VERSION 5.8 ;
BUSBITCHARS "[]" ;
DIVIDERCHAR "/" ;
UNITS
    DATABASE MICRONS 1000 ;
END UNITS

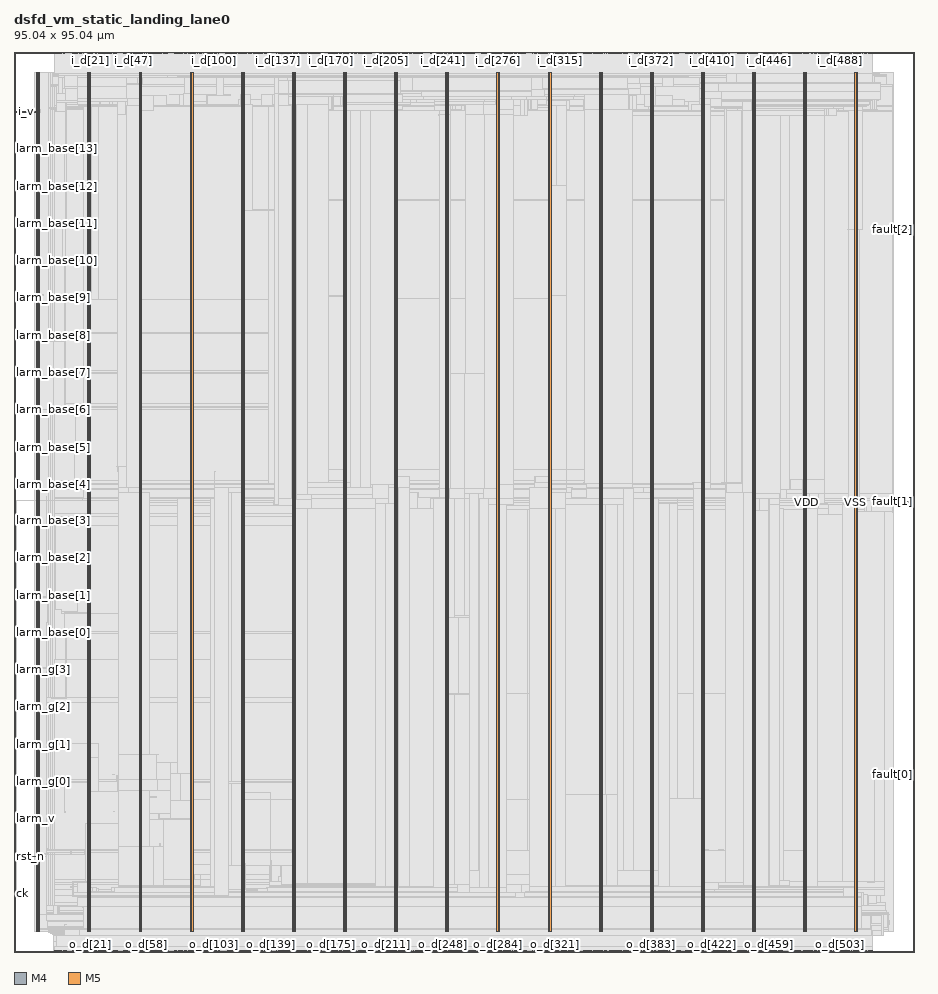
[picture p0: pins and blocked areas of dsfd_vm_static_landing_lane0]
MACRO dsfd_vm_static_landing_lane0
  FOREIGN dsfd_vm_static_landing_lane0 0 0 ;
  CLASS BLOCK ;
  SIZE 95.04 BY 95.04 ;
  PIN ck
    DIRECTION INPUT ;
    USE SIGNAL ;
    PORT
      LAYER M4 ;
        RECT  0 6.192 0.192 6.216 ;
    END
    PORT
      LAYER M4 ;
        RECT  0.156 6.192 0.275 6.216 ;
    END
  END ck
  PIN fault[0]
    DIRECTION OUTPUT ;
    USE SIGNAL ;
    PORT
      LAYER M4 ;
        RECT  94.848 18.72 95.04 18.744 ;
    END
    PORT
      LAYER M4 ;
        RECT  93.481 18.72 94.86 18.744 ;
    END
  END fault[0]
  PIN fault[1]
    DIRECTION OUTPUT ;
    USE SIGNAL ;
    PORT
      LAYER M4 ;
        RECT  94.848 47.52 95.04 47.544 ;
    END
    PORT
      LAYER M4 ;
        RECT  94.057 47.52 94.86 47.544 ;
    END
  END fault[1]
  PIN fault[2]
    DIRECTION OUTPUT ;
    USE SIGNAL ;
    PORT
      LAYER M4 ;
        RECT  94.848 76.32 95.04 76.344 ;
    END
    PORT
      LAYER M4 ;
        RECT  93.481 76.32 94.86 76.344 ;
    END
  END fault[2]
  PIN i_d[0]
    DIRECTION INPUT ;
    USE SIGNAL ;
    PORT
      LAYER M5 ;
        RECT  4.32 94.848 4.344 95.04 ;
    END
  END i_d[0]
  PIN i_d[100]
    DIRECTION INPUT ;
    USE SIGNAL ;
    PORT
      LAYER M5 ;
        RECT  21.12 94.848 21.144 95.04 ;
    END
  END i_d[100]
  PIN i_d[101]
    DIRECTION INPUT ;
    USE SIGNAL ;
    PORT
      LAYER M5 ;
        RECT  21.264 94.848 21.288 95.04 ;
    END
  END i_d[101]
  PIN i_d[102]
    DIRECTION INPUT ;
    USE SIGNAL ;
    PORT
      LAYER M5 ;
        RECT  21.408 94.848 21.432 95.04 ;
    END
  END i_d[102]
  PIN i_d[103]
    DIRECTION INPUT ;
    USE SIGNAL ;
    PORT
      LAYER M5 ;
        RECT  21.552 94.848 21.576 95.04 ;
    END
  END i_d[103]
  PIN i_d[104]
    DIRECTION INPUT ;
    USE SIGNAL ;
    PORT
      LAYER M5 ;
        RECT  22.368 94.848 22.392 95.04 ;
    END
  END i_d[104]
  PIN i_d[105]
    DIRECTION INPUT ;
    USE SIGNAL ;
    PORT
      LAYER M5 ;
        RECT  22.512 94.848 22.536 95.04 ;
    END
  END i_d[105]
  PIN i_d[106]
    DIRECTION INPUT ;
    USE SIGNAL ;
    PORT
      LAYER M5 ;
        RECT  22.656 94.848 22.68 95.04 ;
    END
  END i_d[106]
  PIN i_d[107]
    DIRECTION INPUT ;
    USE SIGNAL ;
    PORT
      LAYER M5 ;
        RECT  22.8 94.848 22.824 95.04 ;
    END
  END i_d[107]
  PIN i_d[108]
    DIRECTION INPUT ;
    USE SIGNAL ;
    PORT
      LAYER M5 ;
        RECT  22.944 94.848 22.968 95.04 ;
    END
  END i_d[108]
  PIN i_d[109]
    DIRECTION INPUT ;
    USE SIGNAL ;
    PORT
      LAYER M5 ;
        RECT  23.088 94.848 23.112 95.04 ;
    END
  END i_d[109]
  PIN i_d[10]
    DIRECTION INPUT ;
    USE SIGNAL ;
    PORT
      LAYER M5 ;
        RECT  6.432 94.848 6.456 95.04 ;
    END
  END i_d[10]
  PIN i_d[110]
    DIRECTION INPUT ;
    USE SIGNAL ;
    PORT
      LAYER M5 ;
        RECT  23.232 94.848 23.256 95.04 ;
    END
  END i_d[110]
  PIN i_d[111]
    DIRECTION INPUT ;
    USE SIGNAL ;
    PORT
      LAYER M5 ;
        RECT  23.376 94.848 23.4 95.04 ;
    END
  END i_d[111]
  PIN i_d[112]
    DIRECTION INPUT ;
    USE SIGNAL ;
    PORT
      LAYER M5 ;
        RECT  23.52 94.848 23.544 95.04 ;
    END
  END i_d[112]
  PIN i_d[113]
    DIRECTION INPUT ;
    USE SIGNAL ;
    PORT
      LAYER M5 ;
        RECT  23.664 94.848 23.688 95.04 ;
    END
  END i_d[113]
  PIN i_d[114]
    DIRECTION INPUT ;
    USE SIGNAL ;
    PORT
      LAYER M5 ;
        RECT  23.808 94.848 23.832 95.04 ;
    END
  END i_d[114]
  PIN i_d[115]
    DIRECTION INPUT ;
    USE SIGNAL ;
    PORT
      LAYER M5 ;
        RECT  23.952 94.848 23.976 95.04 ;
    END
  END i_d[115]
  PIN i_d[116]
    DIRECTION INPUT ;
    USE SIGNAL ;
    PORT
      LAYER M5 ;
        RECT  24.096 94.848 24.12 95.04 ;
    END
  END i_d[116]
  PIN i_d[117]
    DIRECTION INPUT ;
    USE SIGNAL ;
    PORT
      LAYER M5 ;
        RECT  24.24 94.848 24.264 95.04 ;
    END
  END i_d[117]
  PIN i_d[118]
    DIRECTION INPUT ;
    USE SIGNAL ;
    PORT
      LAYER M5 ;
        RECT  24.384 94.848 24.408 95.04 ;
    END
  END i_d[118]
  PIN i_d[119]
    DIRECTION INPUT ;
    USE SIGNAL ;
    PORT
      LAYER M5 ;
        RECT  24.528 94.848 24.552 95.04 ;
    END
  END i_d[119]
  PIN i_d[11]
    DIRECTION INPUT ;
    USE SIGNAL ;
    PORT
      LAYER M5 ;
        RECT  6.576 94.848 6.6 95.04 ;
    END
  END i_d[11]
  PIN i_d[120]
    DIRECTION INPUT ;
    USE SIGNAL ;
    PORT
      LAYER M5 ;
        RECT  24.816 94.848 24.84 95.04 ;
    END
  END i_d[120]
  PIN i_d[121]
    DIRECTION INPUT ;
    USE SIGNAL ;
    PORT
      LAYER M5 ;
        RECT  24.96 94.848 24.984 95.04 ;
    END
  END i_d[121]
  PIN i_d[122]
    DIRECTION INPUT ;
    USE SIGNAL ;
    PORT
      LAYER M5 ;
        RECT  25.104 94.848 25.128 95.04 ;
    END
  END i_d[122]
  PIN i_d[123]
    DIRECTION INPUT ;
    USE SIGNAL ;
    PORT
      LAYER M5 ;
        RECT  25.248 94.848 25.272 95.04 ;
    END
  END i_d[123]
  PIN i_d[124]
    DIRECTION INPUT ;
    USE SIGNAL ;
    PORT
      LAYER M5 ;
        RECT  25.392 94.848 25.416 95.04 ;
    END
  END i_d[124]
  PIN i_d[125]
    DIRECTION INPUT ;
    USE SIGNAL ;
    PORT
      LAYER M5 ;
        RECT  25.536 94.848 25.56 95.04 ;
    END
  END i_d[125]
  PIN i_d[126]
    DIRECTION INPUT ;
    USE SIGNAL ;
    PORT
      LAYER M5 ;
        RECT  25.68 94.848 25.704 95.04 ;
    END
  END i_d[126]
  PIN i_d[127]
    DIRECTION INPUT ;
    USE SIGNAL ;
    PORT
      LAYER M5 ;
        RECT  25.824 94.848 25.848 95.04 ;
    END
  END i_d[127]
  PIN i_d[128]
    DIRECTION INPUT ;
    USE SIGNAL ;
    PORT
      LAYER M5 ;
        RECT  25.968 94.848 25.992 95.04 ;
    END
  END i_d[128]
  PIN i_d[129]
    DIRECTION INPUT ;
    USE SIGNAL ;
    PORT
      LAYER M5 ;
        RECT  26.112 94.848 26.136 95.04 ;
    END
  END i_d[129]
  PIN i_d[12]
    DIRECTION INPUT ;
    USE SIGNAL ;
    PORT
      LAYER M5 ;
        RECT  6.72 94.848 6.744 95.04 ;
    END
  END i_d[12]
  PIN i_d[130]
    DIRECTION INPUT ;
    USE SIGNAL ;
    PORT
      LAYER M5 ;
        RECT  26.256 94.848 26.28 95.04 ;
    END
  END i_d[130]
  PIN i_d[131]
    DIRECTION INPUT ;
    USE SIGNAL ;
    PORT
      LAYER M5 ;
        RECT  26.4 94.848 26.424 95.04 ;
    END
  END i_d[131]
  PIN i_d[132]
    DIRECTION INPUT ;
    USE SIGNAL ;
    PORT
      LAYER M5 ;
        RECT  26.544 94.848 26.568 95.04 ;
    END
  END i_d[132]
  PIN i_d[133]
    DIRECTION INPUT ;
    USE SIGNAL ;
    PORT
      LAYER M5 ;
        RECT  26.688 94.848 26.712 95.04 ;
    END
  END i_d[133]
  PIN i_d[134]
    DIRECTION INPUT ;
    USE SIGNAL ;
    PORT
      LAYER M5 ;
        RECT  26.832 94.848 26.856 95.04 ;
    END
  END i_d[134]
  PIN i_d[135]
    DIRECTION INPUT ;
    USE SIGNAL ;
    PORT
      LAYER M5 ;
        RECT  26.976 94.848 27 95.04 ;
    END
  END i_d[135]
  PIN i_d[136]
    DIRECTION INPUT ;
    USE SIGNAL ;
    PORT
      LAYER M5 ;
        RECT  27.744 94.848 27.768 95.04 ;
    END
  END i_d[136]
  PIN i_d[137]
    DIRECTION INPUT ;
    USE SIGNAL ;
    PORT
      LAYER M5 ;
        RECT  27.888 94.848 27.912 95.04 ;
    END
  END i_d[137]
  PIN i_d[138]
    DIRECTION INPUT ;
    USE SIGNAL ;
    PORT
      LAYER M5 ;
        RECT  28.032 94.848 28.056 95.04 ;
    END
  END i_d[138]
  PIN i_d[139]
    DIRECTION INPUT ;
    USE SIGNAL ;
    PORT
      LAYER M5 ;
        RECT  28.176 94.848 28.2 95.04 ;
    END
  END i_d[139]
  PIN i_d[13]
    DIRECTION INPUT ;
    USE SIGNAL ;
    PORT
      LAYER M5 ;
        RECT  6.864 94.848 6.888 95.04 ;
    END
  END i_d[13]
  PIN i_d[140]
    DIRECTION INPUT ;
    USE SIGNAL ;
    PORT
      LAYER M5 ;
        RECT  28.32 94.848 28.344 95.04 ;
    END
  END i_d[140]
  PIN i_d[141]
    DIRECTION INPUT ;
    USE SIGNAL ;
    PORT
      LAYER M5 ;
        RECT  28.464 94.848 28.488 95.04 ;
    END
  END i_d[141]
  PIN i_d[142]
    DIRECTION INPUT ;
    USE SIGNAL ;
    PORT
      LAYER M5 ;
        RECT  28.608 94.848 28.632 95.04 ;
    END
  END i_d[142]
  PIN i_d[143]
    DIRECTION INPUT ;
    USE SIGNAL ;
    PORT
      LAYER M5 ;
        RECT  28.752 94.848 28.776 95.04 ;
    END
  END i_d[143]
  PIN i_d[144]
    DIRECTION INPUT ;
    USE SIGNAL ;
    PORT
      LAYER M5 ;
        RECT  28.896 94.848 28.92 95.04 ;
    END
  END i_d[144]
  PIN i_d[145]
    DIRECTION INPUT ;
    USE SIGNAL ;
    PORT
      LAYER M5 ;
        RECT  29.04 94.848 29.064 95.04 ;
    END
  END i_d[145]
  PIN i_d[146]
    DIRECTION INPUT ;
    USE SIGNAL ;
    PORT
      LAYER M5 ;
        RECT  29.184 94.848 29.208 95.04 ;
    END
  END i_d[146]
  PIN i_d[147]
    DIRECTION INPUT ;
    USE SIGNAL ;
    PORT
      LAYER M5 ;
        RECT  29.328 94.848 29.352 95.04 ;
    END
  END i_d[147]
  PIN i_d[148]
    DIRECTION INPUT ;
    USE SIGNAL ;
    PORT
      LAYER M5 ;
        RECT  29.472 94.848 29.496 95.04 ;
    END
  END i_d[148]
  PIN i_d[149]
    DIRECTION INPUT ;
    USE SIGNAL ;
    PORT
      LAYER M5 ;
        RECT  29.616 94.848 29.64 95.04 ;
    END
  END i_d[149]
  PIN i_d[14]
    DIRECTION INPUT ;
    USE SIGNAL ;
    PORT
      LAYER M5 ;
        RECT  7.008 94.848 7.032 95.04 ;
    END
  END i_d[14]
  PIN i_d[150]
    DIRECTION INPUT ;
    USE SIGNAL ;
    PORT
      LAYER M5 ;
        RECT  29.76 94.848 29.784 95.04 ;
    END
  END i_d[150]
  PIN i_d[151]
    DIRECTION INPUT ;
    USE SIGNAL ;
    PORT
      LAYER M5 ;
        RECT  29.904 94.848 29.928 95.04 ;
    END
  END i_d[151]
  PIN i_d[152]
    DIRECTION INPUT ;
    USE SIGNAL ;
    PORT
      LAYER M5 ;
        RECT  30.192 94.848 30.216 95.04 ;
    END
  END i_d[152]
  PIN i_d[153]
    DIRECTION INPUT ;
    USE SIGNAL ;
    PORT
      LAYER M5 ;
        RECT  30.336 94.848 30.36 95.04 ;
    END
  END i_d[153]
  PIN i_d[154]
    DIRECTION INPUT ;
    USE SIGNAL ;
    PORT
      LAYER M5 ;
        RECT  30.48 94.848 30.504 95.04 ;
    END
  END i_d[154]
  PIN i_d[155]
    DIRECTION INPUT ;
    USE SIGNAL ;
    PORT
      LAYER M5 ;
        RECT  30.624 94.848 30.648 95.04 ;
    END
  END i_d[155]
  PIN i_d[156]
    DIRECTION INPUT ;
    USE SIGNAL ;
    PORT
      LAYER M5 ;
        RECT  30.768 94.848 30.792 95.04 ;
    END
  END i_d[156]
  PIN i_d[157]
    DIRECTION INPUT ;
    USE SIGNAL ;
    PORT
      LAYER M5 ;
        RECT  30.912 94.848 30.936 95.04 ;
    END
  END i_d[157]
  PIN i_d[158]
    DIRECTION INPUT ;
    USE SIGNAL ;
    PORT
      LAYER M5 ;
        RECT  31.056 94.848 31.08 95.04 ;
    END
  END i_d[158]
  PIN i_d[159]
    DIRECTION INPUT ;
    USE SIGNAL ;
    PORT
      LAYER M5 ;
        RECT  31.2 94.848 31.224 95.04 ;
    END
  END i_d[159]
  PIN i_d[15]
    DIRECTION INPUT ;
    USE SIGNAL ;
    PORT
      LAYER M5 ;
        RECT  7.152 94.848 7.176 95.04 ;
    END
  END i_d[15]
  PIN i_d[160]
    DIRECTION INPUT ;
    USE SIGNAL ;
    PORT
      LAYER M5 ;
        RECT  31.344 94.848 31.368 95.04 ;
    END
  END i_d[160]
  PIN i_d[161]
    DIRECTION INPUT ;
    USE SIGNAL ;
    PORT
      LAYER M5 ;
        RECT  31.488 94.848 31.512 95.04 ;
    END
  END i_d[161]
  PIN i_d[162]
    DIRECTION INPUT ;
    USE SIGNAL ;
    PORT
      LAYER M5 ;
        RECT  31.632 94.848 31.656 95.04 ;
    END
  END i_d[162]
  PIN i_d[163]
    DIRECTION INPUT ;
    USE SIGNAL ;
    PORT
      LAYER M5 ;
        RECT  31.776 94.848 31.8 95.04 ;
    END
  END i_d[163]
  PIN i_d[164]
    DIRECTION INPUT ;
    USE SIGNAL ;
    PORT
      LAYER M5 ;
        RECT  31.92 94.848 31.944 95.04 ;
    END
  END i_d[164]
  PIN i_d[165]
    DIRECTION INPUT ;
    USE SIGNAL ;
    PORT
      LAYER M5 ;
        RECT  32.064 94.848 32.088 95.04 ;
    END
  END i_d[165]
  PIN i_d[166]
    DIRECTION INPUT ;
    USE SIGNAL ;
    PORT
      LAYER M5 ;
        RECT  32.208 94.848 32.232 95.04 ;
    END
  END i_d[166]
  PIN i_d[167]
    DIRECTION INPUT ;
    USE SIGNAL ;
    PORT
      LAYER M5 ;
        RECT  32.352 94.848 32.376 95.04 ;
    END
  END i_d[167]
  PIN i_d[168]
    DIRECTION INPUT ;
    USE SIGNAL ;
    PORT
      LAYER M5 ;
        RECT  33.168 94.848 33.192 95.04 ;
    END
  END i_d[168]
  PIN i_d[169]
    DIRECTION INPUT ;
    USE SIGNAL ;
    PORT
      LAYER M5 ;
        RECT  33.312 94.848 33.336 95.04 ;
    END
  END i_d[169]
  PIN i_d[16]
    DIRECTION INPUT ;
    USE SIGNAL ;
    PORT
      LAYER M5 ;
        RECT  7.296 94.848 7.32 95.04 ;
    END
  END i_d[16]
  PIN i_d[170]
    DIRECTION INPUT ;
    USE SIGNAL ;
    PORT
      LAYER M5 ;
        RECT  33.456 94.848 33.48 95.04 ;
    END
  END i_d[170]
  PIN i_d[171]
    DIRECTION INPUT ;
    USE SIGNAL ;
    PORT
      LAYER M5 ;
        RECT  33.6 94.848 33.624 95.04 ;
    END
  END i_d[171]
  PIN i_d[172]
    DIRECTION INPUT ;
    USE SIGNAL ;
    PORT
      LAYER M5 ;
        RECT  33.744 94.848 33.768 95.04 ;
    END
  END i_d[172]
  PIN i_d[173]
    DIRECTION INPUT ;
    USE SIGNAL ;
    PORT
      LAYER M5 ;
        RECT  33.888 94.848 33.912 95.04 ;
    END
  END i_d[173]
  PIN i_d[174]
    DIRECTION INPUT ;
    USE SIGNAL ;
    PORT
      LAYER M5 ;
        RECT  34.032 94.848 34.056 95.04 ;
    END
  END i_d[174]
  PIN i_d[175]
    DIRECTION INPUT ;
    USE SIGNAL ;
    PORT
      LAYER M5 ;
        RECT  34.176 94.848 34.2 95.04 ;
    END
  END i_d[175]
  PIN i_d[176]
    DIRECTION INPUT ;
    USE SIGNAL ;
    PORT
      LAYER M5 ;
        RECT  34.32 94.848 34.344 95.04 ;
    END
  END i_d[176]
  PIN i_d[177]
    DIRECTION INPUT ;
    USE SIGNAL ;
    PORT
      LAYER M5 ;
        RECT  34.464 94.848 34.488 95.04 ;
    END
  END i_d[177]
  PIN i_d[178]
    DIRECTION INPUT ;
    USE SIGNAL ;
    PORT
      LAYER M5 ;
        RECT  34.608 94.848 34.632 95.04 ;
    END
  END i_d[178]
  PIN i_d[179]
    DIRECTION INPUT ;
    USE SIGNAL ;
    PORT
      LAYER M5 ;
        RECT  34.752 94.848 34.776 95.04 ;
    END
  END i_d[179]
  PIN i_d[17]
    DIRECTION INPUT ;
    USE SIGNAL ;
    PORT
      LAYER M5 ;
        RECT  7.44 94.848 7.464 95.04 ;
    END
  END i_d[17]
  PIN i_d[180]
    DIRECTION INPUT ;
    USE SIGNAL ;
    PORT
      LAYER M5 ;
        RECT  34.896 94.848 34.92 95.04 ;
    END
  END i_d[180]
  PIN i_d[181]
    DIRECTION INPUT ;
    USE SIGNAL ;
    PORT
      LAYER M5 ;
        RECT  35.04 94.848 35.064 95.04 ;
    END
  END i_d[181]
  PIN i_d[182]
    DIRECTION INPUT ;
    USE SIGNAL ;
    PORT
      LAYER M5 ;
        RECT  35.184 94.848 35.208 95.04 ;
    END
  END i_d[182]
  PIN i_d[183]
    DIRECTION INPUT ;
    USE SIGNAL ;
    PORT
      LAYER M5 ;
        RECT  35.328 94.848 35.352 95.04 ;
    END
  END i_d[183]
  PIN i_d[184]
    DIRECTION INPUT ;
    USE SIGNAL ;
    PORT
      LAYER M5 ;
        RECT  35.616 94.848 35.64 95.04 ;
    END
  END i_d[184]
  PIN i_d[185]
    DIRECTION INPUT ;
    USE SIGNAL ;
    PORT
      LAYER M5 ;
        RECT  35.76 94.848 35.784 95.04 ;
    END
  END i_d[185]
  PIN i_d[186]
    DIRECTION INPUT ;
    USE SIGNAL ;
    PORT
      LAYER M5 ;
        RECT  35.904 94.848 35.928 95.04 ;
    END
  END i_d[186]
  PIN i_d[187]
    DIRECTION INPUT ;
    USE SIGNAL ;
    PORT
      LAYER M5 ;
        RECT  36.048 94.848 36.072 95.04 ;
    END
  END i_d[187]
  PIN i_d[188]
    DIRECTION INPUT ;
    USE SIGNAL ;
    PORT
      LAYER M5 ;
        RECT  36.192 94.848 36.216 95.04 ;
    END
  END i_d[188]
  PIN i_d[189]
    DIRECTION INPUT ;
    USE SIGNAL ;
    PORT
      LAYER M5 ;
        RECT  36.336 94.848 36.36 95.04 ;
    END
  END i_d[189]
  PIN i_d[18]
    DIRECTION INPUT ;
    USE SIGNAL ;
    PORT
      LAYER M5 ;
        RECT  7.584 94.848 7.608 95.04 ;
    END
  END i_d[18]
  PIN i_d[190]
    DIRECTION INPUT ;
    USE SIGNAL ;
    PORT
      LAYER M5 ;
        RECT  36.48 94.848 36.504 95.04 ;
    END
  END i_d[190]
  PIN i_d[191]
    DIRECTION INPUT ;
    USE SIGNAL ;
    PORT
      LAYER M5 ;
        RECT  36.624 94.848 36.648 95.04 ;
    END
  END i_d[191]
  PIN i_d[192]
    DIRECTION INPUT ;
    USE SIGNAL ;
    PORT
      LAYER M5 ;
        RECT  36.768 94.848 36.792 95.04 ;
    END
  END i_d[192]
  PIN i_d[193]
    DIRECTION INPUT ;
    USE SIGNAL ;
    PORT
      LAYER M5 ;
        RECT  36.912 94.848 36.936 95.04 ;
    END
  END i_d[193]
  PIN i_d[194]
    DIRECTION INPUT ;
    USE SIGNAL ;
    PORT
      LAYER M5 ;
        RECT  37.056 94.848 37.08 95.04 ;
    END
  END i_d[194]
  PIN i_d[195]
    DIRECTION INPUT ;
    USE SIGNAL ;
    PORT
      LAYER M5 ;
        RECT  37.2 94.848 37.224 95.04 ;
    END
  END i_d[195]
  PIN i_d[196]
    DIRECTION INPUT ;
    USE SIGNAL ;
    PORT
      LAYER M5 ;
        RECT  37.344 94.848 37.368 95.04 ;
    END
  END i_d[196]
  PIN i_d[197]
    DIRECTION INPUT ;
    USE SIGNAL ;
    PORT
      LAYER M5 ;
        RECT  37.488 94.848 37.512 95.04 ;
    END
  END i_d[197]
  PIN i_d[198]
    DIRECTION INPUT ;
    USE SIGNAL ;
    PORT
      LAYER M5 ;
        RECT  37.632 94.848 37.656 95.04 ;
    END
  END i_d[198]
  PIN i_d[199]
    DIRECTION INPUT ;
    USE SIGNAL ;
    PORT
      LAYER M5 ;
        RECT  37.776 94.848 37.8 95.04 ;
    END
  END i_d[199]
  PIN i_d[19]
    DIRECTION INPUT ;
    USE SIGNAL ;
    PORT
      LAYER M5 ;
        RECT  7.728 94.848 7.752 95.04 ;
    END
  END i_d[19]
  PIN i_d[1]
    DIRECTION INPUT ;
    USE SIGNAL ;
    PORT
      LAYER M5 ;
        RECT  4.464 94.848 4.488 95.04 ;
    END
  END i_d[1]
  PIN i_d[200]
    DIRECTION INPUT ;
    USE SIGNAL ;
    PORT
      LAYER M5 ;
        RECT  38.544 94.848 38.568 95.04 ;
    END
  END i_d[200]
  PIN i_d[201]
    DIRECTION INPUT ;
    USE SIGNAL ;
    PORT
      LAYER M5 ;
        RECT  38.688 94.848 38.712 95.04 ;
    END
  END i_d[201]
  PIN i_d[202]
    DIRECTION INPUT ;
    USE SIGNAL ;
    PORT
      LAYER M5 ;
        RECT  38.832 94.848 38.856 95.04 ;
    END
  END i_d[202]
  PIN i_d[203]
    DIRECTION INPUT ;
    USE SIGNAL ;
    PORT
      LAYER M5 ;
        RECT  38.976 94.848 39 95.04 ;
    END
  END i_d[203]
  PIN i_d[204]
    DIRECTION INPUT ;
    USE SIGNAL ;
    PORT
      LAYER M5 ;
        RECT  39.12 94.848 39.144 95.04 ;
    END
  END i_d[204]
  PIN i_d[205]
    DIRECTION INPUT ;
    USE SIGNAL ;
    PORT
      LAYER M5 ;
        RECT  39.264 94.848 39.288 95.04 ;
    END
  END i_d[205]
  PIN i_d[206]
    DIRECTION INPUT ;
    USE SIGNAL ;
    PORT
      LAYER M5 ;
        RECT  39.408 94.848 39.432 95.04 ;
    END
  END i_d[206]
  PIN i_d[207]
    DIRECTION INPUT ;
    USE SIGNAL ;
    PORT
      LAYER M5 ;
        RECT  39.552 94.848 39.576 95.04 ;
    END
  END i_d[207]
  PIN i_d[208]
    DIRECTION INPUT ;
    USE SIGNAL ;
    PORT
      LAYER M5 ;
        RECT  39.696 94.848 39.72 95.04 ;
    END
  END i_d[208]
  PIN i_d[209]
    DIRECTION INPUT ;
    USE SIGNAL ;
    PORT
      LAYER M5 ;
        RECT  39.84 94.848 39.864 95.04 ;
    END
  END i_d[209]
  PIN i_d[20]
    DIRECTION INPUT ;
    USE SIGNAL ;
    PORT
      LAYER M5 ;
        RECT  7.872 94.848 7.896 95.04 ;
    END
  END i_d[20]
  PIN i_d[210]
    DIRECTION INPUT ;
    USE SIGNAL ;
    PORT
      LAYER M5 ;
        RECT  39.984 94.848 40.008 95.04 ;
    END
  END i_d[210]
  PIN i_d[211]
    DIRECTION INPUT ;
    USE SIGNAL ;
    PORT
      LAYER M5 ;
        RECT  40.128 94.848 40.152 95.04 ;
    END
  END i_d[211]
  PIN i_d[212]
    DIRECTION INPUT ;
    USE SIGNAL ;
    PORT
      LAYER M5 ;
        RECT  40.272 94.848 40.296 95.04 ;
    END
  END i_d[212]
  PIN i_d[213]
    DIRECTION INPUT ;
    USE SIGNAL ;
    PORT
      LAYER M5 ;
        RECT  40.416 94.848 40.44 95.04 ;
    END
  END i_d[213]
  PIN i_d[214]
    DIRECTION INPUT ;
    USE SIGNAL ;
    PORT
      LAYER M5 ;
        RECT  40.56 94.848 40.584 95.04 ;
    END
  END i_d[214]
  PIN i_d[215]
    DIRECTION INPUT ;
    USE SIGNAL ;
    PORT
      LAYER M5 ;
        RECT  40.704 94.848 40.728 95.04 ;
    END
  END i_d[215]
  PIN i_d[216]
    DIRECTION INPUT ;
    USE SIGNAL ;
    PORT
      LAYER M5 ;
        RECT  40.992 94.848 41.016 95.04 ;
    END
  END i_d[216]
  PIN i_d[217]
    DIRECTION INPUT ;
    USE SIGNAL ;
    PORT
      LAYER M5 ;
        RECT  41.136 94.848 41.16 95.04 ;
    END
  END i_d[217]
  PIN i_d[218]
    DIRECTION INPUT ;
    USE SIGNAL ;
    PORT
      LAYER M5 ;
        RECT  41.28 94.848 41.304 95.04 ;
    END
  END i_d[218]
  PIN i_d[219]
    DIRECTION INPUT ;
    USE SIGNAL ;
    PORT
      LAYER M5 ;
        RECT  41.424 94.848 41.448 95.04 ;
    END
  END i_d[219]
  PIN i_d[21]
    DIRECTION INPUT ;
    USE SIGNAL ;
    PORT
      LAYER M5 ;
        RECT  8.016 94.848 8.04 95.04 ;
    END
  END i_d[21]
  PIN i_d[220]
    DIRECTION INPUT ;
    USE SIGNAL ;
    PORT
      LAYER M5 ;
        RECT  41.568 94.848 41.592 95.04 ;
    END
  END i_d[220]
  PIN i_d[221]
    DIRECTION INPUT ;
    USE SIGNAL ;
    PORT
      LAYER M5 ;
        RECT  41.712 94.848 41.736 95.04 ;
    END
  END i_d[221]
  PIN i_d[222]
    DIRECTION INPUT ;
    USE SIGNAL ;
    PORT
      LAYER M5 ;
        RECT  41.856 94.848 41.88 95.04 ;
    END
  END i_d[222]
  PIN i_d[223]
    DIRECTION INPUT ;
    USE SIGNAL ;
    PORT
      LAYER M5 ;
        RECT  42 94.848 42.024 95.04 ;
    END
  END i_d[223]
  PIN i_d[224]
    DIRECTION INPUT ;
    USE SIGNAL ;
    PORT
      LAYER M5 ;
        RECT  42.144 94.848 42.168 95.04 ;
    END
  END i_d[224]
  PIN i_d[225]
    DIRECTION INPUT ;
    USE SIGNAL ;
    PORT
      LAYER M5 ;
        RECT  42.288 94.848 42.312 95.04 ;
    END
  END i_d[225]
  PIN i_d[226]
    DIRECTION INPUT ;
    USE SIGNAL ;
    PORT
      LAYER M5 ;
        RECT  42.432 94.848 42.456 95.04 ;
    END
  END i_d[226]
  PIN i_d[227]
    DIRECTION INPUT ;
    USE SIGNAL ;
    PORT
      LAYER M5 ;
        RECT  42.576 94.848 42.6 95.04 ;
    END
  END i_d[227]
  PIN i_d[228]
    DIRECTION INPUT ;
    USE SIGNAL ;
    PORT
      LAYER M5 ;
        RECT  42.72 94.848 42.744 95.04 ;
    END
  END i_d[228]
  PIN i_d[229]
    DIRECTION INPUT ;
    USE SIGNAL ;
    PORT
      LAYER M5 ;
        RECT  42.864 94.848 42.888 95.04 ;
    END
  END i_d[229]
  PIN i_d[22]
    DIRECTION INPUT ;
    USE SIGNAL ;
    PORT
      LAYER M5 ;
        RECT  8.16 94.848 8.184 95.04 ;
    END
  END i_d[22]
  PIN i_d[230]
    DIRECTION INPUT ;
    USE SIGNAL ;
    PORT
      LAYER M5 ;
        RECT  43.008 94.848 43.032 95.04 ;
    END
  END i_d[230]
  PIN i_d[231]
    DIRECTION INPUT ;
    USE SIGNAL ;
    PORT
      LAYER M5 ;
        RECT  43.152 94.848 43.176 95.04 ;
    END
  END i_d[231]
  PIN i_d[232]
    DIRECTION INPUT ;
    USE SIGNAL ;
    PORT
      LAYER M5 ;
        RECT  43.968 94.848 43.992 95.04 ;
    END
  END i_d[232]
  PIN i_d[233]
    DIRECTION INPUT ;
    USE SIGNAL ;
    PORT
      LAYER M5 ;
        RECT  44.112 94.848 44.136 95.04 ;
    END
  END i_d[233]
  PIN i_d[234]
    DIRECTION INPUT ;
    USE SIGNAL ;
    PORT
      LAYER M5 ;
        RECT  44.256 94.848 44.28 95.04 ;
    END
  END i_d[234]
  PIN i_d[235]
    DIRECTION INPUT ;
    USE SIGNAL ;
    PORT
      LAYER M5 ;
        RECT  44.4 94.848 44.424 95.04 ;
    END
  END i_d[235]
  PIN i_d[236]
    DIRECTION INPUT ;
    USE SIGNAL ;
    PORT
      LAYER M5 ;
        RECT  44.544 94.848 44.568 95.04 ;
    END
  END i_d[236]
  PIN i_d[237]
    DIRECTION INPUT ;
    USE SIGNAL ;
    PORT
      LAYER M5 ;
        RECT  44.688 94.848 44.712 95.04 ;
    END
  END i_d[237]
  PIN i_d[238]
    DIRECTION INPUT ;
    USE SIGNAL ;
    PORT
      LAYER M5 ;
        RECT  44.832 94.848 44.856 95.04 ;
    END
  END i_d[238]
  PIN i_d[239]
    DIRECTION INPUT ;
    USE SIGNAL ;
    PORT
      LAYER M5 ;
        RECT  44.976 94.848 45 95.04 ;
    END
  END i_d[239]
  PIN i_d[23]
    DIRECTION INPUT ;
    USE SIGNAL ;
    PORT
      LAYER M5 ;
        RECT  8.304 94.848 8.328 95.04 ;
    END
  END i_d[23]
  PIN i_d[240]
    DIRECTION INPUT ;
    USE SIGNAL ;
    PORT
      LAYER M5 ;
        RECT  45.12 94.848 45.144 95.04 ;
    END
  END i_d[240]
  PIN i_d[241]
    DIRECTION INPUT ;
    USE SIGNAL ;
    PORT
      LAYER M5 ;
        RECT  45.264 94.848 45.288 95.04 ;
    END
  END i_d[241]
  PIN i_d[242]
    DIRECTION INPUT ;
    USE SIGNAL ;
    PORT
      LAYER M5 ;
        RECT  45.408 94.848 45.432 95.04 ;
    END
  END i_d[242]
  PIN i_d[243]
    DIRECTION INPUT ;
    USE SIGNAL ;
    PORT
      LAYER M5 ;
        RECT  45.552 94.848 45.576 95.04 ;
    END
  END i_d[243]
  PIN i_d[244]
    DIRECTION INPUT ;
    USE SIGNAL ;
    PORT
      LAYER M5 ;
        RECT  45.696 94.848 45.72 95.04 ;
    END
  END i_d[244]
  PIN i_d[245]
    DIRECTION INPUT ;
    USE SIGNAL ;
    PORT
      LAYER M5 ;
        RECT  45.84 94.848 45.864 95.04 ;
    END
  END i_d[245]
  PIN i_d[246]
    DIRECTION INPUT ;
    USE SIGNAL ;
    PORT
      LAYER M5 ;
        RECT  45.984 94.848 46.008 95.04 ;
    END
  END i_d[246]
  PIN i_d[247]
    DIRECTION INPUT ;
    USE SIGNAL ;
    PORT
      LAYER M5 ;
        RECT  46.128 94.848 46.152 95.04 ;
    END
  END i_d[247]
  PIN i_d[248]
    DIRECTION INPUT ;
    USE SIGNAL ;
    PORT
      LAYER M5 ;
        RECT  46.416 94.848 46.44 95.04 ;
    END
  END i_d[248]
  PIN i_d[249]
    DIRECTION INPUT ;
    USE SIGNAL ;
    PORT
      LAYER M5 ;
        RECT  46.56 94.848 46.584 95.04 ;
    END
  END i_d[249]
  PIN i_d[24]
    DIRECTION INPUT ;
    USE SIGNAL ;
    PORT
      LAYER M5 ;
        RECT  8.592 94.848 8.616 95.04 ;
    END
  END i_d[24]
  PIN i_d[250]
    DIRECTION INPUT ;
    USE SIGNAL ;
    PORT
      LAYER M5 ;
        RECT  46.704 94.848 46.728 95.04 ;
    END
  END i_d[250]
  PIN i_d[251]
    DIRECTION INPUT ;
    USE SIGNAL ;
    PORT
      LAYER M5 ;
        RECT  46.848 94.848 46.872 95.04 ;
    END
  END i_d[251]
  PIN i_d[252]
    DIRECTION INPUT ;
    USE SIGNAL ;
    PORT
      LAYER M5 ;
        RECT  46.992 94.848 47.016 95.04 ;
    END
  END i_d[252]
  PIN i_d[253]
    DIRECTION INPUT ;
    USE SIGNAL ;
    PORT
      LAYER M5 ;
        RECT  47.136 94.848 47.16 95.04 ;
    END
  END i_d[253]
  PIN i_d[254]
    DIRECTION INPUT ;
    USE SIGNAL ;
    PORT
      LAYER M5 ;
        RECT  47.28 94.848 47.304 95.04 ;
    END
  END i_d[254]
  PIN i_d[255]
    DIRECTION INPUT ;
    USE SIGNAL ;
    PORT
      LAYER M5 ;
        RECT  47.424 94.848 47.448 95.04 ;
    END
  END i_d[255]
  PIN i_d[256]
    DIRECTION INPUT ;
    USE SIGNAL ;
    PORT
      LAYER M5 ;
        RECT  47.568 94.848 47.592 95.04 ;
    END
  END i_d[256]
  PIN i_d[257]
    DIRECTION INPUT ;
    USE SIGNAL ;
    PORT
      LAYER M5 ;
        RECT  47.712 94.848 47.736 95.04 ;
    END
  END i_d[257]
  PIN i_d[258]
    DIRECTION INPUT ;
    USE SIGNAL ;
    PORT
      LAYER M5 ;
        RECT  47.856 94.848 47.88 95.04 ;
    END
  END i_d[258]
  PIN i_d[259]
    DIRECTION INPUT ;
    USE SIGNAL ;
    PORT
      LAYER M5 ;
        RECT  48 94.848 48.024 95.04 ;
    END
  END i_d[259]
  PIN i_d[25]
    DIRECTION INPUT ;
    USE SIGNAL ;
    PORT
      LAYER M5 ;
        RECT  8.736 94.848 8.76 95.04 ;
    END
  END i_d[25]
  PIN i_d[260]
    DIRECTION INPUT ;
    USE SIGNAL ;
    PORT
      LAYER M5 ;
        RECT  48.144 94.848 48.168 95.04 ;
    END
  END i_d[260]
  PIN i_d[261]
    DIRECTION INPUT ;
    USE SIGNAL ;
    PORT
      LAYER M5 ;
        RECT  48.288 94.848 48.312 95.04 ;
    END
  END i_d[261]
  PIN i_d[262]
    DIRECTION INPUT ;
    USE SIGNAL ;
    PORT
      LAYER M5 ;
        RECT  48.432 94.848 48.456 95.04 ;
    END
  END i_d[262]
  PIN i_d[263]
    DIRECTION INPUT ;
    USE SIGNAL ;
    PORT
      LAYER M5 ;
        RECT  48.576 94.848 48.6 95.04 ;
    END
  END i_d[263]
  PIN i_d[264]
    DIRECTION INPUT ;
    USE SIGNAL ;
    PORT
      LAYER M5 ;
        RECT  49.344 94.848 49.368 95.04 ;
    END
  END i_d[264]
  PIN i_d[265]
    DIRECTION INPUT ;
    USE SIGNAL ;
    PORT
      LAYER M5 ;
        RECT  49.488 94.848 49.512 95.04 ;
    END
  END i_d[265]
  PIN i_d[266]
    DIRECTION INPUT ;
    USE SIGNAL ;
    PORT
      LAYER M5 ;
        RECT  49.632 94.848 49.656 95.04 ;
    END
  END i_d[266]
  PIN i_d[267]
    DIRECTION INPUT ;
    USE SIGNAL ;
    PORT
      LAYER M5 ;
        RECT  49.776 94.848 49.8 95.04 ;
    END
  END i_d[267]
  PIN i_d[268]
    DIRECTION INPUT ;
    USE SIGNAL ;
    PORT
      LAYER M5 ;
        RECT  49.92 94.848 49.944 95.04 ;
    END
  END i_d[268]
  PIN i_d[269]
    DIRECTION INPUT ;
    USE SIGNAL ;
    PORT
      LAYER M5 ;
        RECT  50.064 94.848 50.088 95.04 ;
    END
  END i_d[269]
  PIN i_d[26]
    DIRECTION INPUT ;
    USE SIGNAL ;
    PORT
      LAYER M5 ;
        RECT  8.88 94.848 8.904 95.04 ;
    END
  END i_d[26]
  PIN i_d[270]
    DIRECTION INPUT ;
    USE SIGNAL ;
    PORT
      LAYER M5 ;
        RECT  50.208 94.848 50.232 95.04 ;
    END
  END i_d[270]
  PIN i_d[271]
    DIRECTION INPUT ;
    USE SIGNAL ;
    PORT
      LAYER M5 ;
        RECT  50.352 94.848 50.376 95.04 ;
    END
  END i_d[271]
  PIN i_d[272]
    DIRECTION INPUT ;
    USE SIGNAL ;
    PORT
      LAYER M5 ;
        RECT  50.496 94.848 50.52 95.04 ;
    END
  END i_d[272]
  PIN i_d[273]
    DIRECTION INPUT ;
    USE SIGNAL ;
    PORT
      LAYER M5 ;
        RECT  50.64 94.848 50.664 95.04 ;
    END
  END i_d[273]
  PIN i_d[274]
    DIRECTION INPUT ;
    USE SIGNAL ;
    PORT
      LAYER M5 ;
        RECT  50.784 94.848 50.808 95.04 ;
    END
  END i_d[274]
  PIN i_d[275]
    DIRECTION INPUT ;
    USE SIGNAL ;
    PORT
      LAYER M5 ;
        RECT  50.928 94.848 50.952 95.04 ;
    END
  END i_d[275]
  PIN i_d[276]
    DIRECTION INPUT ;
    USE SIGNAL ;
    PORT
      LAYER M5 ;
        RECT  51.072 94.848 51.096 95.04 ;
    END
  END i_d[276]
  PIN i_d[277]
    DIRECTION INPUT ;
    USE SIGNAL ;
    PORT
      LAYER M5 ;
        RECT  51.216 94.848 51.24 95.04 ;
    END
  END i_d[277]
  PIN i_d[278]
    DIRECTION INPUT ;
    USE SIGNAL ;
    PORT
      LAYER M5 ;
        RECT  51.36 94.848 51.384 95.04 ;
    END
  END i_d[278]
  PIN i_d[279]
    DIRECTION INPUT ;
    USE SIGNAL ;
    PORT
      LAYER M5 ;
        RECT  51.504 94.848 51.528 95.04 ;
    END
  END i_d[279]
  PIN i_d[27]
    DIRECTION INPUT ;
    USE SIGNAL ;
    PORT
      LAYER M5 ;
        RECT  9.024 94.848 9.048 95.04 ;
    END
  END i_d[27]
  PIN i_d[280]
    DIRECTION INPUT ;
    USE SIGNAL ;
    PORT
      LAYER M5 ;
        RECT  51.792 94.848 51.816 95.04 ;
    END
  END i_d[280]
  PIN i_d[281]
    DIRECTION INPUT ;
    USE SIGNAL ;
    PORT
      LAYER M5 ;
        RECT  51.936 94.848 51.96 95.04 ;
    END
  END i_d[281]
  PIN i_d[282]
    DIRECTION INPUT ;
    USE SIGNAL ;
    PORT
      LAYER M5 ;
        RECT  52.08 94.848 52.104 95.04 ;
    END
  END i_d[282]
  PIN i_d[283]
    DIRECTION INPUT ;
    USE SIGNAL ;
    PORT
      LAYER M5 ;
        RECT  52.224 94.848 52.248 95.04 ;
    END
  END i_d[283]
  PIN i_d[284]
    DIRECTION INPUT ;
    USE SIGNAL ;
    PORT
      LAYER M5 ;
        RECT  52.368 94.848 52.392 95.04 ;
    END
  END i_d[284]
  PIN i_d[285]
    DIRECTION INPUT ;
    USE SIGNAL ;
    PORT
      LAYER M5 ;
        RECT  52.512 94.848 52.536 95.04 ;
    END
  END i_d[285]
  PIN i_d[286]
    DIRECTION INPUT ;
    USE SIGNAL ;
    PORT
      LAYER M5 ;
        RECT  52.656 94.848 52.68 95.04 ;
    END
  END i_d[286]
  PIN i_d[287]
    DIRECTION INPUT ;
    USE SIGNAL ;
    PORT
      LAYER M5 ;
        RECT  52.8 94.848 52.824 95.04 ;
    END
  END i_d[287]
  PIN i_d[288]
    DIRECTION INPUT ;
    USE SIGNAL ;
    PORT
      LAYER M5 ;
        RECT  52.944 94.848 52.968 95.04 ;
    END
  END i_d[288]
  PIN i_d[289]
    DIRECTION INPUT ;
    USE SIGNAL ;
    PORT
      LAYER M5 ;
        RECT  53.088 94.848 53.112 95.04 ;
    END
  END i_d[289]
  PIN i_d[28]
    DIRECTION INPUT ;
    USE SIGNAL ;
    PORT
      LAYER M5 ;
        RECT  9.168 94.848 9.192 95.04 ;
    END
  END i_d[28]
  PIN i_d[290]
    DIRECTION INPUT ;
    USE SIGNAL ;
    PORT
      LAYER M5 ;
        RECT  53.232 94.848 53.256 95.04 ;
    END
  END i_d[290]
  PIN i_d[291]
    DIRECTION INPUT ;
    USE SIGNAL ;
    PORT
      LAYER M5 ;
        RECT  53.376 94.848 53.4 95.04 ;
    END
  END i_d[291]
  PIN i_d[292]
    DIRECTION INPUT ;
    USE SIGNAL ;
    PORT
      LAYER M5 ;
        RECT  53.52 94.848 53.544 95.04 ;
    END
  END i_d[292]
  PIN i_d[293]
    DIRECTION INPUT ;
    USE SIGNAL ;
    PORT
      LAYER M5 ;
        RECT  53.664 94.848 53.688 95.04 ;
    END
  END i_d[293]
  PIN i_d[294]
    DIRECTION INPUT ;
    USE SIGNAL ;
    PORT
      LAYER M5 ;
        RECT  53.808 94.848 53.832 95.04 ;
    END
  END i_d[294]
  PIN i_d[295]
    DIRECTION INPUT ;
    USE SIGNAL ;
    PORT
      LAYER M5 ;
        RECT  53.952 94.848 53.976 95.04 ;
    END
  END i_d[295]
  PIN i_d[296]
    DIRECTION INPUT ;
    USE SIGNAL ;
    PORT
      LAYER M5 ;
        RECT  54.768 94.848 54.792 95.04 ;
    END
  END i_d[296]
  PIN i_d[297]
    DIRECTION INPUT ;
    USE SIGNAL ;
    PORT
      LAYER M5 ;
        RECT  54.912 94.848 54.936 95.04 ;
    END
  END i_d[297]
  PIN i_d[298]
    DIRECTION INPUT ;
    USE SIGNAL ;
    PORT
      LAYER M5 ;
        RECT  55.056 94.848 55.08 95.04 ;
    END
  END i_d[298]
  PIN i_d[299]
    DIRECTION INPUT ;
    USE SIGNAL ;
    PORT
      LAYER M5 ;
        RECT  55.2 94.848 55.224 95.04 ;
    END
  END i_d[299]
  PIN i_d[29]
    DIRECTION INPUT ;
    USE SIGNAL ;
    PORT
      LAYER M5 ;
        RECT  9.312 94.848 9.336 95.04 ;
    END
  END i_d[29]
  PIN i_d[2]
    DIRECTION INPUT ;
    USE SIGNAL ;
    PORT
      LAYER M5 ;
        RECT  4.608 94.848 4.632 95.04 ;
    END
  END i_d[2]
  PIN i_d[300]
    DIRECTION INPUT ;
    USE SIGNAL ;
    PORT
      LAYER M5 ;
        RECT  55.344 94.848 55.368 95.04 ;
    END
  END i_d[300]
  PIN i_d[301]
    DIRECTION INPUT ;
    USE SIGNAL ;
    PORT
      LAYER M5 ;
        RECT  55.488 94.848 55.512 95.04 ;
    END
  END i_d[301]
  PIN i_d[302]
    DIRECTION INPUT ;
    USE SIGNAL ;
    PORT
      LAYER M5 ;
        RECT  55.632 94.848 55.656 95.04 ;
    END
  END i_d[302]
  PIN i_d[303]
    DIRECTION INPUT ;
    USE SIGNAL ;
    PORT
      LAYER M5 ;
        RECT  55.776 94.848 55.8 95.04 ;
    END
  END i_d[303]
  PIN i_d[304]
    DIRECTION INPUT ;
    USE SIGNAL ;
    PORT
      LAYER M5 ;
        RECT  55.92 94.848 55.944 95.04 ;
    END
  END i_d[304]
  PIN i_d[305]
    DIRECTION INPUT ;
    USE SIGNAL ;
    PORT
      LAYER M5 ;
        RECT  56.064 94.848 56.088 95.04 ;
    END
  END i_d[305]
  PIN i_d[306]
    DIRECTION INPUT ;
    USE SIGNAL ;
    PORT
      LAYER M5 ;
        RECT  56.208 94.848 56.232 95.04 ;
    END
  END i_d[306]
  PIN i_d[307]
    DIRECTION INPUT ;
    USE SIGNAL ;
    PORT
      LAYER M5 ;
        RECT  56.352 94.848 56.376 95.04 ;
    END
  END i_d[307]
  PIN i_d[308]
    DIRECTION INPUT ;
    USE SIGNAL ;
    PORT
      LAYER M5 ;
        RECT  56.496 94.848 56.52 95.04 ;
    END
  END i_d[308]
  PIN i_d[309]
    DIRECTION INPUT ;
    USE SIGNAL ;
    PORT
      LAYER M5 ;
        RECT  56.64 94.848 56.664 95.04 ;
    END
  END i_d[309]
  PIN i_d[30]
    DIRECTION INPUT ;
    USE SIGNAL ;
    PORT
      LAYER M5 ;
        RECT  9.456 94.848 9.48 95.04 ;
    END
  END i_d[30]
  PIN i_d[310]
    DIRECTION INPUT ;
    USE SIGNAL ;
    PORT
      LAYER M5 ;
        RECT  56.784 94.848 56.808 95.04 ;
    END
  END i_d[310]
  PIN i_d[311]
    DIRECTION INPUT ;
    USE SIGNAL ;
    PORT
      LAYER M5 ;
        RECT  56.928 94.848 56.952 95.04 ;
    END
  END i_d[311]
  PIN i_d[312]
    DIRECTION INPUT ;
    USE SIGNAL ;
    PORT
      LAYER M5 ;
        RECT  57.216 94.848 57.24 95.04 ;
    END
  END i_d[312]
  PIN i_d[313]
    DIRECTION INPUT ;
    USE SIGNAL ;
    PORT
      LAYER M5 ;
        RECT  57.36 94.848 57.384 95.04 ;
    END
  END i_d[313]
  PIN i_d[314]
    DIRECTION INPUT ;
    USE SIGNAL ;
    PORT
      LAYER M5 ;
        RECT  57.504 94.848 57.528 95.04 ;
    END
  END i_d[314]
  PIN i_d[315]
    DIRECTION INPUT ;
    USE SIGNAL ;
    PORT
      LAYER M5 ;
        RECT  57.648 94.848 57.672 95.04 ;
    END
  END i_d[315]
  PIN i_d[316]
    DIRECTION INPUT ;
    USE SIGNAL ;
    PORT
      LAYER M5 ;
        RECT  57.792 94.848 57.816 95.04 ;
    END
  END i_d[316]
  PIN i_d[317]
    DIRECTION INPUT ;
    USE SIGNAL ;
    PORT
      LAYER M5 ;
        RECT  57.936 94.848 57.96 95.04 ;
    END
  END i_d[317]
  PIN i_d[318]
    DIRECTION INPUT ;
    USE SIGNAL ;
    PORT
      LAYER M5 ;
        RECT  58.08 94.848 58.104 95.04 ;
    END
  END i_d[318]
  PIN i_d[319]
    DIRECTION INPUT ;
    USE SIGNAL ;
    PORT
      LAYER M5 ;
        RECT  58.224 94.848 58.248 95.04 ;
    END
  END i_d[319]
  PIN i_d[31]
    DIRECTION INPUT ;
    USE SIGNAL ;
    PORT
      LAYER M5 ;
        RECT  9.6 94.848 9.624 95.04 ;
    END
  END i_d[31]
  PIN i_d[320]
    DIRECTION INPUT ;
    USE SIGNAL ;
    PORT
      LAYER M5 ;
        RECT  58.368 94.848 58.392 95.04 ;
    END
  END i_d[320]
  PIN i_d[321]
    DIRECTION INPUT ;
    USE SIGNAL ;
    PORT
      LAYER M5 ;
        RECT  58.512 94.848 58.536 95.04 ;
    END
  END i_d[321]
  PIN i_d[322]
    DIRECTION INPUT ;
    USE SIGNAL ;
    PORT
      LAYER M5 ;
        RECT  58.656 94.848 58.68 95.04 ;
    END
  END i_d[322]
  PIN i_d[323]
    DIRECTION INPUT ;
    USE SIGNAL ;
    PORT
      LAYER M5 ;
        RECT  58.8 94.848 58.824 95.04 ;
    END
  END i_d[323]
  PIN i_d[324]
    DIRECTION INPUT ;
    USE SIGNAL ;
    PORT
      LAYER M5 ;
        RECT  58.944 94.848 58.968 95.04 ;
    END
  END i_d[324]
  PIN i_d[325]
    DIRECTION INPUT ;
    USE SIGNAL ;
    PORT
      LAYER M5 ;
        RECT  59.088 94.848 59.112 95.04 ;
    END
  END i_d[325]
  PIN i_d[326]
    DIRECTION INPUT ;
    USE SIGNAL ;
    PORT
      LAYER M5 ;
        RECT  59.232 94.848 59.256 95.04 ;
    END
  END i_d[326]
  PIN i_d[327]
    DIRECTION INPUT ;
    USE SIGNAL ;
    PORT
      LAYER M5 ;
        RECT  59.376 94.848 59.4 95.04 ;
    END
  END i_d[327]
  PIN i_d[328]
    DIRECTION INPUT ;
    USE SIGNAL ;
    PORT
      LAYER M5 ;
        RECT  60.144 94.848 60.168 95.04 ;
    END
  END i_d[328]
  PIN i_d[329]
    DIRECTION INPUT ;
    USE SIGNAL ;
    PORT
      LAYER M5 ;
        RECT  60.288 94.848 60.312 95.04 ;
    END
  END i_d[329]
  PIN i_d[32]
    DIRECTION INPUT ;
    USE SIGNAL ;
    PORT
      LAYER M5 ;
        RECT  9.744 94.848 9.768 95.04 ;
    END
  END i_d[32]
  PIN i_d[330]
    DIRECTION INPUT ;
    USE SIGNAL ;
    PORT
      LAYER M5 ;
        RECT  60.432 94.848 60.456 95.04 ;
    END
  END i_d[330]
  PIN i_d[331]
    DIRECTION INPUT ;
    USE SIGNAL ;
    PORT
      LAYER M5 ;
        RECT  60.576 94.848 60.6 95.04 ;
    END
  END i_d[331]
  PIN i_d[332]
    DIRECTION INPUT ;
    USE SIGNAL ;
    PORT
      LAYER M5 ;
        RECT  60.72 94.848 60.744 95.04 ;
    END
  END i_d[332]
  PIN i_d[333]
    DIRECTION INPUT ;
    USE SIGNAL ;
    PORT
      LAYER M5 ;
        RECT  60.864 94.848 60.888 95.04 ;
    END
  END i_d[333]
  PIN i_d[334]
    DIRECTION INPUT ;
    USE SIGNAL ;
    PORT
      LAYER M5 ;
        RECT  61.008 94.848 61.032 95.04 ;
    END
  END i_d[334]
  PIN i_d[335]
    DIRECTION INPUT ;
    USE SIGNAL ;
    PORT
      LAYER M5 ;
        RECT  61.152 94.848 61.176 95.04 ;
    END
  END i_d[335]
  PIN i_d[336]
    DIRECTION INPUT ;
    USE SIGNAL ;
    PORT
      LAYER M5 ;
        RECT  61.296 94.848 61.32 95.04 ;
    END
  END i_d[336]
  PIN i_d[337]
    DIRECTION INPUT ;
    USE SIGNAL ;
    PORT
      LAYER M5 ;
        RECT  61.44 94.848 61.464 95.04 ;
    END
  END i_d[337]
  PIN i_d[338]
    DIRECTION INPUT ;
    USE SIGNAL ;
    PORT
      LAYER M5 ;
        RECT  61.584 94.848 61.608 95.04 ;
    END
  END i_d[338]
  PIN i_d[339]
    DIRECTION INPUT ;
    USE SIGNAL ;
    PORT
      LAYER M5 ;
        RECT  61.728 94.848 61.752 95.04 ;
    END
  END i_d[339]
  PIN i_d[33]
    DIRECTION INPUT ;
    USE SIGNAL ;
    PORT
      LAYER M5 ;
        RECT  9.888 94.848 9.912 95.04 ;
    END
  END i_d[33]
  PIN i_d[340]
    DIRECTION INPUT ;
    USE SIGNAL ;
    PORT
      LAYER M5 ;
        RECT  61.872 94.848 61.896 95.04 ;
    END
  END i_d[340]
  PIN i_d[341]
    DIRECTION INPUT ;
    USE SIGNAL ;
    PORT
      LAYER M5 ;
        RECT  62.016 94.848 62.04 95.04 ;
    END
  END i_d[341]
  PIN i_d[342]
    DIRECTION INPUT ;
    USE SIGNAL ;
    PORT
      LAYER M5 ;
        RECT  62.16 94.848 62.184 95.04 ;
    END
  END i_d[342]
  PIN i_d[343]
    DIRECTION INPUT ;
    USE SIGNAL ;
    PORT
      LAYER M5 ;
        RECT  62.304 94.848 62.328 95.04 ;
    END
  END i_d[343]
  PIN i_d[344]
    DIRECTION INPUT ;
    USE SIGNAL ;
    PORT
      LAYER M5 ;
        RECT  62.592 94.848 62.616 95.04 ;
    END
  END i_d[344]
  PIN i_d[345]
    DIRECTION INPUT ;
    USE SIGNAL ;
    PORT
      LAYER M5 ;
        RECT  62.736 94.848 62.76 95.04 ;
    END
  END i_d[345]
  PIN i_d[346]
    DIRECTION INPUT ;
    USE SIGNAL ;
    PORT
      LAYER M5 ;
        RECT  62.88 94.848 62.904 95.04 ;
    END
  END i_d[346]
  PIN i_d[347]
    DIRECTION INPUT ;
    USE SIGNAL ;
    PORT
      LAYER M5 ;
        RECT  63.024 94.848 63.048 95.04 ;
    END
  END i_d[347]
  PIN i_d[348]
    DIRECTION INPUT ;
    USE SIGNAL ;
    PORT
      LAYER M5 ;
        RECT  63.168 94.848 63.192 95.04 ;
    END
  END i_d[348]
  PIN i_d[349]
    DIRECTION INPUT ;
    USE SIGNAL ;
    PORT
      LAYER M5 ;
        RECT  63.312 94.848 63.336 95.04 ;
    END
  END i_d[349]
  PIN i_d[34]
    DIRECTION INPUT ;
    USE SIGNAL ;
    PORT
      LAYER M5 ;
        RECT  10.032 94.848 10.056 95.04 ;
    END
  END i_d[34]
  PIN i_d[350]
    DIRECTION INPUT ;
    USE SIGNAL ;
    PORT
      LAYER M5 ;
        RECT  63.456 94.848 63.48 95.04 ;
    END
  END i_d[350]
  PIN i_d[351]
    DIRECTION INPUT ;
    USE SIGNAL ;
    PORT
      LAYER M5 ;
        RECT  63.6 94.848 63.624 95.04 ;
    END
  END i_d[351]
  PIN i_d[352]
    DIRECTION INPUT ;
    USE SIGNAL ;
    PORT
      LAYER M5 ;
        RECT  63.744 94.848 63.768 95.04 ;
    END
  END i_d[352]
  PIN i_d[353]
    DIRECTION INPUT ;
    USE SIGNAL ;
    PORT
      LAYER M5 ;
        RECT  63.888 94.848 63.912 95.04 ;
    END
  END i_d[353]
  PIN i_d[354]
    DIRECTION INPUT ;
    USE SIGNAL ;
    PORT
      LAYER M5 ;
        RECT  64.032 94.848 64.056 95.04 ;
    END
  END i_d[354]
  PIN i_d[355]
    DIRECTION INPUT ;
    USE SIGNAL ;
    PORT
      LAYER M5 ;
        RECT  64.176 94.848 64.2 95.04 ;
    END
  END i_d[355]
  PIN i_d[356]
    DIRECTION INPUT ;
    USE SIGNAL ;
    PORT
      LAYER M5 ;
        RECT  64.32 94.848 64.344 95.04 ;
    END
  END i_d[356]
  PIN i_d[357]
    DIRECTION INPUT ;
    USE SIGNAL ;
    PORT
      LAYER M5 ;
        RECT  64.464 94.848 64.488 95.04 ;
    END
  END i_d[357]
  PIN i_d[358]
    DIRECTION INPUT ;
    USE SIGNAL ;
    PORT
      LAYER M5 ;
        RECT  64.608 94.848 64.632 95.04 ;
    END
  END i_d[358]
  PIN i_d[359]
    DIRECTION INPUT ;
    USE SIGNAL ;
    PORT
      LAYER M5 ;
        RECT  64.752 94.848 64.776 95.04 ;
    END
  END i_d[359]
  PIN i_d[35]
    DIRECTION INPUT ;
    USE SIGNAL ;
    PORT
      LAYER M5 ;
        RECT  10.176 94.848 10.2 95.04 ;
    END
  END i_d[35]
  PIN i_d[360]
    DIRECTION INPUT ;
    USE SIGNAL ;
    PORT
      LAYER M5 ;
        RECT  65.568 94.848 65.592 95.04 ;
    END
  END i_d[360]
  PIN i_d[361]
    DIRECTION INPUT ;
    USE SIGNAL ;
    PORT
      LAYER M5 ;
        RECT  65.712 94.848 65.736 95.04 ;
    END
  END i_d[361]
  PIN i_d[362]
    DIRECTION INPUT ;
    USE SIGNAL ;
    PORT
      LAYER M5 ;
        RECT  65.856 94.848 65.88 95.04 ;
    END
  END i_d[362]
  PIN i_d[363]
    DIRECTION INPUT ;
    USE SIGNAL ;
    PORT
      LAYER M5 ;
        RECT  66 94.848 66.024 95.04 ;
    END
  END i_d[363]
  PIN i_d[364]
    DIRECTION INPUT ;
    USE SIGNAL ;
    PORT
      LAYER M5 ;
        RECT  66.144 94.848 66.168 95.04 ;
    END
  END i_d[364]
  PIN i_d[365]
    DIRECTION INPUT ;
    USE SIGNAL ;
    PORT
      LAYER M5 ;
        RECT  66.288 94.848 66.312 95.04 ;
    END
  END i_d[365]
  PIN i_d[366]
    DIRECTION INPUT ;
    USE SIGNAL ;
    PORT
      LAYER M5 ;
        RECT  66.432 94.848 66.456 95.04 ;
    END
  END i_d[366]
  PIN i_d[367]
    DIRECTION INPUT ;
    USE SIGNAL ;
    PORT
      LAYER M5 ;
        RECT  66.576 94.848 66.6 95.04 ;
    END
  END i_d[367]
  PIN i_d[368]
    DIRECTION INPUT ;
    USE SIGNAL ;
    PORT
      LAYER M5 ;
        RECT  66.72 94.848 66.744 95.04 ;
    END
  END i_d[368]
  PIN i_d[369]
    DIRECTION INPUT ;
    USE SIGNAL ;
    PORT
      LAYER M5 ;
        RECT  66.864 94.848 66.888 95.04 ;
    END
  END i_d[369]
  PIN i_d[36]
    DIRECTION INPUT ;
    USE SIGNAL ;
    PORT
      LAYER M5 ;
        RECT  10.32 94.848 10.344 95.04 ;
    END
  END i_d[36]
  PIN i_d[370]
    DIRECTION INPUT ;
    USE SIGNAL ;
    PORT
      LAYER M5 ;
        RECT  67.008 94.848 67.032 95.04 ;
    END
  END i_d[370]
  PIN i_d[371]
    DIRECTION INPUT ;
    USE SIGNAL ;
    PORT
      LAYER M5 ;
        RECT  67.152 94.848 67.176 95.04 ;
    END
  END i_d[371]
  PIN i_d[372]
    DIRECTION INPUT ;
    USE SIGNAL ;
    PORT
      LAYER M5 ;
        RECT  67.296 94.848 67.32 95.04 ;
    END
  END i_d[372]
  PIN i_d[373]
    DIRECTION INPUT ;
    USE SIGNAL ;
    PORT
      LAYER M5 ;
        RECT  67.44 94.848 67.464 95.04 ;
    END
  END i_d[373]
  PIN i_d[374]
    DIRECTION INPUT ;
    USE SIGNAL ;
    PORT
      LAYER M5 ;
        RECT  67.584 94.848 67.608 95.04 ;
    END
  END i_d[374]
  PIN i_d[375]
    DIRECTION INPUT ;
    USE SIGNAL ;
    PORT
      LAYER M5 ;
        RECT  67.728 94.848 67.752 95.04 ;
    END
  END i_d[375]
  PIN i_d[376]
    DIRECTION INPUT ;
    USE SIGNAL ;
    PORT
      LAYER M5 ;
        RECT  68.016 94.848 68.04 95.04 ;
    END
  END i_d[376]
  PIN i_d[377]
    DIRECTION INPUT ;
    USE SIGNAL ;
    PORT
      LAYER M5 ;
        RECT  68.16 94.848 68.184 95.04 ;
    END
  END i_d[377]
  PIN i_d[378]
    DIRECTION INPUT ;
    USE SIGNAL ;
    PORT
      LAYER M5 ;
        RECT  68.304 94.848 68.328 95.04 ;
    END
  END i_d[378]
  PIN i_d[379]
    DIRECTION INPUT ;
    USE SIGNAL ;
    PORT
      LAYER M5 ;
        RECT  68.448 94.848 68.472 95.04 ;
    END
  END i_d[379]
  PIN i_d[37]
    DIRECTION INPUT ;
    USE SIGNAL ;
    PORT
      LAYER M5 ;
        RECT  10.464 94.848 10.488 95.04 ;
    END
  END i_d[37]
  PIN i_d[380]
    DIRECTION INPUT ;
    USE SIGNAL ;
    PORT
      LAYER M5 ;
        RECT  68.592 94.848 68.616 95.04 ;
    END
  END i_d[380]
  PIN i_d[381]
    DIRECTION INPUT ;
    USE SIGNAL ;
    PORT
      LAYER M5 ;
        RECT  68.736 94.848 68.76 95.04 ;
    END
  END i_d[381]
  PIN i_d[382]
    DIRECTION INPUT ;
    USE SIGNAL ;
    PORT
      LAYER M5 ;
        RECT  68.88 94.848 68.904 95.04 ;
    END
  END i_d[382]
  PIN i_d[383]
    DIRECTION INPUT ;
    USE SIGNAL ;
    PORT
      LAYER M5 ;
        RECT  69.024 94.848 69.048 95.04 ;
    END
  END i_d[383]
  PIN i_d[384]
    DIRECTION INPUT ;
    USE SIGNAL ;
    PORT
      LAYER M5 ;
        RECT  69.168 94.848 69.192 95.04 ;
    END
  END i_d[384]
  PIN i_d[385]
    DIRECTION INPUT ;
    USE SIGNAL ;
    PORT
      LAYER M5 ;
        RECT  69.312 94.848 69.336 95.04 ;
    END
  END i_d[385]
  PIN i_d[386]
    DIRECTION INPUT ;
    USE SIGNAL ;
    PORT
      LAYER M5 ;
        RECT  69.456 94.848 69.48 95.04 ;
    END
  END i_d[386]
  PIN i_d[387]
    DIRECTION INPUT ;
    USE SIGNAL ;
    PORT
      LAYER M5 ;
        RECT  69.6 94.848 69.624 95.04 ;
    END
  END i_d[387]
  PIN i_d[388]
    DIRECTION INPUT ;
    USE SIGNAL ;
    PORT
      LAYER M5 ;
        RECT  69.744 94.848 69.768 95.04 ;
    END
  END i_d[388]
  PIN i_d[389]
    DIRECTION INPUT ;
    USE SIGNAL ;
    PORT
      LAYER M5 ;
        RECT  69.888 94.848 69.912 95.04 ;
    END
  END i_d[389]
  PIN i_d[38]
    DIRECTION INPUT ;
    USE SIGNAL ;
    PORT
      LAYER M5 ;
        RECT  10.608 94.848 10.632 95.04 ;
    END
  END i_d[38]
  PIN i_d[390]
    DIRECTION INPUT ;
    USE SIGNAL ;
    PORT
      LAYER M5 ;
        RECT  70.032 94.848 70.056 95.04 ;
    END
  END i_d[390]
  PIN i_d[391]
    DIRECTION INPUT ;
    USE SIGNAL ;
    PORT
      LAYER M5 ;
        RECT  70.176 94.848 70.2 95.04 ;
    END
  END i_d[391]
  PIN i_d[392]
    DIRECTION INPUT ;
    USE SIGNAL ;
    PORT
      LAYER M5 ;
        RECT  70.944 94.848 70.968 95.04 ;
    END
  END i_d[392]
  PIN i_d[393]
    DIRECTION INPUT ;
    USE SIGNAL ;
    PORT
      LAYER M5 ;
        RECT  71.088 94.848 71.112 95.04 ;
    END
  END i_d[393]
  PIN i_d[394]
    DIRECTION INPUT ;
    USE SIGNAL ;
    PORT
      LAYER M5 ;
        RECT  71.232 94.848 71.256 95.04 ;
    END
  END i_d[394]
  PIN i_d[395]
    DIRECTION INPUT ;
    USE SIGNAL ;
    PORT
      LAYER M5 ;
        RECT  71.376 94.848 71.4 95.04 ;
    END
  END i_d[395]
  PIN i_d[396]
    DIRECTION INPUT ;
    USE SIGNAL ;
    PORT
      LAYER M5 ;
        RECT  71.52 94.848 71.544 95.04 ;
    END
  END i_d[396]
  PIN i_d[397]
    DIRECTION INPUT ;
    USE SIGNAL ;
    PORT
      LAYER M5 ;
        RECT  71.664 94.848 71.688 95.04 ;
    END
  END i_d[397]
  PIN i_d[398]
    DIRECTION INPUT ;
    USE SIGNAL ;
    PORT
      LAYER M5 ;
        RECT  71.808 94.848 71.832 95.04 ;
    END
  END i_d[398]
  PIN i_d[399]
    DIRECTION INPUT ;
    USE SIGNAL ;
    PORT
      LAYER M5 ;
        RECT  71.952 94.848 71.976 95.04 ;
    END
  END i_d[399]
  PIN i_d[39]
    DIRECTION INPUT ;
    USE SIGNAL ;
    PORT
      LAYER M5 ;
        RECT  10.752 94.848 10.776 95.04 ;
    END
  END i_d[39]
  PIN i_d[3]
    DIRECTION INPUT ;
    USE SIGNAL ;
    PORT
      LAYER M5 ;
        RECT  4.752 94.848 4.776 95.04 ;
    END
  END i_d[3]
  PIN i_d[400]
    DIRECTION INPUT ;
    USE SIGNAL ;
    PORT
      LAYER M5 ;
        RECT  72.096 94.848 72.12 95.04 ;
    END
  END i_d[400]
  PIN i_d[401]
    DIRECTION INPUT ;
    USE SIGNAL ;
    PORT
      LAYER M5 ;
        RECT  72.24 94.848 72.264 95.04 ;
    END
  END i_d[401]
  PIN i_d[402]
    DIRECTION INPUT ;
    USE SIGNAL ;
    PORT
      LAYER M5 ;
        RECT  72.384 94.848 72.408 95.04 ;
    END
  END i_d[402]
  PIN i_d[403]
    DIRECTION INPUT ;
    USE SIGNAL ;
    PORT
      LAYER M5 ;
        RECT  72.528 94.848 72.552 95.04 ;
    END
  END i_d[403]
  PIN i_d[404]
    DIRECTION INPUT ;
    USE SIGNAL ;
    PORT
      LAYER M5 ;
        RECT  72.672 94.848 72.696 95.04 ;
    END
  END i_d[404]
  PIN i_d[405]
    DIRECTION INPUT ;
    USE SIGNAL ;
    PORT
      LAYER M5 ;
        RECT  72.816 94.848 72.84 95.04 ;
    END
  END i_d[405]
  PIN i_d[406]
    DIRECTION INPUT ;
    USE SIGNAL ;
    PORT
      LAYER M5 ;
        RECT  72.96 94.848 72.984 95.04 ;
    END
  END i_d[406]
  PIN i_d[407]
    DIRECTION INPUT ;
    USE SIGNAL ;
    PORT
      LAYER M5 ;
        RECT  73.104 94.848 73.128 95.04 ;
    END
  END i_d[407]
  PIN i_d[408]
    DIRECTION INPUT ;
    USE SIGNAL ;
    PORT
      LAYER M5 ;
        RECT  73.392 94.848 73.416 95.04 ;
    END
  END i_d[408]
  PIN i_d[409]
    DIRECTION INPUT ;
    USE SIGNAL ;
    PORT
      LAYER M5 ;
        RECT  73.536 94.848 73.56 95.04 ;
    END
  END i_d[409]
  PIN i_d[40]
    DIRECTION INPUT ;
    USE SIGNAL ;
    PORT
      LAYER M5 ;
        RECT  11.568 94.848 11.592 95.04 ;
    END
  END i_d[40]
  PIN i_d[410]
    DIRECTION INPUT ;
    USE SIGNAL ;
    PORT
      LAYER M5 ;
        RECT  73.68 94.848 73.704 95.04 ;
    END
  END i_d[410]
  PIN i_d[411]
    DIRECTION INPUT ;
    USE SIGNAL ;
    PORT
      LAYER M5 ;
        RECT  73.824 94.848 73.848 95.04 ;
    END
  END i_d[411]
  PIN i_d[412]
    DIRECTION INPUT ;
    USE SIGNAL ;
    PORT
      LAYER M5 ;
        RECT  73.968 94.848 73.992 95.04 ;
    END
  END i_d[412]
  PIN i_d[413]
    DIRECTION INPUT ;
    USE SIGNAL ;
    PORT
      LAYER M5 ;
        RECT  74.112 94.848 74.136 95.04 ;
    END
  END i_d[413]
  PIN i_d[414]
    DIRECTION INPUT ;
    USE SIGNAL ;
    PORT
      LAYER M5 ;
        RECT  74.256 94.848 74.28 95.04 ;
    END
  END i_d[414]
  PIN i_d[415]
    DIRECTION INPUT ;
    USE SIGNAL ;
    PORT
      LAYER M5 ;
        RECT  74.4 94.848 74.424 95.04 ;
    END
  END i_d[415]
  PIN i_d[416]
    DIRECTION INPUT ;
    USE SIGNAL ;
    PORT
      LAYER M5 ;
        RECT  74.544 94.848 74.568 95.04 ;
    END
  END i_d[416]
  PIN i_d[417]
    DIRECTION INPUT ;
    USE SIGNAL ;
    PORT
      LAYER M5 ;
        RECT  74.688 94.848 74.712 95.04 ;
    END
  END i_d[417]
  PIN i_d[418]
    DIRECTION INPUT ;
    USE SIGNAL ;
    PORT
      LAYER M5 ;
        RECT  74.832 94.848 74.856 95.04 ;
    END
  END i_d[418]
  PIN i_d[419]
    DIRECTION INPUT ;
    USE SIGNAL ;
    PORT
      LAYER M5 ;
        RECT  74.976 94.848 75 95.04 ;
    END
  END i_d[419]
  PIN i_d[41]
    DIRECTION INPUT ;
    USE SIGNAL ;
    PORT
      LAYER M5 ;
        RECT  11.712 94.848 11.736 95.04 ;
    END
  END i_d[41]
  PIN i_d[420]
    DIRECTION INPUT ;
    USE SIGNAL ;
    PORT
      LAYER M5 ;
        RECT  75.12 94.848 75.144 95.04 ;
    END
  END i_d[420]
  PIN i_d[421]
    DIRECTION INPUT ;
    USE SIGNAL ;
    PORT
      LAYER M5 ;
        RECT  75.264 94.848 75.288 95.04 ;
    END
  END i_d[421]
  PIN i_d[422]
    DIRECTION INPUT ;
    USE SIGNAL ;
    PORT
      LAYER M5 ;
        RECT  75.408 94.848 75.432 95.04 ;
    END
  END i_d[422]
  PIN i_d[423]
    DIRECTION INPUT ;
    USE SIGNAL ;
    PORT
      LAYER M5 ;
        RECT  75.552 94.848 75.576 95.04 ;
    END
  END i_d[423]
  PIN i_d[424]
    DIRECTION INPUT ;
    USE SIGNAL ;
    PORT
      LAYER M5 ;
        RECT  76.368 94.848 76.392 95.04 ;
    END
  END i_d[424]
  PIN i_d[425]
    DIRECTION INPUT ;
    USE SIGNAL ;
    PORT
      LAYER M5 ;
        RECT  76.512 94.848 76.536 95.04 ;
    END
  END i_d[425]
  PIN i_d[426]
    DIRECTION INPUT ;
    USE SIGNAL ;
    PORT
      LAYER M5 ;
        RECT  76.656 94.848 76.68 95.04 ;
    END
  END i_d[426]
  PIN i_d[427]
    DIRECTION INPUT ;
    USE SIGNAL ;
    PORT
      LAYER M5 ;
        RECT  76.8 94.848 76.824 95.04 ;
    END
  END i_d[427]
  PIN i_d[428]
    DIRECTION INPUT ;
    USE SIGNAL ;
    PORT
      LAYER M5 ;
        RECT  76.944 94.848 76.968 95.04 ;
    END
  END i_d[428]
  PIN i_d[429]
    DIRECTION INPUT ;
    USE SIGNAL ;
    PORT
      LAYER M5 ;
        RECT  77.088 94.848 77.112 95.04 ;
    END
  END i_d[429]
  PIN i_d[42]
    DIRECTION INPUT ;
    USE SIGNAL ;
    PORT
      LAYER M5 ;
        RECT  11.856 94.848 11.88 95.04 ;
    END
  END i_d[42]
  PIN i_d[430]
    DIRECTION INPUT ;
    USE SIGNAL ;
    PORT
      LAYER M5 ;
        RECT  77.232 94.848 77.256 95.04 ;
    END
  END i_d[430]
  PIN i_d[431]
    DIRECTION INPUT ;
    USE SIGNAL ;
    PORT
      LAYER M5 ;
        RECT  77.376 94.848 77.4 95.04 ;
    END
  END i_d[431]
  PIN i_d[432]
    DIRECTION INPUT ;
    USE SIGNAL ;
    PORT
      LAYER M5 ;
        RECT  77.52 94.848 77.544 95.04 ;
    END
  END i_d[432]
  PIN i_d[433]
    DIRECTION INPUT ;
    USE SIGNAL ;
    PORT
      LAYER M5 ;
        RECT  77.664 94.848 77.688 95.04 ;
    END
  END i_d[433]
  PIN i_d[434]
    DIRECTION INPUT ;
    USE SIGNAL ;
    PORT
      LAYER M5 ;
        RECT  77.808 94.848 77.832 95.04 ;
    END
  END i_d[434]
  PIN i_d[435]
    DIRECTION INPUT ;
    USE SIGNAL ;
    PORT
      LAYER M5 ;
        RECT  77.952 94.848 77.976 95.04 ;
    END
  END i_d[435]
  PIN i_d[436]
    DIRECTION INPUT ;
    USE SIGNAL ;
    PORT
      LAYER M5 ;
        RECT  78.096 94.848 78.12 95.04 ;
    END
  END i_d[436]
  PIN i_d[437]
    DIRECTION INPUT ;
    USE SIGNAL ;
    PORT
      LAYER M5 ;
        RECT  78.24 94.848 78.264 95.04 ;
    END
  END i_d[437]
  PIN i_d[438]
    DIRECTION INPUT ;
    USE SIGNAL ;
    PORT
      LAYER M5 ;
        RECT  78.384 94.848 78.408 95.04 ;
    END
  END i_d[438]
  PIN i_d[439]
    DIRECTION INPUT ;
    USE SIGNAL ;
    PORT
      LAYER M5 ;
        RECT  78.528 94.848 78.552 95.04 ;
    END
  END i_d[439]
  PIN i_d[43]
    DIRECTION INPUT ;
    USE SIGNAL ;
    PORT
      LAYER M5 ;
        RECT  12 94.848 12.024 95.04 ;
    END
  END i_d[43]
  PIN i_d[440]
    DIRECTION INPUT ;
    USE SIGNAL ;
    PORT
      LAYER M5 ;
        RECT  78.816 94.848 78.84 95.04 ;
    END
  END i_d[440]
  PIN i_d[441]
    DIRECTION INPUT ;
    USE SIGNAL ;
    PORT
      LAYER M5 ;
        RECT  78.96 94.848 78.984 95.04 ;
    END
  END i_d[441]
  PIN i_d[442]
    DIRECTION INPUT ;
    USE SIGNAL ;
    PORT
      LAYER M5 ;
        RECT  79.104 94.848 79.128 95.04 ;
    END
  END i_d[442]
  PIN i_d[443]
    DIRECTION INPUT ;
    USE SIGNAL ;
    PORT
      LAYER M5 ;
        RECT  79.248 94.848 79.272 95.04 ;
    END
  END i_d[443]
  PIN i_d[444]
    DIRECTION INPUT ;
    USE SIGNAL ;
    PORT
      LAYER M5 ;
        RECT  79.392 94.848 79.416 95.04 ;
    END
  END i_d[444]
  PIN i_d[445]
    DIRECTION INPUT ;
    USE SIGNAL ;
    PORT
      LAYER M5 ;
        RECT  79.536 94.848 79.56 95.04 ;
    END
  END i_d[445]
  PIN i_d[446]
    DIRECTION INPUT ;
    USE SIGNAL ;
    PORT
      LAYER M5 ;
        RECT  79.68 94.848 79.704 95.04 ;
    END
  END i_d[446]
  PIN i_d[447]
    DIRECTION INPUT ;
    USE SIGNAL ;
    PORT
      LAYER M5 ;
        RECT  79.824 94.848 79.848 95.04 ;
    END
  END i_d[447]
  PIN i_d[448]
    DIRECTION INPUT ;
    USE SIGNAL ;
    PORT
      LAYER M5 ;
        RECT  79.968 94.848 79.992 95.04 ;
    END
  END i_d[448]
  PIN i_d[449]
    DIRECTION INPUT ;
    USE SIGNAL ;
    PORT
      LAYER M5 ;
        RECT  80.112 94.848 80.136 95.04 ;
    END
  END i_d[449]
  PIN i_d[44]
    DIRECTION INPUT ;
    USE SIGNAL ;
    PORT
      LAYER M5 ;
        RECT  12.144 94.848 12.168 95.04 ;
    END
  END i_d[44]
  PIN i_d[450]
    DIRECTION INPUT ;
    USE SIGNAL ;
    PORT
      LAYER M5 ;
        RECT  80.256 94.848 80.28 95.04 ;
    END
  END i_d[450]
  PIN i_d[451]
    DIRECTION INPUT ;
    USE SIGNAL ;
    PORT
      LAYER M5 ;
        RECT  80.4 94.848 80.424 95.04 ;
    END
  END i_d[451]
  PIN i_d[452]
    DIRECTION INPUT ;
    USE SIGNAL ;
    PORT
      LAYER M5 ;
        RECT  80.544 94.848 80.568 95.04 ;
    END
  END i_d[452]
  PIN i_d[453]
    DIRECTION INPUT ;
    USE SIGNAL ;
    PORT
      LAYER M5 ;
        RECT  80.688 94.848 80.712 95.04 ;
    END
  END i_d[453]
  PIN i_d[454]
    DIRECTION INPUT ;
    USE SIGNAL ;
    PORT
      LAYER M5 ;
        RECT  80.832 94.848 80.856 95.04 ;
    END
  END i_d[454]
  PIN i_d[455]
    DIRECTION INPUT ;
    USE SIGNAL ;
    PORT
      LAYER M5 ;
        RECT  80.976 94.848 81 95.04 ;
    END
  END i_d[455]
  PIN i_d[456]
    DIRECTION INPUT ;
    USE SIGNAL ;
    PORT
      LAYER M5 ;
        RECT  81.744 94.848 81.768 95.04 ;
    END
  END i_d[456]
  PIN i_d[457]
    DIRECTION INPUT ;
    USE SIGNAL ;
    PORT
      LAYER M5 ;
        RECT  81.888 94.848 81.912 95.04 ;
    END
  END i_d[457]
  PIN i_d[458]
    DIRECTION INPUT ;
    USE SIGNAL ;
    PORT
      LAYER M5 ;
        RECT  82.032 94.848 82.056 95.04 ;
    END
  END i_d[458]
  PIN i_d[459]
    DIRECTION INPUT ;
    USE SIGNAL ;
    PORT
      LAYER M5 ;
        RECT  82.176 94.848 82.2 95.04 ;
    END
  END i_d[459]
  PIN i_d[45]
    DIRECTION INPUT ;
    USE SIGNAL ;
    PORT
      LAYER M5 ;
        RECT  12.288 94.848 12.312 95.04 ;
    END
  END i_d[45]
  PIN i_d[460]
    DIRECTION INPUT ;
    USE SIGNAL ;
    PORT
      LAYER M5 ;
        RECT  82.32 94.848 82.344 95.04 ;
    END
  END i_d[460]
  PIN i_d[461]
    DIRECTION INPUT ;
    USE SIGNAL ;
    PORT
      LAYER M5 ;
        RECT  82.464 94.848 82.488 95.04 ;
    END
  END i_d[461]
  PIN i_d[462]
    DIRECTION INPUT ;
    USE SIGNAL ;
    PORT
      LAYER M5 ;
        RECT  82.608 94.848 82.632 95.04 ;
    END
  END i_d[462]
  PIN i_d[463]
    DIRECTION INPUT ;
    USE SIGNAL ;
    PORT
      LAYER M5 ;
        RECT  82.752 94.848 82.776 95.04 ;
    END
  END i_d[463]
  PIN i_d[464]
    DIRECTION INPUT ;
    USE SIGNAL ;
    PORT
      LAYER M5 ;
        RECT  82.896 94.848 82.92 95.04 ;
    END
  END i_d[464]
  PIN i_d[465]
    DIRECTION INPUT ;
    USE SIGNAL ;
    PORT
      LAYER M5 ;
        RECT  83.04 94.848 83.064 95.04 ;
    END
  END i_d[465]
  PIN i_d[466]
    DIRECTION INPUT ;
    USE SIGNAL ;
    PORT
      LAYER M5 ;
        RECT  83.184 94.848 83.208 95.04 ;
    END
  END i_d[466]
  PIN i_d[467]
    DIRECTION INPUT ;
    USE SIGNAL ;
    PORT
      LAYER M5 ;
        RECT  83.328 94.848 83.352 95.04 ;
    END
  END i_d[467]
  PIN i_d[468]
    DIRECTION INPUT ;
    USE SIGNAL ;
    PORT
      LAYER M5 ;
        RECT  83.472 94.848 83.496 95.04 ;
    END
  END i_d[468]
  PIN i_d[469]
    DIRECTION INPUT ;
    USE SIGNAL ;
    PORT
      LAYER M5 ;
        RECT  83.616 94.848 83.64 95.04 ;
    END
  END i_d[469]
  PIN i_d[46]
    DIRECTION INPUT ;
    USE SIGNAL ;
    PORT
      LAYER M5 ;
        RECT  12.432 94.848 12.456 95.04 ;
    END
  END i_d[46]
  PIN i_d[470]
    DIRECTION INPUT ;
    USE SIGNAL ;
    PORT
      LAYER M5 ;
        RECT  83.76 94.848 83.784 95.04 ;
    END
  END i_d[470]
  PIN i_d[471]
    DIRECTION INPUT ;
    USE SIGNAL ;
    PORT
      LAYER M5 ;
        RECT  83.904 94.848 83.928 95.04 ;
    END
  END i_d[471]
  PIN i_d[472]
    DIRECTION INPUT ;
    USE SIGNAL ;
    PORT
      LAYER M5 ;
        RECT  84.192 94.848 84.216 95.04 ;
    END
  END i_d[472]
  PIN i_d[473]
    DIRECTION INPUT ;
    USE SIGNAL ;
    PORT
      LAYER M5 ;
        RECT  84.336 94.848 84.36 95.04 ;
    END
  END i_d[473]
  PIN i_d[474]
    DIRECTION INPUT ;
    USE SIGNAL ;
    PORT
      LAYER M5 ;
        RECT  84.48 94.848 84.504 95.04 ;
    END
  END i_d[474]
  PIN i_d[475]
    DIRECTION INPUT ;
    USE SIGNAL ;
    PORT
      LAYER M5 ;
        RECT  84.624 94.848 84.648 95.04 ;
    END
  END i_d[475]
  PIN i_d[476]
    DIRECTION INPUT ;
    USE SIGNAL ;
    PORT
      LAYER M5 ;
        RECT  84.768 94.848 84.792 95.04 ;
    END
  END i_d[476]
  PIN i_d[477]
    DIRECTION INPUT ;
    USE SIGNAL ;
    PORT
      LAYER M5 ;
        RECT  84.912 94.848 84.936 95.04 ;
    END
  END i_d[477]
  PIN i_d[478]
    DIRECTION INPUT ;
    USE SIGNAL ;
    PORT
      LAYER M5 ;
        RECT  85.056 94.848 85.08 95.04 ;
    END
  END i_d[478]
  PIN i_d[479]
    DIRECTION INPUT ;
    USE SIGNAL ;
    PORT
      LAYER M5 ;
        RECT  85.2 94.848 85.224 95.04 ;
    END
  END i_d[479]
  PIN i_d[47]
    DIRECTION INPUT ;
    USE SIGNAL ;
    PORT
      LAYER M5 ;
        RECT  12.576 94.848 12.6 95.04 ;
    END
  END i_d[47]
  PIN i_d[480]
    DIRECTION INPUT ;
    USE SIGNAL ;
    PORT
      LAYER M5 ;
        RECT  85.344 94.848 85.368 95.04 ;
    END
  END i_d[480]
  PIN i_d[481]
    DIRECTION INPUT ;
    USE SIGNAL ;
    PORT
      LAYER M5 ;
        RECT  85.488 94.848 85.512 95.04 ;
    END
  END i_d[481]
  PIN i_d[482]
    DIRECTION INPUT ;
    USE SIGNAL ;
    PORT
      LAYER M5 ;
        RECT  85.632 94.848 85.656 95.04 ;
    END
  END i_d[482]
  PIN i_d[483]
    DIRECTION INPUT ;
    USE SIGNAL ;
    PORT
      LAYER M5 ;
        RECT  85.776 94.848 85.8 95.04 ;
    END
  END i_d[483]
  PIN i_d[484]
    DIRECTION INPUT ;
    USE SIGNAL ;
    PORT
      LAYER M5 ;
        RECT  85.92 94.848 85.944 95.04 ;
    END
  END i_d[484]
  PIN i_d[485]
    DIRECTION INPUT ;
    USE SIGNAL ;
    PORT
      LAYER M5 ;
        RECT  86.064 94.848 86.088 95.04 ;
    END
  END i_d[485]
  PIN i_d[486]
    DIRECTION INPUT ;
    USE SIGNAL ;
    PORT
      LAYER M5 ;
        RECT  86.208 94.848 86.232 95.04 ;
    END
  END i_d[486]
  PIN i_d[487]
    DIRECTION INPUT ;
    USE SIGNAL ;
    PORT
      LAYER M5 ;
        RECT  86.352 94.848 86.376 95.04 ;
    END
  END i_d[487]
  PIN i_d[488]
    DIRECTION INPUT ;
    USE SIGNAL ;
    PORT
      LAYER M5 ;
        RECT  87.168 94.848 87.192 95.04 ;
    END
  END i_d[488]
  PIN i_d[489]
    DIRECTION INPUT ;
    USE SIGNAL ;
    PORT
      LAYER M5 ;
        RECT  87.312 94.848 87.336 95.04 ;
    END
  END i_d[489]
  PIN i_d[48]
    DIRECTION INPUT ;
    USE SIGNAL ;
    PORT
      LAYER M5 ;
        RECT  12.72 94.848 12.744 95.04 ;
    END
  END i_d[48]
  PIN i_d[490]
    DIRECTION INPUT ;
    USE SIGNAL ;
    PORT
      LAYER M5 ;
        RECT  87.456 94.848 87.48 95.04 ;
    END
  END i_d[490]
  PIN i_d[491]
    DIRECTION INPUT ;
    USE SIGNAL ;
    PORT
      LAYER M5 ;
        RECT  87.6 94.848 87.624 95.04 ;
    END
  END i_d[491]
  PIN i_d[492]
    DIRECTION INPUT ;
    USE SIGNAL ;
    PORT
      LAYER M5 ;
        RECT  87.744 94.848 87.768 95.04 ;
    END
  END i_d[492]
  PIN i_d[493]
    DIRECTION INPUT ;
    USE SIGNAL ;
    PORT
      LAYER M5 ;
        RECT  87.888 94.848 87.912 95.04 ;
    END
  END i_d[493]
  PIN i_d[494]
    DIRECTION INPUT ;
    USE SIGNAL ;
    PORT
      LAYER M5 ;
        RECT  88.032 94.848 88.056 95.04 ;
    END
  END i_d[494]
  PIN i_d[495]
    DIRECTION INPUT ;
    USE SIGNAL ;
    PORT
      LAYER M5 ;
        RECT  88.176 94.848 88.2 95.04 ;
    END
  END i_d[495]
  PIN i_d[496]
    DIRECTION INPUT ;
    USE SIGNAL ;
    PORT
      LAYER M5 ;
        RECT  88.32 94.848 88.344 95.04 ;
    END
  END i_d[496]
  PIN i_d[497]
    DIRECTION INPUT ;
    USE SIGNAL ;
    PORT
      LAYER M5 ;
        RECT  88.464 94.848 88.488 95.04 ;
    END
  END i_d[497]
  PIN i_d[498]
    DIRECTION INPUT ;
    USE SIGNAL ;
    PORT
      LAYER M5 ;
        RECT  88.608 94.848 88.632 95.04 ;
    END
  END i_d[498]
  PIN i_d[499]
    DIRECTION INPUT ;
    USE SIGNAL ;
    PORT
      LAYER M5 ;
        RECT  88.752 94.848 88.776 95.04 ;
    END
  END i_d[499]
  PIN i_d[49]
    DIRECTION INPUT ;
    USE SIGNAL ;
    PORT
      LAYER M5 ;
        RECT  12.864 94.848 12.888 95.04 ;
    END
  END i_d[49]
  PIN i_d[4]
    DIRECTION INPUT ;
    USE SIGNAL ;
    PORT
      LAYER M5 ;
        RECT  4.896 94.848 4.92 95.04 ;
    END
  END i_d[4]
  PIN i_d[500]
    DIRECTION INPUT ;
    USE SIGNAL ;
    PORT
      LAYER M5 ;
        RECT  88.896 94.848 88.92 95.04 ;
    END
  END i_d[500]
  PIN i_d[501]
    DIRECTION INPUT ;
    USE SIGNAL ;
    PORT
      LAYER M5 ;
        RECT  89.04 94.848 89.064 95.04 ;
    END
  END i_d[501]
  PIN i_d[502]
    DIRECTION INPUT ;
    USE SIGNAL ;
    PORT
      LAYER M5 ;
        RECT  89.184 94.848 89.208 95.04 ;
    END
  END i_d[502]
  PIN i_d[503]
    DIRECTION INPUT ;
    USE SIGNAL ;
    PORT
      LAYER M5 ;
        RECT  89.328 94.848 89.352 95.04 ;
    END
  END i_d[503]
  PIN i_d[504]
    DIRECTION INPUT ;
    USE SIGNAL ;
    PORT
      LAYER M5 ;
        RECT  89.616 94.848 89.64 95.04 ;
    END
  END i_d[504]
  PIN i_d[505]
    DIRECTION INPUT ;
    USE SIGNAL ;
    PORT
      LAYER M5 ;
        RECT  89.76 94.848 89.784 95.04 ;
    END
  END i_d[505]
  PIN i_d[506]
    DIRECTION INPUT ;
    USE SIGNAL ;
    PORT
      LAYER M5 ;
        RECT  89.904 94.848 89.928 95.04 ;
    END
  END i_d[506]
  PIN i_d[507]
    DIRECTION INPUT ;
    USE SIGNAL ;
    PORT
      LAYER M5 ;
        RECT  90.048 94.848 90.072 95.04 ;
    END
  END i_d[507]
  PIN i_d[508]
    DIRECTION INPUT ;
    USE SIGNAL ;
    PORT
      LAYER M5 ;
        RECT  90.192 94.848 90.216 95.04 ;
    END
  END i_d[508]
  PIN i_d[509]
    DIRECTION INPUT ;
    USE SIGNAL ;
    PORT
      LAYER M5 ;
        RECT  90.336 94.848 90.36 95.04 ;
    END
  END i_d[509]
  PIN i_d[50]
    DIRECTION INPUT ;
    USE SIGNAL ;
    PORT
      LAYER M5 ;
        RECT  13.008 94.848 13.032 95.04 ;
    END
  END i_d[50]
  PIN i_d[510]
    DIRECTION INPUT ;
    USE SIGNAL ;
    PORT
      LAYER M5 ;
        RECT  90.48 94.848 90.504 95.04 ;
    END
  END i_d[510]
  PIN i_d[511]
    DIRECTION INPUT ;
    USE SIGNAL ;
    PORT
      LAYER M5 ;
        RECT  90.624 94.848 90.648 95.04 ;
    END
  END i_d[511]
  PIN i_d[51]
    DIRECTION INPUT ;
    USE SIGNAL ;
    PORT
      LAYER M5 ;
        RECT  13.152 94.848 13.176 95.04 ;
    END
  END i_d[51]
  PIN i_d[52]
    DIRECTION INPUT ;
    USE SIGNAL ;
    PORT
      LAYER M5 ;
        RECT  13.296 94.848 13.32 95.04 ;
    END
  END i_d[52]
  PIN i_d[53]
    DIRECTION INPUT ;
    USE SIGNAL ;
    PORT
      LAYER M5 ;
        RECT  13.44 94.848 13.464 95.04 ;
    END
  END i_d[53]
  PIN i_d[54]
    DIRECTION INPUT ;
    USE SIGNAL ;
    PORT
      LAYER M5 ;
        RECT  13.584 94.848 13.608 95.04 ;
    END
  END i_d[54]
  PIN i_d[55]
    DIRECTION INPUT ;
    USE SIGNAL ;
    PORT
      LAYER M5 ;
        RECT  13.728 94.848 13.752 95.04 ;
    END
  END i_d[55]
  PIN i_d[56]
    DIRECTION INPUT ;
    USE SIGNAL ;
    PORT
      LAYER M5 ;
        RECT  14.016 94.848 14.04 95.04 ;
    END
  END i_d[56]
  PIN i_d[57]
    DIRECTION INPUT ;
    USE SIGNAL ;
    PORT
      LAYER M5 ;
        RECT  14.16 94.848 14.184 95.04 ;
    END
  END i_d[57]
  PIN i_d[58]
    DIRECTION INPUT ;
    USE SIGNAL ;
    PORT
      LAYER M5 ;
        RECT  14.304 94.848 14.328 95.04 ;
    END
  END i_d[58]
  PIN i_d[59]
    DIRECTION INPUT ;
    USE SIGNAL ;
    PORT
      LAYER M5 ;
        RECT  14.448 94.848 14.472 95.04 ;
    END
  END i_d[59]
  PIN i_d[5]
    DIRECTION INPUT ;
    USE SIGNAL ;
    PORT
      LAYER M5 ;
        RECT  5.04 94.848 5.064 95.04 ;
    END
  END i_d[5]
  PIN i_d[60]
    DIRECTION INPUT ;
    USE SIGNAL ;
    PORT
      LAYER M5 ;
        RECT  14.592 94.848 14.616 95.04 ;
    END
  END i_d[60]
  PIN i_d[61]
    DIRECTION INPUT ;
    USE SIGNAL ;
    PORT
      LAYER M5 ;
        RECT  14.736 94.848 14.76 95.04 ;
    END
  END i_d[61]
  PIN i_d[62]
    DIRECTION INPUT ;
    USE SIGNAL ;
    PORT
      LAYER M5 ;
        RECT  14.88 94.848 14.904 95.04 ;
    END
  END i_d[62]
  PIN i_d[63]
    DIRECTION INPUT ;
    USE SIGNAL ;
    PORT
      LAYER M5 ;
        RECT  15.024 94.848 15.048 95.04 ;
    END
  END i_d[63]
  PIN i_d[64]
    DIRECTION INPUT ;
    USE SIGNAL ;
    PORT
      LAYER M5 ;
        RECT  15.168 94.848 15.192 95.04 ;
    END
  END i_d[64]
  PIN i_d[65]
    DIRECTION INPUT ;
    USE SIGNAL ;
    PORT
      LAYER M5 ;
        RECT  15.312 94.848 15.336 95.04 ;
    END
  END i_d[65]
  PIN i_d[66]
    DIRECTION INPUT ;
    USE SIGNAL ;
    PORT
      LAYER M5 ;
        RECT  15.456 94.848 15.48 95.04 ;
    END
  END i_d[66]
  PIN i_d[67]
    DIRECTION INPUT ;
    USE SIGNAL ;
    PORT
      LAYER M5 ;
        RECT  15.6 94.848 15.624 95.04 ;
    END
  END i_d[67]
  PIN i_d[68]
    DIRECTION INPUT ;
    USE SIGNAL ;
    PORT
      LAYER M5 ;
        RECT  15.744 94.848 15.768 95.04 ;
    END
  END i_d[68]
  PIN i_d[69]
    DIRECTION INPUT ;
    USE SIGNAL ;
    PORT
      LAYER M5 ;
        RECT  15.888 94.848 15.912 95.04 ;
    END
  END i_d[69]
  PIN i_d[6]
    DIRECTION INPUT ;
    USE SIGNAL ;
    PORT
      LAYER M5 ;
        RECT  5.184 94.848 5.208 95.04 ;
    END
  END i_d[6]
  PIN i_d[70]
    DIRECTION INPUT ;
    USE SIGNAL ;
    PORT
      LAYER M5 ;
        RECT  16.032 94.848 16.056 95.04 ;
    END
  END i_d[70]
  PIN i_d[71]
    DIRECTION INPUT ;
    USE SIGNAL ;
    PORT
      LAYER M5 ;
        RECT  16.176 94.848 16.2 95.04 ;
    END
  END i_d[71]
  PIN i_d[72]
    DIRECTION INPUT ;
    USE SIGNAL ;
    PORT
      LAYER M5 ;
        RECT  16.944 94.848 16.968 95.04 ;
    END
  END i_d[72]
  PIN i_d[73]
    DIRECTION INPUT ;
    USE SIGNAL ;
    PORT
      LAYER M5 ;
        RECT  17.088 94.848 17.112 95.04 ;
    END
  END i_d[73]
  PIN i_d[74]
    DIRECTION INPUT ;
    USE SIGNAL ;
    PORT
      LAYER M5 ;
        RECT  17.232 94.848 17.256 95.04 ;
    END
  END i_d[74]
  PIN i_d[75]
    DIRECTION INPUT ;
    USE SIGNAL ;
    PORT
      LAYER M5 ;
        RECT  17.376 94.848 17.4 95.04 ;
    END
  END i_d[75]
  PIN i_d[76]
    DIRECTION INPUT ;
    USE SIGNAL ;
    PORT
      LAYER M5 ;
        RECT  17.52 94.848 17.544 95.04 ;
    END
  END i_d[76]
  PIN i_d[77]
    DIRECTION INPUT ;
    USE SIGNAL ;
    PORT
      LAYER M5 ;
        RECT  17.664 94.848 17.688 95.04 ;
    END
  END i_d[77]
  PIN i_d[78]
    DIRECTION INPUT ;
    USE SIGNAL ;
    PORT
      LAYER M5 ;
        RECT  17.808 94.848 17.832 95.04 ;
    END
  END i_d[78]
  PIN i_d[79]
    DIRECTION INPUT ;
    USE SIGNAL ;
    PORT
      LAYER M5 ;
        RECT  17.952 94.848 17.976 95.04 ;
    END
  END i_d[79]
  PIN i_d[7]
    DIRECTION INPUT ;
    USE SIGNAL ;
    PORT
      LAYER M5 ;
        RECT  5.328 94.848 5.352 95.04 ;
    END
  END i_d[7]
  PIN i_d[80]
    DIRECTION INPUT ;
    USE SIGNAL ;
    PORT
      LAYER M5 ;
        RECT  18.096 94.848 18.12 95.04 ;
    END
  END i_d[80]
  PIN i_d[81]
    DIRECTION INPUT ;
    USE SIGNAL ;
    PORT
      LAYER M5 ;
        RECT  18.24 94.848 18.264 95.04 ;
    END
  END i_d[81]
  PIN i_d[82]
    DIRECTION INPUT ;
    USE SIGNAL ;
    PORT
      LAYER M5 ;
        RECT  18.384 94.848 18.408 95.04 ;
    END
  END i_d[82]
  PIN i_d[83]
    DIRECTION INPUT ;
    USE SIGNAL ;
    PORT
      LAYER M5 ;
        RECT  18.528 94.848 18.552 95.04 ;
    END
  END i_d[83]
  PIN i_d[84]
    DIRECTION INPUT ;
    USE SIGNAL ;
    PORT
      LAYER M5 ;
        RECT  18.672 94.848 18.696 95.04 ;
    END
  END i_d[84]
  PIN i_d[85]
    DIRECTION INPUT ;
    USE SIGNAL ;
    PORT
      LAYER M5 ;
        RECT  18.816 94.848 18.84 95.04 ;
    END
  END i_d[85]
  PIN i_d[86]
    DIRECTION INPUT ;
    USE SIGNAL ;
    PORT
      LAYER M5 ;
        RECT  18.96 94.848 18.984 95.04 ;
    END
  END i_d[86]
  PIN i_d[87]
    DIRECTION INPUT ;
    USE SIGNAL ;
    PORT
      LAYER M5 ;
        RECT  19.104 94.848 19.128 95.04 ;
    END
  END i_d[87]
  PIN i_d[88]
    DIRECTION INPUT ;
    USE SIGNAL ;
    PORT
      LAYER M5 ;
        RECT  19.392 94.848 19.416 95.04 ;
    END
  END i_d[88]
  PIN i_d[89]
    DIRECTION INPUT ;
    USE SIGNAL ;
    PORT
      LAYER M5 ;
        RECT  19.536 94.848 19.56 95.04 ;
    END
  END i_d[89]
  PIN i_d[8]
    DIRECTION INPUT ;
    USE SIGNAL ;
    PORT
      LAYER M5 ;
        RECT  6.144 94.848 6.168 95.04 ;
    END
  END i_d[8]
  PIN i_d[90]
    DIRECTION INPUT ;
    USE SIGNAL ;
    PORT
      LAYER M5 ;
        RECT  19.68 94.848 19.704 95.04 ;
    END
  END i_d[90]
  PIN i_d[91]
    DIRECTION INPUT ;
    USE SIGNAL ;
    PORT
      LAYER M5 ;
        RECT  19.824 94.848 19.848 95.04 ;
    END
  END i_d[91]
  PIN i_d[92]
    DIRECTION INPUT ;
    USE SIGNAL ;
    PORT
      LAYER M5 ;
        RECT  19.968 94.848 19.992 95.04 ;
    END
  END i_d[92]
  PIN i_d[93]
    DIRECTION INPUT ;
    USE SIGNAL ;
    PORT
      LAYER M5 ;
        RECT  20.112 94.848 20.136 95.04 ;
    END
  END i_d[93]
  PIN i_d[94]
    DIRECTION INPUT ;
    USE SIGNAL ;
    PORT
      LAYER M5 ;
        RECT  20.256 94.848 20.28 95.04 ;
    END
  END i_d[94]
  PIN i_d[95]
    DIRECTION INPUT ;
    USE SIGNAL ;
    PORT
      LAYER M5 ;
        RECT  20.4 94.848 20.424 95.04 ;
    END
  END i_d[95]
  PIN i_d[96]
    DIRECTION INPUT ;
    USE SIGNAL ;
    PORT
      LAYER M5 ;
        RECT  20.544 94.848 20.568 95.04 ;
    END
  END i_d[96]
  PIN i_d[97]
    DIRECTION INPUT ;
    USE SIGNAL ;
    PORT
      LAYER M5 ;
        RECT  20.688 94.848 20.712 95.04 ;
    END
  END i_d[97]
  PIN i_d[98]
    DIRECTION INPUT ;
    USE SIGNAL ;
    PORT
      LAYER M5 ;
        RECT  20.832 94.848 20.856 95.04 ;
    END
  END i_d[98]
  PIN i_d[99]
    DIRECTION INPUT ;
    USE SIGNAL ;
    PORT
      LAYER M5 ;
        RECT  20.976 94.848 21 95.04 ;
    END
  END i_d[99]
  PIN i_d[9]
    DIRECTION INPUT ;
    USE SIGNAL ;
    PORT
      LAYER M5 ;
        RECT  6.288 94.848 6.312 95.04 ;
    END
  END i_d[9]
  PIN i_v
    DIRECTION INPUT ;
    USE SIGNAL ;
    PORT
      LAYER M4 ;
        RECT  0 88.704 0.192 88.728 ;
    END
    PORT
      LAYER M4 ;
        RECT  0.156 88.704 2.408 88.728 ;
    END
  END i_v
  PIN larm_base[0]
    DIRECTION INPUT ;
    USE SIGNAL ;
    PORT
      LAYER M4 ;
        RECT  0 33.696 0.192 33.72 ;
    END
    PORT
      LAYER M4 ;
        RECT  0.156 33.696 0.569 33.72 ;
    END
  END larm_base[0]
  PIN larm_base[10]
    DIRECTION INPUT ;
    USE SIGNAL ;
    PORT
      LAYER M4 ;
        RECT  0 73.008 0.192 73.032 ;
    END
    PORT
      LAYER M4 ;
        RECT  0.156 73.008 2.408 73.032 ;
    END
  END larm_base[10]
  PIN larm_base[11]
    DIRECTION INPUT ;
    USE SIGNAL ;
    PORT
      LAYER M4 ;
        RECT  0 76.896 0.192 76.92 ;
    END
    PORT
      LAYER M4 ;
        RECT  0.156 76.896 2.408 76.92 ;
    END
  END larm_base[11]
  PIN larm_base[12]
    DIRECTION INPUT ;
    USE SIGNAL ;
    PORT
      LAYER M4 ;
        RECT  0 80.784 0.192 80.808 ;
    END
    PORT
      LAYER M4 ;
        RECT  0.156 80.784 2.408 80.808 ;
    END
  END larm_base[12]
  PIN larm_base[13]
    DIRECTION INPUT ;
    USE SIGNAL ;
    PORT
      LAYER M4 ;
        RECT  0 84.816 0.192 84.84 ;
    END
    PORT
      LAYER M4 ;
        RECT  0.156 84.816 2.408 84.84 ;
    END
  END larm_base[13]
  PIN larm_base[1]
    DIRECTION INPUT ;
    USE SIGNAL ;
    PORT
      LAYER M4 ;
        RECT  0 37.584 0.192 37.608 ;
    END
    PORT
      LAYER M4 ;
        RECT  0.156 37.584 2.408 37.608 ;
    END
  END larm_base[1]
  PIN larm_base[2]
    DIRECTION INPUT ;
    USE SIGNAL ;
    PORT
      LAYER M4 ;
        RECT  0 41.616 0.192 41.64 ;
    END
    PORT
      LAYER M4 ;
        RECT  0.156 41.616 2.408 41.64 ;
    END
  END larm_base[2]
  PIN larm_base[3]
    DIRECTION INPUT ;
    USE SIGNAL ;
    PORT
      LAYER M4 ;
        RECT  0 45.504 0.192 45.528 ;
    END
    PORT
      LAYER M4 ;
        RECT  0.156 45.504 2.408 45.528 ;
    END
  END larm_base[3]
  PIN larm_base[4]
    DIRECTION INPUT ;
    USE SIGNAL ;
    PORT
      LAYER M4 ;
        RECT  0 49.392 0.192 49.416 ;
    END
    PORT
      LAYER M4 ;
        RECT  0.156 49.392 2.408 49.416 ;
    END
  END larm_base[4]
  PIN larm_base[5]
    DIRECTION INPUT ;
    USE SIGNAL ;
    PORT
      LAYER M4 ;
        RECT  0 53.28 0.192 53.304 ;
    END
    PORT
      LAYER M4 ;
        RECT  0.156 53.28 2.408 53.304 ;
    END
  END larm_base[5]
  PIN larm_base[6]
    DIRECTION INPUT ;
    USE SIGNAL ;
    PORT
      LAYER M4 ;
        RECT  0 57.312 0.192 57.336 ;
    END
    PORT
      LAYER M4 ;
        RECT  0.156 57.312 2.408 57.336 ;
    END
  END larm_base[6]
  PIN larm_base[7]
    DIRECTION INPUT ;
    USE SIGNAL ;
    PORT
      LAYER M4 ;
        RECT  0 61.2 0.192 61.224 ;
    END
    PORT
      LAYER M4 ;
        RECT  0.156 61.2 2.408 61.224 ;
    END
  END larm_base[7]
  PIN larm_base[8]
    DIRECTION INPUT ;
    USE SIGNAL ;
    PORT
      LAYER M4 ;
        RECT  0 65.088 0.192 65.112 ;
    END
    PORT
      LAYER M4 ;
        RECT  0.156 65.088 2.408 65.112 ;
    END
  END larm_base[8]
  PIN larm_base[9]
    DIRECTION INPUT ;
    USE SIGNAL ;
    PORT
      LAYER M4 ;
        RECT  0 69.12 0.192 69.144 ;
    END
    PORT
      LAYER M4 ;
        RECT  0.156 69.12 2.408 69.144 ;
    END
  END larm_base[9]
  PIN larm_g[0]
    DIRECTION INPUT ;
    USE SIGNAL ;
    PORT
      LAYER M4 ;
        RECT  0 18 0.192 18.024 ;
    END
    PORT
      LAYER M4 ;
        RECT  0.156 18 2.408 18.024 ;
    END
  END larm_g[0]
  PIN larm_g[1]
    DIRECTION INPUT ;
    USE SIGNAL ;
    PORT
      LAYER M4 ;
        RECT  0 21.888 0.192 21.912 ;
    END
    PORT
      LAYER M4 ;
        RECT  0.156 21.888 2.408 21.912 ;
    END
  END larm_g[1]
  PIN larm_g[2]
    DIRECTION INPUT ;
    USE SIGNAL ;
    PORT
      LAYER M4 ;
        RECT  0 25.92 0.192 25.944 ;
    END
    PORT
      LAYER M4 ;
        RECT  0.156 25.92 2.408 25.944 ;
    END
  END larm_g[2]
  PIN larm_g[3]
    DIRECTION INPUT ;
    USE SIGNAL ;
    PORT
      LAYER M4 ;
        RECT  0 29.808 0.192 29.832 ;
    END
    PORT
      LAYER M4 ;
        RECT  0.156 29.808 2.408 29.832 ;
    END
  END larm_g[3]
  PIN larm_v
    DIRECTION INPUT ;
    USE SIGNAL ;
    PORT
      LAYER M4 ;
        RECT  0 14.112 0.192 14.136 ;
    END
    PORT
      LAYER M4 ;
        RECT  0.156 14.112 2.408 14.136 ;
    END
  END larm_v
  PIN o_d[0]
    DIRECTION OUTPUT ;
    USE SIGNAL ;
    PORT
      LAYER M5 ;
        RECT  4.32 0 4.344 0.192 ;
    END
  END o_d[0]
  PIN o_d[100]
    DIRECTION OUTPUT ;
    USE SIGNAL ;
    PORT
      LAYER M5 ;
        RECT  20.688 0 20.712 0.192 ;
    END
  END o_d[100]
  PIN o_d[101]
    DIRECTION OUTPUT ;
    USE SIGNAL ;
    PORT
      LAYER M5 ;
        RECT  20.832 0 20.856 0.192 ;
    END
  END o_d[101]
  PIN o_d[102]
    DIRECTION OUTPUT ;
    USE SIGNAL ;
    PORT
      LAYER M5 ;
        RECT  20.976 0 21 0.192 ;
    END
  END o_d[102]
  PIN o_d[103]
    DIRECTION OUTPUT ;
    USE SIGNAL ;
    PORT
      LAYER M5 ;
        RECT  21.12 0 21.144 0.192 ;
    END
  END o_d[103]
  PIN o_d[104]
    DIRECTION OUTPUT ;
    USE SIGNAL ;
    PORT
      LAYER M5 ;
        RECT  21.264 0 21.288 0.192 ;
    END
  END o_d[104]
  PIN o_d[105]
    DIRECTION OUTPUT ;
    USE SIGNAL ;
    PORT
      LAYER M5 ;
        RECT  21.408 0 21.432 0.192 ;
    END
  END o_d[105]
  PIN o_d[106]
    DIRECTION OUTPUT ;
    USE SIGNAL ;
    PORT
      LAYER M5 ;
        RECT  21.552 0 21.576 0.192 ;
    END
  END o_d[106]
  PIN o_d[107]
    DIRECTION OUTPUT ;
    USE SIGNAL ;
    PORT
      LAYER M5 ;
        RECT  21.696 0 21.72 0.192 ;
    END
  END o_d[107]
  PIN o_d[108]
    DIRECTION OUTPUT ;
    USE SIGNAL ;
    PORT
      LAYER M5 ;
        RECT  22.512 0 22.536 0.192 ;
    END
  END o_d[108]
  PIN o_d[109]
    DIRECTION OUTPUT ;
    USE SIGNAL ;
    PORT
      LAYER M5 ;
        RECT  22.656 0 22.68 0.192 ;
    END
  END o_d[109]
  PIN o_d[10]
    DIRECTION OUTPUT ;
    USE SIGNAL ;
    PORT
      LAYER M5 ;
        RECT  6.288 0 6.312 0.192 ;
    END
  END o_d[10]
  PIN o_d[110]
    DIRECTION OUTPUT ;
    USE SIGNAL ;
    PORT
      LAYER M5 ;
        RECT  22.8 0 22.824 0.192 ;
    END
  END o_d[110]
  PIN o_d[111]
    DIRECTION OUTPUT ;
    USE SIGNAL ;
    PORT
      LAYER M5 ;
        RECT  22.944 0 22.968 0.192 ;
    END
  END o_d[111]
  PIN o_d[112]
    DIRECTION OUTPUT ;
    USE SIGNAL ;
    PORT
      LAYER M5 ;
        RECT  23.088 0 23.112 0.192 ;
    END
  END o_d[112]
  PIN o_d[113]
    DIRECTION OUTPUT ;
    USE SIGNAL ;
    PORT
      LAYER M5 ;
        RECT  23.232 0 23.256 0.192 ;
    END
  END o_d[113]
  PIN o_d[114]
    DIRECTION OUTPUT ;
    USE SIGNAL ;
    PORT
      LAYER M5 ;
        RECT  23.376 0 23.4 0.192 ;
    END
  END o_d[114]
  PIN o_d[115]
    DIRECTION OUTPUT ;
    USE SIGNAL ;
    PORT
      LAYER M5 ;
        RECT  23.52 0 23.544 0.192 ;
    END
  END o_d[115]
  PIN o_d[116]
    DIRECTION OUTPUT ;
    USE SIGNAL ;
    PORT
      LAYER M5 ;
        RECT  23.664 0 23.688 0.192 ;
    END
  END o_d[116]
  PIN o_d[117]
    DIRECTION OUTPUT ;
    USE SIGNAL ;
    PORT
      LAYER M5 ;
        RECT  23.808 0 23.832 0.192 ;
    END
  END o_d[117]
  PIN o_d[118]
    DIRECTION OUTPUT ;
    USE SIGNAL ;
    PORT
      LAYER M5 ;
        RECT  23.952 0 23.976 0.192 ;
    END
  END o_d[118]
  PIN o_d[119]
    DIRECTION OUTPUT ;
    USE SIGNAL ;
    PORT
      LAYER M5 ;
        RECT  24.096 0 24.12 0.192 ;
    END
  END o_d[119]
  PIN o_d[11]
    DIRECTION OUTPUT ;
    USE SIGNAL ;
    PORT
      LAYER M5 ;
        RECT  6.432 0 6.456 0.192 ;
    END
  END o_d[11]
  PIN o_d[120]
    DIRECTION OUTPUT ;
    USE SIGNAL ;
    PORT
      LAYER M5 ;
        RECT  24.24 0 24.264 0.192 ;
    END
  END o_d[120]
  PIN o_d[121]
    DIRECTION OUTPUT ;
    USE SIGNAL ;
    PORT
      LAYER M5 ;
        RECT  24.384 0 24.408 0.192 ;
    END
  END o_d[121]
  PIN o_d[122]
    DIRECTION OUTPUT ;
    USE SIGNAL ;
    PORT
      LAYER M5 ;
        RECT  24.528 0 24.552 0.192 ;
    END
  END o_d[122]
  PIN o_d[123]
    DIRECTION OUTPUT ;
    USE SIGNAL ;
    PORT
      LAYER M5 ;
        RECT  24.672 0 24.696 0.192 ;
    END
  END o_d[123]
  PIN o_d[124]
    DIRECTION OUTPUT ;
    USE SIGNAL ;
    PORT
      LAYER M5 ;
        RECT  24.816 0 24.84 0.192 ;
    END
  END o_d[124]
  PIN o_d[125]
    DIRECTION OUTPUT ;
    USE SIGNAL ;
    PORT
      LAYER M5 ;
        RECT  24.96 0 24.984 0.192 ;
    END
  END o_d[125]
  PIN o_d[126]
    DIRECTION OUTPUT ;
    USE SIGNAL ;
    PORT
      LAYER M5 ;
        RECT  25.104 0 25.128 0.192 ;
    END
  END o_d[126]
  PIN o_d[127]
    DIRECTION OUTPUT ;
    USE SIGNAL ;
    PORT
      LAYER M5 ;
        RECT  25.248 0 25.272 0.192 ;
    END
  END o_d[127]
  PIN o_d[128]
    DIRECTION OUTPUT ;
    USE SIGNAL ;
    PORT
      LAYER M5 ;
        RECT  25.392 0 25.416 0.192 ;
    END
  END o_d[128]
  PIN o_d[129]
    DIRECTION OUTPUT ;
    USE SIGNAL ;
    PORT
      LAYER M5 ;
        RECT  25.536 0 25.56 0.192 ;
    END
  END o_d[129]
  PIN o_d[12]
    DIRECTION OUTPUT ;
    USE SIGNAL ;
    PORT
      LAYER M5 ;
        RECT  6.576 0 6.6 0.192 ;
    END
  END o_d[12]
  PIN o_d[130]
    DIRECTION OUTPUT ;
    USE SIGNAL ;
    PORT
      LAYER M5 ;
        RECT  25.68 0 25.704 0.192 ;
    END
  END o_d[130]
  PIN o_d[131]
    DIRECTION OUTPUT ;
    USE SIGNAL ;
    PORT
      LAYER M5 ;
        RECT  25.824 0 25.848 0.192 ;
    END
  END o_d[131]
  PIN o_d[132]
    DIRECTION OUTPUT ;
    USE SIGNAL ;
    PORT
      LAYER M5 ;
        RECT  25.968 0 25.992 0.192 ;
    END
  END o_d[132]
  PIN o_d[133]
    DIRECTION OUTPUT ;
    USE SIGNAL ;
    PORT
      LAYER M5 ;
        RECT  26.112 0 26.136 0.192 ;
    END
  END o_d[133]
  PIN o_d[134]
    DIRECTION OUTPUT ;
    USE SIGNAL ;
    PORT
      LAYER M5 ;
        RECT  26.256 0 26.28 0.192 ;
    END
  END o_d[134]
  PIN o_d[135]
    DIRECTION OUTPUT ;
    USE SIGNAL ;
    PORT
      LAYER M5 ;
        RECT  26.4 0 26.424 0.192 ;
    END
  END o_d[135]
  PIN o_d[136]
    DIRECTION OUTPUT ;
    USE SIGNAL ;
    PORT
      LAYER M5 ;
        RECT  26.544 0 26.568 0.192 ;
    END
  END o_d[136]
  PIN o_d[137]
    DIRECTION OUTPUT ;
    USE SIGNAL ;
    PORT
      LAYER M5 ;
        RECT  26.688 0 26.712 0.192 ;
    END
  END o_d[137]
  PIN o_d[138]
    DIRECTION OUTPUT ;
    USE SIGNAL ;
    PORT
      LAYER M5 ;
        RECT  26.832 0 26.856 0.192 ;
    END
  END o_d[138]
  PIN o_d[139]
    DIRECTION OUTPUT ;
    USE SIGNAL ;
    PORT
      LAYER M5 ;
        RECT  27.12 0 27.144 0.192 ;
    END
  END o_d[139]
  PIN o_d[13]
    DIRECTION OUTPUT ;
    USE SIGNAL ;
    PORT
      LAYER M5 ;
        RECT  6.72 0 6.744 0.192 ;
    END
  END o_d[13]
  PIN o_d[140]
    DIRECTION OUTPUT ;
    USE SIGNAL ;
    PORT
      LAYER M5 ;
        RECT  27.744 0 27.768 0.192 ;
    END
  END o_d[140]
  PIN o_d[141]
    DIRECTION OUTPUT ;
    USE SIGNAL ;
    PORT
      LAYER M5 ;
        RECT  27.888 0 27.912 0.192 ;
    END
  END o_d[141]
  PIN o_d[142]
    DIRECTION OUTPUT ;
    USE SIGNAL ;
    PORT
      LAYER M5 ;
        RECT  28.032 0 28.056 0.192 ;
    END
  END o_d[142]
  PIN o_d[143]
    DIRECTION OUTPUT ;
    USE SIGNAL ;
    PORT
      LAYER M5 ;
        RECT  28.176 0 28.2 0.192 ;
    END
  END o_d[143]
  PIN o_d[144]
    DIRECTION OUTPUT ;
    USE SIGNAL ;
    PORT
      LAYER M5 ;
        RECT  28.32 0 28.344 0.192 ;
    END
  END o_d[144]
  PIN o_d[145]
    DIRECTION OUTPUT ;
    USE SIGNAL ;
    PORT
      LAYER M5 ;
        RECT  28.464 0 28.488 0.192 ;
    END
  END o_d[145]
  PIN o_d[146]
    DIRECTION OUTPUT ;
    USE SIGNAL ;
    PORT
      LAYER M5 ;
        RECT  28.608 0 28.632 0.192 ;
    END
  END o_d[146]
  PIN o_d[147]
    DIRECTION OUTPUT ;
    USE SIGNAL ;
    PORT
      LAYER M5 ;
        RECT  28.752 0 28.776 0.192 ;
    END
  END o_d[147]
  PIN o_d[148]
    DIRECTION OUTPUT ;
    USE SIGNAL ;
    PORT
      LAYER M5 ;
        RECT  28.896 0 28.92 0.192 ;
    END
  END o_d[148]
  PIN o_d[149]
    DIRECTION OUTPUT ;
    USE SIGNAL ;
    PORT
      LAYER M5 ;
        RECT  29.04 0 29.064 0.192 ;
    END
  END o_d[149]
  PIN o_d[14]
    DIRECTION OUTPUT ;
    USE SIGNAL ;
    PORT
      LAYER M5 ;
        RECT  6.864 0 6.888 0.192 ;
    END
  END o_d[14]
  PIN o_d[150]
    DIRECTION OUTPUT ;
    USE SIGNAL ;
    PORT
      LAYER M5 ;
        RECT  29.184 0 29.208 0.192 ;
    END
  END o_d[150]
  PIN o_d[151]
    DIRECTION OUTPUT ;
    USE SIGNAL ;
    PORT
      LAYER M5 ;
        RECT  29.328 0 29.352 0.192 ;
    END
  END o_d[151]
  PIN o_d[152]
    DIRECTION OUTPUT ;
    USE SIGNAL ;
    PORT
      LAYER M5 ;
        RECT  29.472 0 29.496 0.192 ;
    END
  END o_d[152]
  PIN o_d[153]
    DIRECTION OUTPUT ;
    USE SIGNAL ;
    PORT
      LAYER M5 ;
        RECT  29.616 0 29.64 0.192 ;
    END
  END o_d[153]
  PIN o_d[154]
    DIRECTION OUTPUT ;
    USE SIGNAL ;
    PORT
      LAYER M5 ;
        RECT  29.76 0 29.784 0.192 ;
    END
  END o_d[154]
  PIN o_d[155]
    DIRECTION OUTPUT ;
    USE SIGNAL ;
    PORT
      LAYER M5 ;
        RECT  29.904 0 29.928 0.192 ;
    END
  END o_d[155]
  PIN o_d[156]
    DIRECTION OUTPUT ;
    USE SIGNAL ;
    PORT
      LAYER M5 ;
        RECT  30.048 0 30.072 0.192 ;
    END
  END o_d[156]
  PIN o_d[157]
    DIRECTION OUTPUT ;
    USE SIGNAL ;
    PORT
      LAYER M5 ;
        RECT  30.192 0 30.216 0.192 ;
    END
  END o_d[157]
  PIN o_d[158]
    DIRECTION OUTPUT ;
    USE SIGNAL ;
    PORT
      LAYER M5 ;
        RECT  30.336 0 30.36 0.192 ;
    END
  END o_d[158]
  PIN o_d[159]
    DIRECTION OUTPUT ;
    USE SIGNAL ;
    PORT
      LAYER M5 ;
        RECT  30.48 0 30.504 0.192 ;
    END
  END o_d[159]
  PIN o_d[15]
    DIRECTION OUTPUT ;
    USE SIGNAL ;
    PORT
      LAYER M5 ;
        RECT  7.152 0 7.176 0.192 ;
    END
  END o_d[15]
  PIN o_d[160]
    DIRECTION OUTPUT ;
    USE SIGNAL ;
    PORT
      LAYER M5 ;
        RECT  30.624 0 30.648 0.192 ;
    END
  END o_d[160]
  PIN o_d[161]
    DIRECTION OUTPUT ;
    USE SIGNAL ;
    PORT
      LAYER M5 ;
        RECT  30.768 0 30.792 0.192 ;
    END
  END o_d[161]
  PIN o_d[162]
    DIRECTION OUTPUT ;
    USE SIGNAL ;
    PORT
      LAYER M5 ;
        RECT  30.912 0 30.936 0.192 ;
    END
  END o_d[162]
  PIN o_d[163]
    DIRECTION OUTPUT ;
    USE SIGNAL ;
    PORT
      LAYER M5 ;
        RECT  31.056 0 31.08 0.192 ;
    END
  END o_d[163]
  PIN o_d[164]
    DIRECTION OUTPUT ;
    USE SIGNAL ;
    PORT
      LAYER M5 ;
        RECT  31.2 0 31.224 0.192 ;
    END
  END o_d[164]
  PIN o_d[165]
    DIRECTION OUTPUT ;
    USE SIGNAL ;
    PORT
      LAYER M5 ;
        RECT  31.344 0 31.368 0.192 ;
    END
  END o_d[165]
  PIN o_d[166]
    DIRECTION OUTPUT ;
    USE SIGNAL ;
    PORT
      LAYER M5 ;
        RECT  31.488 0 31.512 0.192 ;
    END
  END o_d[166]
  PIN o_d[167]
    DIRECTION OUTPUT ;
    USE SIGNAL ;
    PORT
      LAYER M5 ;
        RECT  31.632 0 31.656 0.192 ;
    END
  END o_d[167]
  PIN o_d[168]
    DIRECTION OUTPUT ;
    USE SIGNAL ;
    PORT
      LAYER M5 ;
        RECT  31.776 0 31.8 0.192 ;
    END
  END o_d[168]
  PIN o_d[169]
    DIRECTION OUTPUT ;
    USE SIGNAL ;
    PORT
      LAYER M5 ;
        RECT  31.92 0 31.944 0.192 ;
    END
  END o_d[169]
  PIN o_d[16]
    DIRECTION OUTPUT ;
    USE SIGNAL ;
    PORT
      LAYER M5 ;
        RECT  7.296 0 7.32 0.192 ;
    END
  END o_d[16]
  PIN o_d[170]
    DIRECTION OUTPUT ;
    USE SIGNAL ;
    PORT
      LAYER M5 ;
        RECT  32.208 0 32.232 0.192 ;
    END
  END o_d[170]
  PIN o_d[171]
    DIRECTION OUTPUT ;
    USE SIGNAL ;
    PORT
      LAYER M5 ;
        RECT  32.352 0 32.376 0.192 ;
    END
  END o_d[171]
  PIN o_d[172]
    DIRECTION OUTPUT ;
    USE SIGNAL ;
    PORT
      LAYER M5 ;
        RECT  32.496 0 32.52 0.192 ;
    END
  END o_d[172]
  PIN o_d[173]
    DIRECTION OUTPUT ;
    USE SIGNAL ;
    PORT
      LAYER M5 ;
        RECT  33.168 0 33.192 0.192 ;
    END
  END o_d[173]
  PIN o_d[174]
    DIRECTION OUTPUT ;
    USE SIGNAL ;
    PORT
      LAYER M5 ;
        RECT  33.312 0 33.336 0.192 ;
    END
  END o_d[174]
  PIN o_d[175]
    DIRECTION OUTPUT ;
    USE SIGNAL ;
    PORT
      LAYER M5 ;
        RECT  33.456 0 33.48 0.192 ;
    END
  END o_d[175]
  PIN o_d[176]
    DIRECTION OUTPUT ;
    USE SIGNAL ;
    PORT
      LAYER M5 ;
        RECT  33.6 0 33.624 0.192 ;
    END
  END o_d[176]
  PIN o_d[177]
    DIRECTION OUTPUT ;
    USE SIGNAL ;
    PORT
      LAYER M5 ;
        RECT  33.744 0 33.768 0.192 ;
    END
  END o_d[177]
  PIN o_d[178]
    DIRECTION OUTPUT ;
    USE SIGNAL ;
    PORT
      LAYER M5 ;
        RECT  33.888 0 33.912 0.192 ;
    END
  END o_d[178]
  PIN o_d[179]
    DIRECTION OUTPUT ;
    USE SIGNAL ;
    PORT
      LAYER M5 ;
        RECT  34.032 0 34.056 0.192 ;
    END
  END o_d[179]
  PIN o_d[17]
    DIRECTION OUTPUT ;
    USE SIGNAL ;
    PORT
      LAYER M5 ;
        RECT  7.44 0 7.464 0.192 ;
    END
  END o_d[17]
  PIN o_d[180]
    DIRECTION OUTPUT ;
    USE SIGNAL ;
    PORT
      LAYER M5 ;
        RECT  34.176 0 34.2 0.192 ;
    END
  END o_d[180]
  PIN o_d[181]
    DIRECTION OUTPUT ;
    USE SIGNAL ;
    PORT
      LAYER M5 ;
        RECT  34.32 0 34.344 0.192 ;
    END
  END o_d[181]
  PIN o_d[182]
    DIRECTION OUTPUT ;
    USE SIGNAL ;
    PORT
      LAYER M5 ;
        RECT  34.464 0 34.488 0.192 ;
    END
  END o_d[182]
  PIN o_d[183]
    DIRECTION OUTPUT ;
    USE SIGNAL ;
    PORT
      LAYER M5 ;
        RECT  34.608 0 34.632 0.192 ;
    END
  END o_d[183]
  PIN o_d[184]
    DIRECTION OUTPUT ;
    USE SIGNAL ;
    PORT
      LAYER M5 ;
        RECT  34.752 0 34.776 0.192 ;
    END
  END o_d[184]
  PIN o_d[185]
    DIRECTION OUTPUT ;
    USE SIGNAL ;
    PORT
      LAYER M5 ;
        RECT  34.896 0 34.92 0.192 ;
    END
  END o_d[185]
  PIN o_d[186]
    DIRECTION OUTPUT ;
    USE SIGNAL ;
    PORT
      LAYER M5 ;
        RECT  35.04 0 35.064 0.192 ;
    END
  END o_d[186]
  PIN o_d[187]
    DIRECTION OUTPUT ;
    USE SIGNAL ;
    PORT
      LAYER M5 ;
        RECT  35.184 0 35.208 0.192 ;
    END
  END o_d[187]
  PIN o_d[188]
    DIRECTION OUTPUT ;
    USE SIGNAL ;
    PORT
      LAYER M5 ;
        RECT  35.328 0 35.352 0.192 ;
    END
  END o_d[188]
  PIN o_d[189]
    DIRECTION OUTPUT ;
    USE SIGNAL ;
    PORT
      LAYER M5 ;
        RECT  35.472 0 35.496 0.192 ;
    END
  END o_d[189]
  PIN o_d[18]
    DIRECTION OUTPUT ;
    USE SIGNAL ;
    PORT
      LAYER M5 ;
        RECT  7.584 0 7.608 0.192 ;
    END
  END o_d[18]
  PIN o_d[190]
    DIRECTION OUTPUT ;
    USE SIGNAL ;
    PORT
      LAYER M5 ;
        RECT  35.616 0 35.64 0.192 ;
    END
  END o_d[190]
  PIN o_d[191]
    DIRECTION OUTPUT ;
    USE SIGNAL ;
    PORT
      LAYER M5 ;
        RECT  35.76 0 35.784 0.192 ;
    END
  END o_d[191]
  PIN o_d[192]
    DIRECTION OUTPUT ;
    USE SIGNAL ;
    PORT
      LAYER M5 ;
        RECT  35.904 0 35.928 0.192 ;
    END
  END o_d[192]
  PIN o_d[193]
    DIRECTION OUTPUT ;
    USE SIGNAL ;
    PORT
      LAYER M5 ;
        RECT  36.048 0 36.072 0.192 ;
    END
  END o_d[193]
  PIN o_d[194]
    DIRECTION OUTPUT ;
    USE SIGNAL ;
    PORT
      LAYER M5 ;
        RECT  36.192 0 36.216 0.192 ;
    END
  END o_d[194]
  PIN o_d[195]
    DIRECTION OUTPUT ;
    USE SIGNAL ;
    PORT
      LAYER M5 ;
        RECT  36.336 0 36.36 0.192 ;
    END
  END o_d[195]
  PIN o_d[196]
    DIRECTION OUTPUT ;
    USE SIGNAL ;
    PORT
      LAYER M5 ;
        RECT  36.48 0 36.504 0.192 ;
    END
  END o_d[196]
  PIN o_d[197]
    DIRECTION OUTPUT ;
    USE SIGNAL ;
    PORT
      LAYER M5 ;
        RECT  36.624 0 36.648 0.192 ;
    END
  END o_d[197]
  PIN o_d[198]
    DIRECTION OUTPUT ;
    USE SIGNAL ;
    PORT
      LAYER M5 ;
        RECT  36.768 0 36.792 0.192 ;
    END
  END o_d[198]
  PIN o_d[199]
    DIRECTION OUTPUT ;
    USE SIGNAL ;
    PORT
      LAYER M5 ;
        RECT  36.912 0 36.936 0.192 ;
    END
  END o_d[199]
  PIN o_d[19]
    DIRECTION OUTPUT ;
    USE SIGNAL ;
    PORT
      LAYER M5 ;
        RECT  7.728 0 7.752 0.192 ;
    END
  END o_d[19]
  PIN o_d[1]
    DIRECTION OUTPUT ;
    USE SIGNAL ;
    PORT
      LAYER M5 ;
        RECT  4.464 0 4.488 0.192 ;
    END
  END o_d[1]
  PIN o_d[200]
    DIRECTION OUTPUT ;
    USE SIGNAL ;
    PORT
      LAYER M5 ;
        RECT  37.056 0 37.08 0.192 ;
    END
  END o_d[200]
  PIN o_d[201]
    DIRECTION OUTPUT ;
    USE SIGNAL ;
    PORT
      LAYER M5 ;
        RECT  37.344 0 37.368 0.192 ;
    END
  END o_d[201]
  PIN o_d[202]
    DIRECTION OUTPUT ;
    USE SIGNAL ;
    PORT
      LAYER M5 ;
        RECT  37.488 0 37.512 0.192 ;
    END
  END o_d[202]
  PIN o_d[203]
    DIRECTION OUTPUT ;
    USE SIGNAL ;
    PORT
      LAYER M5 ;
        RECT  37.632 0 37.656 0.192 ;
    END
  END o_d[203]
  PIN o_d[204]
    DIRECTION OUTPUT ;
    USE SIGNAL ;
    PORT
      LAYER M5 ;
        RECT  37.776 0 37.8 0.192 ;
    END
  END o_d[204]
  PIN o_d[205]
    DIRECTION OUTPUT ;
    USE SIGNAL ;
    PORT
      LAYER M5 ;
        RECT  37.92 0 37.944 0.192 ;
    END
  END o_d[205]
  PIN o_d[206]
    DIRECTION OUTPUT ;
    USE SIGNAL ;
    PORT
      LAYER M5 ;
        RECT  38.544 0 38.568 0.192 ;
    END
  END o_d[206]
  PIN o_d[207]
    DIRECTION OUTPUT ;
    USE SIGNAL ;
    PORT
      LAYER M5 ;
        RECT  38.688 0 38.712 0.192 ;
    END
  END o_d[207]
  PIN o_d[208]
    DIRECTION OUTPUT ;
    USE SIGNAL ;
    PORT
      LAYER M5 ;
        RECT  38.832 0 38.856 0.192 ;
    END
  END o_d[208]
  PIN o_d[209]
    DIRECTION OUTPUT ;
    USE SIGNAL ;
    PORT
      LAYER M5 ;
        RECT  38.976 0 39 0.192 ;
    END
  END o_d[209]
  PIN o_d[20]
    DIRECTION OUTPUT ;
    USE SIGNAL ;
    PORT
      LAYER M5 ;
        RECT  7.872 0 7.896 0.192 ;
    END
  END o_d[20]
  PIN o_d[210]
    DIRECTION OUTPUT ;
    USE SIGNAL ;
    PORT
      LAYER M5 ;
        RECT  39.12 0 39.144 0.192 ;
    END
  END o_d[210]
  PIN o_d[211]
    DIRECTION OUTPUT ;
    USE SIGNAL ;
    PORT
      LAYER M5 ;
        RECT  39.264 0 39.288 0.192 ;
    END
  END o_d[211]
  PIN o_d[212]
    DIRECTION OUTPUT ;
    USE SIGNAL ;
    PORT
      LAYER M5 ;
        RECT  39.408 0 39.432 0.192 ;
    END
  END o_d[212]
  PIN o_d[213]
    DIRECTION OUTPUT ;
    USE SIGNAL ;
    PORT
      LAYER M5 ;
        RECT  39.552 0 39.576 0.192 ;
    END
  END o_d[213]
  PIN o_d[214]
    DIRECTION OUTPUT ;
    USE SIGNAL ;
    PORT
      LAYER M5 ;
        RECT  39.696 0 39.72 0.192 ;
    END
  END o_d[214]
  PIN o_d[215]
    DIRECTION OUTPUT ;
    USE SIGNAL ;
    PORT
      LAYER M5 ;
        RECT  39.84 0 39.864 0.192 ;
    END
  END o_d[215]
  PIN o_d[216]
    DIRECTION OUTPUT ;
    USE SIGNAL ;
    PORT
      LAYER M5 ;
        RECT  39.984 0 40.008 0.192 ;
    END
  END o_d[216]
  PIN o_d[217]
    DIRECTION OUTPUT ;
    USE SIGNAL ;
    PORT
      LAYER M5 ;
        RECT  40.128 0 40.152 0.192 ;
    END
  END o_d[217]
  PIN o_d[218]
    DIRECTION OUTPUT ;
    USE SIGNAL ;
    PORT
      LAYER M5 ;
        RECT  40.272 0 40.296 0.192 ;
    END
  END o_d[218]
  PIN o_d[219]
    DIRECTION OUTPUT ;
    USE SIGNAL ;
    PORT
      LAYER M5 ;
        RECT  40.416 0 40.44 0.192 ;
    END
  END o_d[219]
  PIN o_d[21]
    DIRECTION OUTPUT ;
    USE SIGNAL ;
    PORT
      LAYER M5 ;
        RECT  8.016 0 8.04 0.192 ;
    END
  END o_d[21]
  PIN o_d[220]
    DIRECTION OUTPUT ;
    USE SIGNAL ;
    PORT
      LAYER M5 ;
        RECT  40.56 0 40.584 0.192 ;
    END
  END o_d[220]
  PIN o_d[221]
    DIRECTION OUTPUT ;
    USE SIGNAL ;
    PORT
      LAYER M5 ;
        RECT  40.704 0 40.728 0.192 ;
    END
  END o_d[221]
  PIN o_d[222]
    DIRECTION OUTPUT ;
    USE SIGNAL ;
    PORT
      LAYER M5 ;
        RECT  40.848 0 40.872 0.192 ;
    END
  END o_d[222]
  PIN o_d[223]
    DIRECTION OUTPUT ;
    USE SIGNAL ;
    PORT
      LAYER M5 ;
        RECT  40.992 0 41.016 0.192 ;
    END
  END o_d[223]
  PIN o_d[224]
    DIRECTION OUTPUT ;
    USE SIGNAL ;
    PORT
      LAYER M5 ;
        RECT  41.136 0 41.16 0.192 ;
    END
  END o_d[224]
  PIN o_d[225]
    DIRECTION OUTPUT ;
    USE SIGNAL ;
    PORT
      LAYER M5 ;
        RECT  41.28 0 41.304 0.192 ;
    END
  END o_d[225]
  PIN o_d[226]
    DIRECTION OUTPUT ;
    USE SIGNAL ;
    PORT
      LAYER M5 ;
        RECT  41.424 0 41.448 0.192 ;
    END
  END o_d[226]
  PIN o_d[227]
    DIRECTION OUTPUT ;
    USE SIGNAL ;
    PORT
      LAYER M5 ;
        RECT  41.568 0 41.592 0.192 ;
    END
  END o_d[227]
  PIN o_d[228]
    DIRECTION OUTPUT ;
    USE SIGNAL ;
    PORT
      LAYER M5 ;
        RECT  41.712 0 41.736 0.192 ;
    END
  END o_d[228]
  PIN o_d[229]
    DIRECTION OUTPUT ;
    USE SIGNAL ;
    PORT
      LAYER M5 ;
        RECT  41.856 0 41.88 0.192 ;
    END
  END o_d[229]
  PIN o_d[22]
    DIRECTION OUTPUT ;
    USE SIGNAL ;
    PORT
      LAYER M5 ;
        RECT  8.16 0 8.184 0.192 ;
    END
  END o_d[22]
  PIN o_d[230]
    DIRECTION OUTPUT ;
    USE SIGNAL ;
    PORT
      LAYER M5 ;
        RECT  42 0 42.024 0.192 ;
    END
  END o_d[230]
  PIN o_d[231]
    DIRECTION OUTPUT ;
    USE SIGNAL ;
    PORT
      LAYER M5 ;
        RECT  42.144 0 42.168 0.192 ;
    END
  END o_d[231]
  PIN o_d[232]
    DIRECTION OUTPUT ;
    USE SIGNAL ;
    PORT
      LAYER M5 ;
        RECT  42.432 0 42.456 0.192 ;
    END
  END o_d[232]
  PIN o_d[233]
    DIRECTION OUTPUT ;
    USE SIGNAL ;
    PORT
      LAYER M5 ;
        RECT  42.576 0 42.6 0.192 ;
    END
  END o_d[233]
  PIN o_d[234]
    DIRECTION OUTPUT ;
    USE SIGNAL ;
    PORT
      LAYER M5 ;
        RECT  42.72 0 42.744 0.192 ;
    END
  END o_d[234]
  PIN o_d[235]
    DIRECTION OUTPUT ;
    USE SIGNAL ;
    PORT
      LAYER M5 ;
        RECT  42.864 0 42.888 0.192 ;
    END
  END o_d[235]
  PIN o_d[236]
    DIRECTION OUTPUT ;
    USE SIGNAL ;
    PORT
      LAYER M5 ;
        RECT  43.008 0 43.032 0.192 ;
    END
  END o_d[236]
  PIN o_d[237]
    DIRECTION OUTPUT ;
    USE SIGNAL ;
    PORT
      LAYER M5 ;
        RECT  43.152 0 43.176 0.192 ;
    END
  END o_d[237]
  PIN o_d[238]
    DIRECTION OUTPUT ;
    USE SIGNAL ;
    PORT
      LAYER M5 ;
        RECT  43.296 0 43.32 0.192 ;
    END
  END o_d[238]
  PIN o_d[239]
    DIRECTION OUTPUT ;
    USE SIGNAL ;
    PORT
      LAYER M5 ;
        RECT  43.968 0 43.992 0.192 ;
    END
  END o_d[239]
  PIN o_d[23]
    DIRECTION OUTPUT ;
    USE SIGNAL ;
    PORT
      LAYER M5 ;
        RECT  8.304 0 8.328 0.192 ;
    END
  END o_d[23]
  PIN o_d[240]
    DIRECTION OUTPUT ;
    USE SIGNAL ;
    PORT
      LAYER M5 ;
        RECT  44.112 0 44.136 0.192 ;
    END
  END o_d[240]
  PIN o_d[241]
    DIRECTION OUTPUT ;
    USE SIGNAL ;
    PORT
      LAYER M5 ;
        RECT  44.256 0 44.28 0.192 ;
    END
  END o_d[241]
  PIN o_d[242]
    DIRECTION OUTPUT ;
    USE SIGNAL ;
    PORT
      LAYER M5 ;
        RECT  44.4 0 44.424 0.192 ;
    END
  END o_d[242]
  PIN o_d[243]
    DIRECTION OUTPUT ;
    USE SIGNAL ;
    PORT
      LAYER M5 ;
        RECT  44.544 0 44.568 0.192 ;
    END
  END o_d[243]
  PIN o_d[244]
    DIRECTION OUTPUT ;
    USE SIGNAL ;
    PORT
      LAYER M5 ;
        RECT  44.688 0 44.712 0.192 ;
    END
  END o_d[244]
  PIN o_d[245]
    DIRECTION OUTPUT ;
    USE SIGNAL ;
    PORT
      LAYER M5 ;
        RECT  44.832 0 44.856 0.192 ;
    END
  END o_d[245]
  PIN o_d[246]
    DIRECTION OUTPUT ;
    USE SIGNAL ;
    PORT
      LAYER M5 ;
        RECT  44.976 0 45 0.192 ;
    END
  END o_d[246]
  PIN o_d[247]
    DIRECTION OUTPUT ;
    USE SIGNAL ;
    PORT
      LAYER M5 ;
        RECT  45.12 0 45.144 0.192 ;
    END
  END o_d[247]
  PIN o_d[248]
    DIRECTION OUTPUT ;
    USE SIGNAL ;
    PORT
      LAYER M5 ;
        RECT  45.264 0 45.288 0.192 ;
    END
  END o_d[248]
  PIN o_d[249]
    DIRECTION OUTPUT ;
    USE SIGNAL ;
    PORT
      LAYER M5 ;
        RECT  45.408 0 45.432 0.192 ;
    END
  END o_d[249]
  PIN o_d[24]
    DIRECTION OUTPUT ;
    USE SIGNAL ;
    PORT
      LAYER M5 ;
        RECT  8.448 0 8.472 0.192 ;
    END
  END o_d[24]
  PIN o_d[250]
    DIRECTION OUTPUT ;
    USE SIGNAL ;
    PORT
      LAYER M5 ;
        RECT  45.552 0 45.576 0.192 ;
    END
  END o_d[250]
  PIN o_d[251]
    DIRECTION OUTPUT ;
    USE SIGNAL ;
    PORT
      LAYER M5 ;
        RECT  45.696 0 45.72 0.192 ;
    END
  END o_d[251]
  PIN o_d[252]
    DIRECTION OUTPUT ;
    USE SIGNAL ;
    PORT
      LAYER M5 ;
        RECT  45.84 0 45.864 0.192 ;
    END
  END o_d[252]
  PIN o_d[253]
    DIRECTION OUTPUT ;
    USE SIGNAL ;
    PORT
      LAYER M5 ;
        RECT  45.984 0 46.008 0.192 ;
    END
  END o_d[253]
  PIN o_d[254]
    DIRECTION OUTPUT ;
    USE SIGNAL ;
    PORT
      LAYER M5 ;
        RECT  46.128 0 46.152 0.192 ;
    END
  END o_d[254]
  PIN o_d[255]
    DIRECTION OUTPUT ;
    USE SIGNAL ;
    PORT
      LAYER M5 ;
        RECT  46.272 0 46.296 0.192 ;
    END
  END o_d[255]
  PIN o_d[256]
    DIRECTION OUTPUT ;
    USE SIGNAL ;
    PORT
      LAYER M5 ;
        RECT  46.416 0 46.44 0.192 ;
    END
  END o_d[256]
  PIN o_d[257]
    DIRECTION OUTPUT ;
    USE SIGNAL ;
    PORT
      LAYER M5 ;
        RECT  46.56 0 46.584 0.192 ;
    END
  END o_d[257]
  PIN o_d[258]
    DIRECTION OUTPUT ;
    USE SIGNAL ;
    PORT
      LAYER M5 ;
        RECT  46.704 0 46.728 0.192 ;
    END
  END o_d[258]
  PIN o_d[259]
    DIRECTION OUTPUT ;
    USE SIGNAL ;
    PORT
      LAYER M5 ;
        RECT  46.848 0 46.872 0.192 ;
    END
  END o_d[259]
  PIN o_d[25]
    DIRECTION OUTPUT ;
    USE SIGNAL ;
    PORT
      LAYER M5 ;
        RECT  8.592 0 8.616 0.192 ;
    END
  END o_d[25]
  PIN o_d[260]
    DIRECTION OUTPUT ;
    USE SIGNAL ;
    PORT
      LAYER M5 ;
        RECT  46.992 0 47.016 0.192 ;
    END
  END o_d[260]
  PIN o_d[261]
    DIRECTION OUTPUT ;
    USE SIGNAL ;
    PORT
      LAYER M5 ;
        RECT  47.136 0 47.16 0.192 ;
    END
  END o_d[261]
  PIN o_d[262]
    DIRECTION OUTPUT ;
    USE SIGNAL ;
    PORT
      LAYER M5 ;
        RECT  47.28 0 47.304 0.192 ;
    END
  END o_d[262]
  PIN o_d[263]
    DIRECTION OUTPUT ;
    USE SIGNAL ;
    PORT
      LAYER M5 ;
        RECT  47.568 0 47.592 0.192 ;
    END
  END o_d[263]
  PIN o_d[264]
    DIRECTION OUTPUT ;
    USE SIGNAL ;
    PORT
      LAYER M5 ;
        RECT  47.712 0 47.736 0.192 ;
    END
  END o_d[264]
  PIN o_d[265]
    DIRECTION OUTPUT ;
    USE SIGNAL ;
    PORT
      LAYER M5 ;
        RECT  47.856 0 47.88 0.192 ;
    END
  END o_d[265]
  PIN o_d[266]
    DIRECTION OUTPUT ;
    USE SIGNAL ;
    PORT
      LAYER M5 ;
        RECT  48 0 48.024 0.192 ;
    END
  END o_d[266]
  PIN o_d[267]
    DIRECTION OUTPUT ;
    USE SIGNAL ;
    PORT
      LAYER M5 ;
        RECT  48.144 0 48.168 0.192 ;
    END
  END o_d[267]
  PIN o_d[268]
    DIRECTION OUTPUT ;
    USE SIGNAL ;
    PORT
      LAYER M5 ;
        RECT  48.288 0 48.312 0.192 ;
    END
  END o_d[268]
  PIN o_d[269]
    DIRECTION OUTPUT ;
    USE SIGNAL ;
    PORT
      LAYER M5 ;
        RECT  48.432 0 48.456 0.192 ;
    END
  END o_d[269]
  PIN o_d[26]
    DIRECTION OUTPUT ;
    USE SIGNAL ;
    PORT
      LAYER M5 ;
        RECT  8.736 0 8.76 0.192 ;
    END
  END o_d[26]
  PIN o_d[270]
    DIRECTION OUTPUT ;
    USE SIGNAL ;
    PORT
      LAYER M5 ;
        RECT  48.576 0 48.6 0.192 ;
    END
  END o_d[270]
  PIN o_d[271]
    DIRECTION OUTPUT ;
    USE SIGNAL ;
    PORT
      LAYER M5 ;
        RECT  48.72 0 48.744 0.192 ;
    END
  END o_d[271]
  PIN o_d[272]
    DIRECTION OUTPUT ;
    USE SIGNAL ;
    PORT
      LAYER M5 ;
        RECT  49.344 0 49.368 0.192 ;
    END
  END o_d[272]
  PIN o_d[273]
    DIRECTION OUTPUT ;
    USE SIGNAL ;
    PORT
      LAYER M5 ;
        RECT  49.488 0 49.512 0.192 ;
    END
  END o_d[273]
  PIN o_d[274]
    DIRECTION OUTPUT ;
    USE SIGNAL ;
    PORT
      LAYER M5 ;
        RECT  49.632 0 49.656 0.192 ;
    END
  END o_d[274]
  PIN o_d[275]
    DIRECTION OUTPUT ;
    USE SIGNAL ;
    PORT
      LAYER M5 ;
        RECT  49.776 0 49.8 0.192 ;
    END
  END o_d[275]
  PIN o_d[276]
    DIRECTION OUTPUT ;
    USE SIGNAL ;
    PORT
      LAYER M5 ;
        RECT  49.92 0 49.944 0.192 ;
    END
  END o_d[276]
  PIN o_d[277]
    DIRECTION OUTPUT ;
    USE SIGNAL ;
    PORT
      LAYER M5 ;
        RECT  50.064 0 50.088 0.192 ;
    END
  END o_d[277]
  PIN o_d[278]
    DIRECTION OUTPUT ;
    USE SIGNAL ;
    PORT
      LAYER M5 ;
        RECT  50.208 0 50.232 0.192 ;
    END
  END o_d[278]
  PIN o_d[279]
    DIRECTION OUTPUT ;
    USE SIGNAL ;
    PORT
      LAYER M5 ;
        RECT  50.352 0 50.376 0.192 ;
    END
  END o_d[279]
  PIN o_d[27]
    DIRECTION OUTPUT ;
    USE SIGNAL ;
    PORT
      LAYER M5 ;
        RECT  8.88 0 8.904 0.192 ;
    END
  END o_d[27]
  PIN o_d[280]
    DIRECTION OUTPUT ;
    USE SIGNAL ;
    PORT
      LAYER M5 ;
        RECT  50.496 0 50.52 0.192 ;
    END
  END o_d[280]
  PIN o_d[281]
    DIRECTION OUTPUT ;
    USE SIGNAL ;
    PORT
      LAYER M5 ;
        RECT  50.64 0 50.664 0.192 ;
    END
  END o_d[281]
  PIN o_d[282]
    DIRECTION OUTPUT ;
    USE SIGNAL ;
    PORT
      LAYER M5 ;
        RECT  50.784 0 50.808 0.192 ;
    END
  END o_d[282]
  PIN o_d[283]
    DIRECTION OUTPUT ;
    USE SIGNAL ;
    PORT
      LAYER M5 ;
        RECT  50.928 0 50.952 0.192 ;
    END
  END o_d[283]
  PIN o_d[284]
    DIRECTION OUTPUT ;
    USE SIGNAL ;
    PORT
      LAYER M5 ;
        RECT  51.072 0 51.096 0.192 ;
    END
  END o_d[284]
  PIN o_d[285]
    DIRECTION OUTPUT ;
    USE SIGNAL ;
    PORT
      LAYER M5 ;
        RECT  51.216 0 51.24 0.192 ;
    END
  END o_d[285]
  PIN o_d[286]
    DIRECTION OUTPUT ;
    USE SIGNAL ;
    PORT
      LAYER M5 ;
        RECT  51.36 0 51.384 0.192 ;
    END
  END o_d[286]
  PIN o_d[287]
    DIRECTION OUTPUT ;
    USE SIGNAL ;
    PORT
      LAYER M5 ;
        RECT  51.504 0 51.528 0.192 ;
    END
  END o_d[287]
  PIN o_d[288]
    DIRECTION OUTPUT ;
    USE SIGNAL ;
    PORT
      LAYER M5 ;
        RECT  51.648 0 51.672 0.192 ;
    END
  END o_d[288]
  PIN o_d[289]
    DIRECTION OUTPUT ;
    USE SIGNAL ;
    PORT
      LAYER M5 ;
        RECT  51.792 0 51.816 0.192 ;
    END
  END o_d[289]
  PIN o_d[28]
    DIRECTION OUTPUT ;
    USE SIGNAL ;
    PORT
      LAYER M5 ;
        RECT  9.024 0 9.048 0.192 ;
    END
  END o_d[28]
  PIN o_d[290]
    DIRECTION OUTPUT ;
    USE SIGNAL ;
    PORT
      LAYER M5 ;
        RECT  51.936 0 51.96 0.192 ;
    END
  END o_d[290]
  PIN o_d[291]
    DIRECTION OUTPUT ;
    USE SIGNAL ;
    PORT
      LAYER M5 ;
        RECT  52.08 0 52.104 0.192 ;
    END
  END o_d[291]
  PIN o_d[292]
    DIRECTION OUTPUT ;
    USE SIGNAL ;
    PORT
      LAYER M5 ;
        RECT  52.224 0 52.248 0.192 ;
    END
  END o_d[292]
  PIN o_d[293]
    DIRECTION OUTPUT ;
    USE SIGNAL ;
    PORT
      LAYER M5 ;
        RECT  52.368 0 52.392 0.192 ;
    END
  END o_d[293]
  PIN o_d[294]
    DIRECTION OUTPUT ;
    USE SIGNAL ;
    PORT
      LAYER M5 ;
        RECT  52.656 0 52.68 0.192 ;
    END
  END o_d[294]
  PIN o_d[295]
    DIRECTION OUTPUT ;
    USE SIGNAL ;
    PORT
      LAYER M5 ;
        RECT  52.8 0 52.824 0.192 ;
    END
  END o_d[295]
  PIN o_d[296]
    DIRECTION OUTPUT ;
    USE SIGNAL ;
    PORT
      LAYER M5 ;
        RECT  52.944 0 52.968 0.192 ;
    END
  END o_d[296]
  PIN o_d[297]
    DIRECTION OUTPUT ;
    USE SIGNAL ;
    PORT
      LAYER M5 ;
        RECT  53.088 0 53.112 0.192 ;
    END
  END o_d[297]
  PIN o_d[298]
    DIRECTION OUTPUT ;
    USE SIGNAL ;
    PORT
      LAYER M5 ;
        RECT  53.232 0 53.256 0.192 ;
    END
  END o_d[298]
  PIN o_d[299]
    DIRECTION OUTPUT ;
    USE SIGNAL ;
    PORT
      LAYER M5 ;
        RECT  53.376 0 53.4 0.192 ;
    END
  END o_d[299]
  PIN o_d[29]
    DIRECTION OUTPUT ;
    USE SIGNAL ;
    PORT
      LAYER M5 ;
        RECT  9.168 0 9.192 0.192 ;
    END
  END o_d[29]
  PIN o_d[2]
    DIRECTION OUTPUT ;
    USE SIGNAL ;
    PORT
      LAYER M5 ;
        RECT  4.608 0 4.632 0.192 ;
    END
  END o_d[2]
  PIN o_d[300]
    DIRECTION OUTPUT ;
    USE SIGNAL ;
    PORT
      LAYER M5 ;
        RECT  53.52 0 53.544 0.192 ;
    END
  END o_d[300]
  PIN o_d[301]
    DIRECTION OUTPUT ;
    USE SIGNAL ;
    PORT
      LAYER M5 ;
        RECT  53.664 0 53.688 0.192 ;
    END
  END o_d[301]
  PIN o_d[302]
    DIRECTION OUTPUT ;
    USE SIGNAL ;
    PORT
      LAYER M5 ;
        RECT  53.808 0 53.832 0.192 ;
    END
  END o_d[302]
  PIN o_d[303]
    DIRECTION OUTPUT ;
    USE SIGNAL ;
    PORT
      LAYER M5 ;
        RECT  53.952 0 53.976 0.192 ;
    END
  END o_d[303]
  PIN o_d[304]
    DIRECTION OUTPUT ;
    USE SIGNAL ;
    PORT
      LAYER M5 ;
        RECT  54.096 0 54.12 0.192 ;
    END
  END o_d[304]
  PIN o_d[305]
    DIRECTION OUTPUT ;
    USE SIGNAL ;
    PORT
      LAYER M5 ;
        RECT  54.768 0 54.792 0.192 ;
    END
  END o_d[305]
  PIN o_d[306]
    DIRECTION OUTPUT ;
    USE SIGNAL ;
    PORT
      LAYER M5 ;
        RECT  54.912 0 54.936 0.192 ;
    END
  END o_d[306]
  PIN o_d[307]
    DIRECTION OUTPUT ;
    USE SIGNAL ;
    PORT
      LAYER M5 ;
        RECT  55.056 0 55.08 0.192 ;
    END
  END o_d[307]
  PIN o_d[308]
    DIRECTION OUTPUT ;
    USE SIGNAL ;
    PORT
      LAYER M5 ;
        RECT  55.2 0 55.224 0.192 ;
    END
  END o_d[308]
  PIN o_d[309]
    DIRECTION OUTPUT ;
    USE SIGNAL ;
    PORT
      LAYER M5 ;
        RECT  55.344 0 55.368 0.192 ;
    END
  END o_d[309]
  PIN o_d[30]
    DIRECTION OUTPUT ;
    USE SIGNAL ;
    PORT
      LAYER M5 ;
        RECT  9.312 0 9.336 0.192 ;
    END
  END o_d[30]
  PIN o_d[310]
    DIRECTION OUTPUT ;
    USE SIGNAL ;
    PORT
      LAYER M5 ;
        RECT  55.488 0 55.512 0.192 ;
    END
  END o_d[310]
  PIN o_d[311]
    DIRECTION OUTPUT ;
    USE SIGNAL ;
    PORT
      LAYER M5 ;
        RECT  55.632 0 55.656 0.192 ;
    END
  END o_d[311]
  PIN o_d[312]
    DIRECTION OUTPUT ;
    USE SIGNAL ;
    PORT
      LAYER M5 ;
        RECT  55.776 0 55.8 0.192 ;
    END
  END o_d[312]
  PIN o_d[313]
    DIRECTION OUTPUT ;
    USE SIGNAL ;
    PORT
      LAYER M5 ;
        RECT  55.92 0 55.944 0.192 ;
    END
  END o_d[313]
  PIN o_d[314]
    DIRECTION OUTPUT ;
    USE SIGNAL ;
    PORT
      LAYER M5 ;
        RECT  56.064 0 56.088 0.192 ;
    END
  END o_d[314]
  PIN o_d[315]
    DIRECTION OUTPUT ;
    USE SIGNAL ;
    PORT
      LAYER M5 ;
        RECT  56.208 0 56.232 0.192 ;
    END
  END o_d[315]
  PIN o_d[316]
    DIRECTION OUTPUT ;
    USE SIGNAL ;
    PORT
      LAYER M5 ;
        RECT  56.352 0 56.376 0.192 ;
    END
  END o_d[316]
  PIN o_d[317]
    DIRECTION OUTPUT ;
    USE SIGNAL ;
    PORT
      LAYER M5 ;
        RECT  56.496 0 56.52 0.192 ;
    END
  END o_d[317]
  PIN o_d[318]
    DIRECTION OUTPUT ;
    USE SIGNAL ;
    PORT
      LAYER M5 ;
        RECT  56.64 0 56.664 0.192 ;
    END
  END o_d[318]
  PIN o_d[319]
    DIRECTION OUTPUT ;
    USE SIGNAL ;
    PORT
      LAYER M5 ;
        RECT  56.784 0 56.808 0.192 ;
    END
  END o_d[319]
  PIN o_d[31]
    DIRECTION OUTPUT ;
    USE SIGNAL ;
    PORT
      LAYER M5 ;
        RECT  9.456 0 9.48 0.192 ;
    END
  END o_d[31]
  PIN o_d[320]
    DIRECTION OUTPUT ;
    USE SIGNAL ;
    PORT
      LAYER M5 ;
        RECT  56.928 0 56.952 0.192 ;
    END
  END o_d[320]
  PIN o_d[321]
    DIRECTION OUTPUT ;
    USE SIGNAL ;
    PORT
      LAYER M5 ;
        RECT  57.072 0 57.096 0.192 ;
    END
  END o_d[321]
  PIN o_d[322]
    DIRECTION OUTPUT ;
    USE SIGNAL ;
    PORT
      LAYER M5 ;
        RECT  57.216 0 57.24 0.192 ;
    END
  END o_d[322]
  PIN o_d[323]
    DIRECTION OUTPUT ;
    USE SIGNAL ;
    PORT
      LAYER M5 ;
        RECT  57.36 0 57.384 0.192 ;
    END
  END o_d[323]
  PIN o_d[324]
    DIRECTION OUTPUT ;
    USE SIGNAL ;
    PORT
      LAYER M5 ;
        RECT  57.504 0 57.528 0.192 ;
    END
  END o_d[324]
  PIN o_d[325]
    DIRECTION OUTPUT ;
    USE SIGNAL ;
    PORT
      LAYER M5 ;
        RECT  57.792 0 57.816 0.192 ;
    END
  END o_d[325]
  PIN o_d[326]
    DIRECTION OUTPUT ;
    USE SIGNAL ;
    PORT
      LAYER M5 ;
        RECT  57.936 0 57.96 0.192 ;
    END
  END o_d[326]
  PIN o_d[327]
    DIRECTION OUTPUT ;
    USE SIGNAL ;
    PORT
      LAYER M5 ;
        RECT  58.08 0 58.104 0.192 ;
    END
  END o_d[327]
  PIN o_d[328]
    DIRECTION OUTPUT ;
    USE SIGNAL ;
    PORT
      LAYER M5 ;
        RECT  58.224 0 58.248 0.192 ;
    END
  END o_d[328]
  PIN o_d[329]
    DIRECTION OUTPUT ;
    USE SIGNAL ;
    PORT
      LAYER M5 ;
        RECT  58.368 0 58.392 0.192 ;
    END
  END o_d[329]
  PIN o_d[32]
    DIRECTION OUTPUT ;
    USE SIGNAL ;
    PORT
      LAYER M5 ;
        RECT  9.6 0 9.624 0.192 ;
    END
  END o_d[32]
  PIN o_d[330]
    DIRECTION OUTPUT ;
    USE SIGNAL ;
    PORT
      LAYER M5 ;
        RECT  58.512 0 58.536 0.192 ;
    END
  END o_d[330]
  PIN o_d[331]
    DIRECTION OUTPUT ;
    USE SIGNAL ;
    PORT
      LAYER M5 ;
        RECT  58.656 0 58.68 0.192 ;
    END
  END o_d[331]
  PIN o_d[332]
    DIRECTION OUTPUT ;
    USE SIGNAL ;
    PORT
      LAYER M5 ;
        RECT  58.8 0 58.824 0.192 ;
    END
  END o_d[332]
  PIN o_d[333]
    DIRECTION OUTPUT ;
    USE SIGNAL ;
    PORT
      LAYER M5 ;
        RECT  58.944 0 58.968 0.192 ;
    END
  END o_d[333]
  PIN o_d[334]
    DIRECTION OUTPUT ;
    USE SIGNAL ;
    PORT
      LAYER M5 ;
        RECT  59.088 0 59.112 0.192 ;
    END
  END o_d[334]
  PIN o_d[335]
    DIRECTION OUTPUT ;
    USE SIGNAL ;
    PORT
      LAYER M5 ;
        RECT  59.232 0 59.256 0.192 ;
    END
  END o_d[335]
  PIN o_d[336]
    DIRECTION OUTPUT ;
    USE SIGNAL ;
    PORT
      LAYER M5 ;
        RECT  59.376 0 59.4 0.192 ;
    END
  END o_d[336]
  PIN o_d[337]
    DIRECTION OUTPUT ;
    USE SIGNAL ;
    PORT
      LAYER M5 ;
        RECT  59.52 0 59.544 0.192 ;
    END
  END o_d[337]
  PIN o_d[338]
    DIRECTION OUTPUT ;
    USE SIGNAL ;
    PORT
      LAYER M5 ;
        RECT  60.144 0 60.168 0.192 ;
    END
  END o_d[338]
  PIN o_d[339]
    DIRECTION OUTPUT ;
    USE SIGNAL ;
    PORT
      LAYER M5 ;
        RECT  60.288 0 60.312 0.192 ;
    END
  END o_d[339]
  PIN o_d[33]
    DIRECTION OUTPUT ;
    USE SIGNAL ;
    PORT
      LAYER M5 ;
        RECT  9.744 0 9.768 0.192 ;
    END
  END o_d[33]
  PIN o_d[340]
    DIRECTION OUTPUT ;
    USE SIGNAL ;
    PORT
      LAYER M5 ;
        RECT  60.432 0 60.456 0.192 ;
    END
  END o_d[340]
  PIN o_d[341]
    DIRECTION OUTPUT ;
    USE SIGNAL ;
    PORT
      LAYER M5 ;
        RECT  60.576 0 60.6 0.192 ;
    END
  END o_d[341]
  PIN o_d[342]
    DIRECTION OUTPUT ;
    USE SIGNAL ;
    PORT
      LAYER M5 ;
        RECT  60.72 0 60.744 0.192 ;
    END
  END o_d[342]
  PIN o_d[343]
    DIRECTION OUTPUT ;
    USE SIGNAL ;
    PORT
      LAYER M5 ;
        RECT  60.864 0 60.888 0.192 ;
    END
  END o_d[343]
  PIN o_d[344]
    DIRECTION OUTPUT ;
    USE SIGNAL ;
    PORT
      LAYER M5 ;
        RECT  61.008 0 61.032 0.192 ;
    END
  END o_d[344]
  PIN o_d[345]
    DIRECTION OUTPUT ;
    USE SIGNAL ;
    PORT
      LAYER M5 ;
        RECT  61.152 0 61.176 0.192 ;
    END
  END o_d[345]
  PIN o_d[346]
    DIRECTION OUTPUT ;
    USE SIGNAL ;
    PORT
      LAYER M5 ;
        RECT  61.296 0 61.32 0.192 ;
    END
  END o_d[346]
  PIN o_d[347]
    DIRECTION OUTPUT ;
    USE SIGNAL ;
    PORT
      LAYER M5 ;
        RECT  61.44 0 61.464 0.192 ;
    END
  END o_d[347]
  PIN o_d[348]
    DIRECTION OUTPUT ;
    USE SIGNAL ;
    PORT
      LAYER M5 ;
        RECT  61.584 0 61.608 0.192 ;
    END
  END o_d[348]
  PIN o_d[349]
    DIRECTION OUTPUT ;
    USE SIGNAL ;
    PORT
      LAYER M5 ;
        RECT  61.728 0 61.752 0.192 ;
    END
  END o_d[349]
  PIN o_d[34]
    DIRECTION OUTPUT ;
    USE SIGNAL ;
    PORT
      LAYER M5 ;
        RECT  9.888 0 9.912 0.192 ;
    END
  END o_d[34]
  PIN o_d[350]
    DIRECTION OUTPUT ;
    USE SIGNAL ;
    PORT
      LAYER M5 ;
        RECT  61.872 0 61.896 0.192 ;
    END
  END o_d[350]
  PIN o_d[351]
    DIRECTION OUTPUT ;
    USE SIGNAL ;
    PORT
      LAYER M5 ;
        RECT  62.016 0 62.04 0.192 ;
    END
  END o_d[351]
  PIN o_d[352]
    DIRECTION OUTPUT ;
    USE SIGNAL ;
    PORT
      LAYER M5 ;
        RECT  62.16 0 62.184 0.192 ;
    END
  END o_d[352]
  PIN o_d[353]
    DIRECTION OUTPUT ;
    USE SIGNAL ;
    PORT
      LAYER M5 ;
        RECT  62.304 0 62.328 0.192 ;
    END
  END o_d[353]
  PIN o_d[354]
    DIRECTION OUTPUT ;
    USE SIGNAL ;
    PORT
      LAYER M5 ;
        RECT  62.448 0 62.472 0.192 ;
    END
  END o_d[354]
  PIN o_d[355]
    DIRECTION OUTPUT ;
    USE SIGNAL ;
    PORT
      LAYER M5 ;
        RECT  62.592 0 62.616 0.192 ;
    END
  END o_d[355]
  PIN o_d[356]
    DIRECTION OUTPUT ;
    USE SIGNAL ;
    PORT
      LAYER M5 ;
        RECT  62.88 0 62.904 0.192 ;
    END
  END o_d[356]
  PIN o_d[357]
    DIRECTION OUTPUT ;
    USE SIGNAL ;
    PORT
      LAYER M5 ;
        RECT  63.024 0 63.048 0.192 ;
    END
  END o_d[357]
  PIN o_d[358]
    DIRECTION OUTPUT ;
    USE SIGNAL ;
    PORT
      LAYER M5 ;
        RECT  63.168 0 63.192 0.192 ;
    END
  END o_d[358]
  PIN o_d[359]
    DIRECTION OUTPUT ;
    USE SIGNAL ;
    PORT
      LAYER M5 ;
        RECT  63.312 0 63.336 0.192 ;
    END
  END o_d[359]
  PIN o_d[35]
    DIRECTION OUTPUT ;
    USE SIGNAL ;
    PORT
      LAYER M5 ;
        RECT  10.032 0 10.056 0.192 ;
    END
  END o_d[35]
  PIN o_d[360]
    DIRECTION OUTPUT ;
    USE SIGNAL ;
    PORT
      LAYER M5 ;
        RECT  63.456 0 63.48 0.192 ;
    END
  END o_d[360]
  PIN o_d[361]
    DIRECTION OUTPUT ;
    USE SIGNAL ;
    PORT
      LAYER M5 ;
        RECT  63.6 0 63.624 0.192 ;
    END
  END o_d[361]
  PIN o_d[362]
    DIRECTION OUTPUT ;
    USE SIGNAL ;
    PORT
      LAYER M5 ;
        RECT  63.744 0 63.768 0.192 ;
    END
  END o_d[362]
  PIN o_d[363]
    DIRECTION OUTPUT ;
    USE SIGNAL ;
    PORT
      LAYER M5 ;
        RECT  63.888 0 63.912 0.192 ;
    END
  END o_d[363]
  PIN o_d[364]
    DIRECTION OUTPUT ;
    USE SIGNAL ;
    PORT
      LAYER M5 ;
        RECT  64.032 0 64.056 0.192 ;
    END
  END o_d[364]
  PIN o_d[365]
    DIRECTION OUTPUT ;
    USE SIGNAL ;
    PORT
      LAYER M5 ;
        RECT  64.176 0 64.2 0.192 ;
    END
  END o_d[365]
  PIN o_d[366]
    DIRECTION OUTPUT ;
    USE SIGNAL ;
    PORT
      LAYER M5 ;
        RECT  64.32 0 64.344 0.192 ;
    END
  END o_d[366]
  PIN o_d[367]
    DIRECTION OUTPUT ;
    USE SIGNAL ;
    PORT
      LAYER M5 ;
        RECT  64.464 0 64.488 0.192 ;
    END
  END o_d[367]
  PIN o_d[368]
    DIRECTION OUTPUT ;
    USE SIGNAL ;
    PORT
      LAYER M5 ;
        RECT  64.608 0 64.632 0.192 ;
    END
  END o_d[368]
  PIN o_d[369]
    DIRECTION OUTPUT ;
    USE SIGNAL ;
    PORT
      LAYER M5 ;
        RECT  64.752 0 64.776 0.192 ;
    END
  END o_d[369]
  PIN o_d[36]
    DIRECTION OUTPUT ;
    USE SIGNAL ;
    PORT
      LAYER M5 ;
        RECT  10.176 0 10.2 0.192 ;
    END
  END o_d[36]
  PIN o_d[370]
    DIRECTION OUTPUT ;
    USE SIGNAL ;
    PORT
      LAYER M5 ;
        RECT  64.896 0 64.92 0.192 ;
    END
  END o_d[370]
  PIN o_d[371]
    DIRECTION OUTPUT ;
    USE SIGNAL ;
    PORT
      LAYER M5 ;
        RECT  65.568 0 65.592 0.192 ;
    END
  END o_d[371]
  PIN o_d[372]
    DIRECTION OUTPUT ;
    USE SIGNAL ;
    PORT
      LAYER M5 ;
        RECT  65.712 0 65.736 0.192 ;
    END
  END o_d[372]
  PIN o_d[373]
    DIRECTION OUTPUT ;
    USE SIGNAL ;
    PORT
      LAYER M5 ;
        RECT  65.856 0 65.88 0.192 ;
    END
  END o_d[373]
  PIN o_d[374]
    DIRECTION OUTPUT ;
    USE SIGNAL ;
    PORT
      LAYER M5 ;
        RECT  66 0 66.024 0.192 ;
    END
  END o_d[374]
  PIN o_d[375]
    DIRECTION OUTPUT ;
    USE SIGNAL ;
    PORT
      LAYER M5 ;
        RECT  66.144 0 66.168 0.192 ;
    END
  END o_d[375]
  PIN o_d[376]
    DIRECTION OUTPUT ;
    USE SIGNAL ;
    PORT
      LAYER M5 ;
        RECT  66.288 0 66.312 0.192 ;
    END
  END o_d[376]
  PIN o_d[377]
    DIRECTION OUTPUT ;
    USE SIGNAL ;
    PORT
      LAYER M5 ;
        RECT  66.432 0 66.456 0.192 ;
    END
  END o_d[377]
  PIN o_d[378]
    DIRECTION OUTPUT ;
    USE SIGNAL ;
    PORT
      LAYER M5 ;
        RECT  66.576 0 66.6 0.192 ;
    END
  END o_d[378]
  PIN o_d[379]
    DIRECTION OUTPUT ;
    USE SIGNAL ;
    PORT
      LAYER M5 ;
        RECT  66.72 0 66.744 0.192 ;
    END
  END o_d[379]
  PIN o_d[37]
    DIRECTION OUTPUT ;
    USE SIGNAL ;
    PORT
      LAYER M5 ;
        RECT  10.32 0 10.344 0.192 ;
    END
  END o_d[37]
  PIN o_d[380]
    DIRECTION OUTPUT ;
    USE SIGNAL ;
    PORT
      LAYER M5 ;
        RECT  66.864 0 66.888 0.192 ;
    END
  END o_d[380]
  PIN o_d[381]
    DIRECTION OUTPUT ;
    USE SIGNAL ;
    PORT
      LAYER M5 ;
        RECT  67.008 0 67.032 0.192 ;
    END
  END o_d[381]
  PIN o_d[382]
    DIRECTION OUTPUT ;
    USE SIGNAL ;
    PORT
      LAYER M5 ;
        RECT  67.152 0 67.176 0.192 ;
    END
  END o_d[382]
  PIN o_d[383]
    DIRECTION OUTPUT ;
    USE SIGNAL ;
    PORT
      LAYER M5 ;
        RECT  67.296 0 67.32 0.192 ;
    END
  END o_d[383]
  PIN o_d[384]
    DIRECTION OUTPUT ;
    USE SIGNAL ;
    PORT
      LAYER M5 ;
        RECT  67.44 0 67.464 0.192 ;
    END
  END o_d[384]
  PIN o_d[385]
    DIRECTION OUTPUT ;
    USE SIGNAL ;
    PORT
      LAYER M5 ;
        RECT  67.584 0 67.608 0.192 ;
    END
  END o_d[385]
  PIN o_d[386]
    DIRECTION OUTPUT ;
    USE SIGNAL ;
    PORT
      LAYER M5 ;
        RECT  67.728 0 67.752 0.192 ;
    END
  END o_d[386]
  PIN o_d[387]
    DIRECTION OUTPUT ;
    USE SIGNAL ;
    PORT
      LAYER M5 ;
        RECT  68.016 0 68.04 0.192 ;
    END
  END o_d[387]
  PIN o_d[388]
    DIRECTION OUTPUT ;
    USE SIGNAL ;
    PORT
      LAYER M5 ;
        RECT  68.16 0 68.184 0.192 ;
    END
  END o_d[388]
  PIN o_d[389]
    DIRECTION OUTPUT ;
    USE SIGNAL ;
    PORT
      LAYER M5 ;
        RECT  68.304 0 68.328 0.192 ;
    END
  END o_d[389]
  PIN o_d[38]
    DIRECTION OUTPUT ;
    USE SIGNAL ;
    PORT
      LAYER M5 ;
        RECT  10.464 0 10.488 0.192 ;
    END
  END o_d[38]
  PIN o_d[390]
    DIRECTION OUTPUT ;
    USE SIGNAL ;
    PORT
      LAYER M5 ;
        RECT  68.448 0 68.472 0.192 ;
    END
  END o_d[390]
  PIN o_d[391]
    DIRECTION OUTPUT ;
    USE SIGNAL ;
    PORT
      LAYER M5 ;
        RECT  68.592 0 68.616 0.192 ;
    END
  END o_d[391]
  PIN o_d[392]
    DIRECTION OUTPUT ;
    USE SIGNAL ;
    PORT
      LAYER M5 ;
        RECT  68.736 0 68.76 0.192 ;
    END
  END o_d[392]
  PIN o_d[393]
    DIRECTION OUTPUT ;
    USE SIGNAL ;
    PORT
      LAYER M5 ;
        RECT  68.88 0 68.904 0.192 ;
    END
  END o_d[393]
  PIN o_d[394]
    DIRECTION OUTPUT ;
    USE SIGNAL ;
    PORT
      LAYER M5 ;
        RECT  69.024 0 69.048 0.192 ;
    END
  END o_d[394]
  PIN o_d[395]
    DIRECTION OUTPUT ;
    USE SIGNAL ;
    PORT
      LAYER M5 ;
        RECT  69.168 0 69.192 0.192 ;
    END
  END o_d[395]
  PIN o_d[396]
    DIRECTION OUTPUT ;
    USE SIGNAL ;
    PORT
      LAYER M5 ;
        RECT  69.312 0 69.336 0.192 ;
    END
  END o_d[396]
  PIN o_d[397]
    DIRECTION OUTPUT ;
    USE SIGNAL ;
    PORT
      LAYER M5 ;
        RECT  69.456 0 69.48 0.192 ;
    END
  END o_d[397]
  PIN o_d[398]
    DIRECTION OUTPUT ;
    USE SIGNAL ;
    PORT
      LAYER M5 ;
        RECT  69.6 0 69.624 0.192 ;
    END
  END o_d[398]
  PIN o_d[399]
    DIRECTION OUTPUT ;
    USE SIGNAL ;
    PORT
      LAYER M5 ;
        RECT  69.744 0 69.768 0.192 ;
    END
  END o_d[399]
  PIN o_d[39]
    DIRECTION OUTPUT ;
    USE SIGNAL ;
    PORT
      LAYER M5 ;
        RECT  10.608 0 10.632 0.192 ;
    END
  END o_d[39]
  PIN o_d[3]
    DIRECTION OUTPUT ;
    USE SIGNAL ;
    PORT
      LAYER M5 ;
        RECT  4.752 0 4.776 0.192 ;
    END
  END o_d[3]
  PIN o_d[400]
    DIRECTION OUTPUT ;
    USE SIGNAL ;
    PORT
      LAYER M5 ;
        RECT  69.888 0 69.912 0.192 ;
    END
  END o_d[400]
  PIN o_d[401]
    DIRECTION OUTPUT ;
    USE SIGNAL ;
    PORT
      LAYER M5 ;
        RECT  70.032 0 70.056 0.192 ;
    END
  END o_d[401]
  PIN o_d[402]
    DIRECTION OUTPUT ;
    USE SIGNAL ;
    PORT
      LAYER M5 ;
        RECT  70.176 0 70.2 0.192 ;
    END
  END o_d[402]
  PIN o_d[403]
    DIRECTION OUTPUT ;
    USE SIGNAL ;
    PORT
      LAYER M5 ;
        RECT  70.32 0 70.344 0.192 ;
    END
  END o_d[403]
  PIN o_d[404]
    DIRECTION OUTPUT ;
    USE SIGNAL ;
    PORT
      LAYER M5 ;
        RECT  70.944 0 70.968 0.192 ;
    END
  END o_d[404]
  PIN o_d[405]
    DIRECTION OUTPUT ;
    USE SIGNAL ;
    PORT
      LAYER M5 ;
        RECT  71.088 0 71.112 0.192 ;
    END
  END o_d[405]
  PIN o_d[406]
    DIRECTION OUTPUT ;
    USE SIGNAL ;
    PORT
      LAYER M5 ;
        RECT  71.232 0 71.256 0.192 ;
    END
  END o_d[406]
  PIN o_d[407]
    DIRECTION OUTPUT ;
    USE SIGNAL ;
    PORT
      LAYER M5 ;
        RECT  71.376 0 71.4 0.192 ;
    END
  END o_d[407]
  PIN o_d[408]
    DIRECTION OUTPUT ;
    USE SIGNAL ;
    PORT
      LAYER M5 ;
        RECT  71.52 0 71.544 0.192 ;
    END
  END o_d[408]
  PIN o_d[409]
    DIRECTION OUTPUT ;
    USE SIGNAL ;
    PORT
      LAYER M5 ;
        RECT  71.664 0 71.688 0.192 ;
    END
  END o_d[409]
  PIN o_d[40]
    DIRECTION OUTPUT ;
    USE SIGNAL ;
    PORT
      LAYER M5 ;
        RECT  10.752 0 10.776 0.192 ;
    END
  END o_d[40]
  PIN o_d[410]
    DIRECTION OUTPUT ;
    USE SIGNAL ;
    PORT
      LAYER M5 ;
        RECT  71.808 0 71.832 0.192 ;
    END
  END o_d[410]
  PIN o_d[411]
    DIRECTION OUTPUT ;
    USE SIGNAL ;
    PORT
      LAYER M5 ;
        RECT  71.952 0 71.976 0.192 ;
    END
  END o_d[411]
  PIN o_d[412]
    DIRECTION OUTPUT ;
    USE SIGNAL ;
    PORT
      LAYER M5 ;
        RECT  72.096 0 72.12 0.192 ;
    END
  END o_d[412]
  PIN o_d[413]
    DIRECTION OUTPUT ;
    USE SIGNAL ;
    PORT
      LAYER M5 ;
        RECT  72.24 0 72.264 0.192 ;
    END
  END o_d[413]
  PIN o_d[414]
    DIRECTION OUTPUT ;
    USE SIGNAL ;
    PORT
      LAYER M5 ;
        RECT  72.384 0 72.408 0.192 ;
    END
  END o_d[414]
  PIN o_d[415]
    DIRECTION OUTPUT ;
    USE SIGNAL ;
    PORT
      LAYER M5 ;
        RECT  72.528 0 72.552 0.192 ;
    END
  END o_d[415]
  PIN o_d[416]
    DIRECTION OUTPUT ;
    USE SIGNAL ;
    PORT
      LAYER M5 ;
        RECT  72.672 0 72.696 0.192 ;
    END
  END o_d[416]
  PIN o_d[417]
    DIRECTION OUTPUT ;
    USE SIGNAL ;
    PORT
      LAYER M5 ;
        RECT  72.816 0 72.84 0.192 ;
    END
  END o_d[417]
  PIN o_d[418]
    DIRECTION OUTPUT ;
    USE SIGNAL ;
    PORT
      LAYER M5 ;
        RECT  73.104 0 73.128 0.192 ;
    END
  END o_d[418]
  PIN o_d[419]
    DIRECTION OUTPUT ;
    USE SIGNAL ;
    PORT
      LAYER M5 ;
        RECT  73.248 0 73.272 0.192 ;
    END
  END o_d[419]
  PIN o_d[41]
    DIRECTION OUTPUT ;
    USE SIGNAL ;
    PORT
      LAYER M5 ;
        RECT  10.896 0 10.92 0.192 ;
    END
  END o_d[41]
  PIN o_d[420]
    DIRECTION OUTPUT ;
    USE SIGNAL ;
    PORT
      LAYER M5 ;
        RECT  73.392 0 73.416 0.192 ;
    END
  END o_d[420]
  PIN o_d[421]
    DIRECTION OUTPUT ;
    USE SIGNAL ;
    PORT
      LAYER M5 ;
        RECT  73.536 0 73.56 0.192 ;
    END
  END o_d[421]
  PIN o_d[422]
    DIRECTION OUTPUT ;
    USE SIGNAL ;
    PORT
      LAYER M5 ;
        RECT  73.68 0 73.704 0.192 ;
    END
  END o_d[422]
  PIN o_d[423]
    DIRECTION OUTPUT ;
    USE SIGNAL ;
    PORT
      LAYER M5 ;
        RECT  73.824 0 73.848 0.192 ;
    END
  END o_d[423]
  PIN o_d[424]
    DIRECTION OUTPUT ;
    USE SIGNAL ;
    PORT
      LAYER M5 ;
        RECT  73.968 0 73.992 0.192 ;
    END
  END o_d[424]
  PIN o_d[425]
    DIRECTION OUTPUT ;
    USE SIGNAL ;
    PORT
      LAYER M5 ;
        RECT  74.112 0 74.136 0.192 ;
    END
  END o_d[425]
  PIN o_d[426]
    DIRECTION OUTPUT ;
    USE SIGNAL ;
    PORT
      LAYER M5 ;
        RECT  74.256 0 74.28 0.192 ;
    END
  END o_d[426]
  PIN o_d[427]
    DIRECTION OUTPUT ;
    USE SIGNAL ;
    PORT
      LAYER M5 ;
        RECT  74.4 0 74.424 0.192 ;
    END
  END o_d[427]
  PIN o_d[428]
    DIRECTION OUTPUT ;
    USE SIGNAL ;
    PORT
      LAYER M5 ;
        RECT  74.544 0 74.568 0.192 ;
    END
  END o_d[428]
  PIN o_d[429]
    DIRECTION OUTPUT ;
    USE SIGNAL ;
    PORT
      LAYER M5 ;
        RECT  74.688 0 74.712 0.192 ;
    END
  END o_d[429]
  PIN o_d[42]
    DIRECTION OUTPUT ;
    USE SIGNAL ;
    PORT
      LAYER M5 ;
        RECT  11.568 0 11.592 0.192 ;
    END
  END o_d[42]
  PIN o_d[430]
    DIRECTION OUTPUT ;
    USE SIGNAL ;
    PORT
      LAYER M5 ;
        RECT  74.832 0 74.856 0.192 ;
    END
  END o_d[430]
  PIN o_d[431]
    DIRECTION OUTPUT ;
    USE SIGNAL ;
    PORT
      LAYER M5 ;
        RECT  74.976 0 75 0.192 ;
    END
  END o_d[431]
  PIN o_d[432]
    DIRECTION OUTPUT ;
    USE SIGNAL ;
    PORT
      LAYER M5 ;
        RECT  75.12 0 75.144 0.192 ;
    END
  END o_d[432]
  PIN o_d[433]
    DIRECTION OUTPUT ;
    USE SIGNAL ;
    PORT
      LAYER M5 ;
        RECT  75.264 0 75.288 0.192 ;
    END
  END o_d[433]
  PIN o_d[434]
    DIRECTION OUTPUT ;
    USE SIGNAL ;
    PORT
      LAYER M5 ;
        RECT  75.408 0 75.432 0.192 ;
    END
  END o_d[434]
  PIN o_d[435]
    DIRECTION OUTPUT ;
    USE SIGNAL ;
    PORT
      LAYER M5 ;
        RECT  75.552 0 75.576 0.192 ;
    END
  END o_d[435]
  PIN o_d[436]
    DIRECTION OUTPUT ;
    USE SIGNAL ;
    PORT
      LAYER M5 ;
        RECT  75.696 0 75.72 0.192 ;
    END
  END o_d[436]
  PIN o_d[437]
    DIRECTION OUTPUT ;
    USE SIGNAL ;
    PORT
      LAYER M5 ;
        RECT  76.368 0 76.392 0.192 ;
    END
  END o_d[437]
  PIN o_d[438]
    DIRECTION OUTPUT ;
    USE SIGNAL ;
    PORT
      LAYER M5 ;
        RECT  76.512 0 76.536 0.192 ;
    END
  END o_d[438]
  PIN o_d[439]
    DIRECTION OUTPUT ;
    USE SIGNAL ;
    PORT
      LAYER M5 ;
        RECT  76.656 0 76.68 0.192 ;
    END
  END o_d[439]
  PIN o_d[43]
    DIRECTION OUTPUT ;
    USE SIGNAL ;
    PORT
      LAYER M5 ;
        RECT  11.712 0 11.736 0.192 ;
    END
  END o_d[43]
  PIN o_d[440]
    DIRECTION OUTPUT ;
    USE SIGNAL ;
    PORT
      LAYER M5 ;
        RECT  76.8 0 76.824 0.192 ;
    END
  END o_d[440]
  PIN o_d[441]
    DIRECTION OUTPUT ;
    USE SIGNAL ;
    PORT
      LAYER M5 ;
        RECT  76.944 0 76.968 0.192 ;
    END
  END o_d[441]
  PIN o_d[442]
    DIRECTION OUTPUT ;
    USE SIGNAL ;
    PORT
      LAYER M5 ;
        RECT  77.088 0 77.112 0.192 ;
    END
  END o_d[442]
  PIN o_d[443]
    DIRECTION OUTPUT ;
    USE SIGNAL ;
    PORT
      LAYER M5 ;
        RECT  77.232 0 77.256 0.192 ;
    END
  END o_d[443]
  PIN o_d[444]
    DIRECTION OUTPUT ;
    USE SIGNAL ;
    PORT
      LAYER M5 ;
        RECT  77.376 0 77.4 0.192 ;
    END
  END o_d[444]
  PIN o_d[445]
    DIRECTION OUTPUT ;
    USE SIGNAL ;
    PORT
      LAYER M5 ;
        RECT  77.52 0 77.544 0.192 ;
    END
  END o_d[445]
  PIN o_d[446]
    DIRECTION OUTPUT ;
    USE SIGNAL ;
    PORT
      LAYER M5 ;
        RECT  77.664 0 77.688 0.192 ;
    END
  END o_d[446]
  PIN o_d[447]
    DIRECTION OUTPUT ;
    USE SIGNAL ;
    PORT
      LAYER M5 ;
        RECT  77.808 0 77.832 0.192 ;
    END
  END o_d[447]
  PIN o_d[448]
    DIRECTION OUTPUT ;
    USE SIGNAL ;
    PORT
      LAYER M5 ;
        RECT  77.952 0 77.976 0.192 ;
    END
  END o_d[448]
  PIN o_d[449]
    DIRECTION OUTPUT ;
    USE SIGNAL ;
    PORT
      LAYER M5 ;
        RECT  78.24 0 78.264 0.192 ;
    END
  END o_d[449]
  PIN o_d[44]
    DIRECTION OUTPUT ;
    USE SIGNAL ;
    PORT
      LAYER M5 ;
        RECT  11.856 0 11.88 0.192 ;
    END
  END o_d[44]
  PIN o_d[450]
    DIRECTION OUTPUT ;
    USE SIGNAL ;
    PORT
      LAYER M5 ;
        RECT  78.384 0 78.408 0.192 ;
    END
  END o_d[450]
  PIN o_d[451]
    DIRECTION OUTPUT ;
    USE SIGNAL ;
    PORT
      LAYER M5 ;
        RECT  78.528 0 78.552 0.192 ;
    END
  END o_d[451]
  PIN o_d[452]
    DIRECTION OUTPUT ;
    USE SIGNAL ;
    PORT
      LAYER M5 ;
        RECT  78.672 0 78.696 0.192 ;
    END
  END o_d[452]
  PIN o_d[453]
    DIRECTION OUTPUT ;
    USE SIGNAL ;
    PORT
      LAYER M5 ;
        RECT  78.816 0 78.84 0.192 ;
    END
  END o_d[453]
  PIN o_d[454]
    DIRECTION OUTPUT ;
    USE SIGNAL ;
    PORT
      LAYER M5 ;
        RECT  78.96 0 78.984 0.192 ;
    END
  END o_d[454]
  PIN o_d[455]
    DIRECTION OUTPUT ;
    USE SIGNAL ;
    PORT
      LAYER M5 ;
        RECT  79.104 0 79.128 0.192 ;
    END
  END o_d[455]
  PIN o_d[456]
    DIRECTION OUTPUT ;
    USE SIGNAL ;
    PORT
      LAYER M5 ;
        RECT  79.248 0 79.272 0.192 ;
    END
  END o_d[456]
  PIN o_d[457]
    DIRECTION OUTPUT ;
    USE SIGNAL ;
    PORT
      LAYER M5 ;
        RECT  79.392 0 79.416 0.192 ;
    END
  END o_d[457]
  PIN o_d[458]
    DIRECTION OUTPUT ;
    USE SIGNAL ;
    PORT
      LAYER M5 ;
        RECT  79.536 0 79.56 0.192 ;
    END
  END o_d[458]
  PIN o_d[459]
    DIRECTION OUTPUT ;
    USE SIGNAL ;
    PORT
      LAYER M5 ;
        RECT  79.68 0 79.704 0.192 ;
    END
  END o_d[459]
  PIN o_d[45]
    DIRECTION OUTPUT ;
    USE SIGNAL ;
    PORT
      LAYER M5 ;
        RECT  12 0 12.024 0.192 ;
    END
  END o_d[45]
  PIN o_d[460]
    DIRECTION OUTPUT ;
    USE SIGNAL ;
    PORT
      LAYER M5 ;
        RECT  79.824 0 79.848 0.192 ;
    END
  END o_d[460]
  PIN o_d[461]
    DIRECTION OUTPUT ;
    USE SIGNAL ;
    PORT
      LAYER M5 ;
        RECT  79.968 0 79.992 0.192 ;
    END
  END o_d[461]
  PIN o_d[462]
    DIRECTION OUTPUT ;
    USE SIGNAL ;
    PORT
      LAYER M5 ;
        RECT  80.112 0 80.136 0.192 ;
    END
  END o_d[462]
  PIN o_d[463]
    DIRECTION OUTPUT ;
    USE SIGNAL ;
    PORT
      LAYER M5 ;
        RECT  80.256 0 80.28 0.192 ;
    END
  END o_d[463]
  PIN o_d[464]
    DIRECTION OUTPUT ;
    USE SIGNAL ;
    PORT
      LAYER M5 ;
        RECT  80.4 0 80.424 0.192 ;
    END
  END o_d[464]
  PIN o_d[465]
    DIRECTION OUTPUT ;
    USE SIGNAL ;
    PORT
      LAYER M5 ;
        RECT  80.544 0 80.568 0.192 ;
    END
  END o_d[465]
  PIN o_d[466]
    DIRECTION OUTPUT ;
    USE SIGNAL ;
    PORT
      LAYER M5 ;
        RECT  80.688 0 80.712 0.192 ;
    END
  END o_d[466]
  PIN o_d[467]
    DIRECTION OUTPUT ;
    USE SIGNAL ;
    PORT
      LAYER M5 ;
        RECT  80.832 0 80.856 0.192 ;
    END
  END o_d[467]
  PIN o_d[468]
    DIRECTION OUTPUT ;
    USE SIGNAL ;
    PORT
      LAYER M5 ;
        RECT  80.976 0 81 0.192 ;
    END
  END o_d[468]
  PIN o_d[469]
    DIRECTION OUTPUT ;
    USE SIGNAL ;
    PORT
      LAYER M5 ;
        RECT  81.12 0 81.144 0.192 ;
    END
  END o_d[469]
  PIN o_d[46]
    DIRECTION OUTPUT ;
    USE SIGNAL ;
    PORT
      LAYER M5 ;
        RECT  12.288 0 12.312 0.192 ;
    END
  END o_d[46]
  PIN o_d[470]
    DIRECTION OUTPUT ;
    USE SIGNAL ;
    PORT
      LAYER M5 ;
        RECT  81.744 0 81.768 0.192 ;
    END
  END o_d[470]
  PIN o_d[471]
    DIRECTION OUTPUT ;
    USE SIGNAL ;
    PORT
      LAYER M5 ;
        RECT  81.888 0 81.912 0.192 ;
    END
  END o_d[471]
  PIN o_d[472]
    DIRECTION OUTPUT ;
    USE SIGNAL ;
    PORT
      LAYER M5 ;
        RECT  82.032 0 82.056 0.192 ;
    END
  END o_d[472]
  PIN o_d[473]
    DIRECTION OUTPUT ;
    USE SIGNAL ;
    PORT
      LAYER M5 ;
        RECT  82.176 0 82.2 0.192 ;
    END
  END o_d[473]
  PIN o_d[474]
    DIRECTION OUTPUT ;
    USE SIGNAL ;
    PORT
      LAYER M5 ;
        RECT  82.32 0 82.344 0.192 ;
    END
  END o_d[474]
  PIN o_d[475]
    DIRECTION OUTPUT ;
    USE SIGNAL ;
    PORT
      LAYER M5 ;
        RECT  82.464 0 82.488 0.192 ;
    END
  END o_d[475]
  PIN o_d[476]
    DIRECTION OUTPUT ;
    USE SIGNAL ;
    PORT
      LAYER M5 ;
        RECT  82.608 0 82.632 0.192 ;
    END
  END o_d[476]
  PIN o_d[477]
    DIRECTION OUTPUT ;
    USE SIGNAL ;
    PORT
      LAYER M5 ;
        RECT  82.752 0 82.776 0.192 ;
    END
  END o_d[477]
  PIN o_d[478]
    DIRECTION OUTPUT ;
    USE SIGNAL ;
    PORT
      LAYER M5 ;
        RECT  82.896 0 82.92 0.192 ;
    END
  END o_d[478]
  PIN o_d[479]
    DIRECTION OUTPUT ;
    USE SIGNAL ;
    PORT
      LAYER M5 ;
        RECT  83.04 0 83.064 0.192 ;
    END
  END o_d[479]
  PIN o_d[47]
    DIRECTION OUTPUT ;
    USE SIGNAL ;
    PORT
      LAYER M5 ;
        RECT  12.432 0 12.456 0.192 ;
    END
  END o_d[47]
  PIN o_d[480]
    DIRECTION OUTPUT ;
    USE SIGNAL ;
    PORT
      LAYER M5 ;
        RECT  83.328 0 83.352 0.192 ;
    END
  END o_d[480]
  PIN o_d[481]
    DIRECTION OUTPUT ;
    USE SIGNAL ;
    PORT
      LAYER M5 ;
        RECT  83.472 0 83.496 0.192 ;
    END
  END o_d[481]
  PIN o_d[482]
    DIRECTION OUTPUT ;
    USE SIGNAL ;
    PORT
      LAYER M5 ;
        RECT  83.616 0 83.64 0.192 ;
    END
  END o_d[482]
  PIN o_d[483]
    DIRECTION OUTPUT ;
    USE SIGNAL ;
    PORT
      LAYER M5 ;
        RECT  83.76 0 83.784 0.192 ;
    END
  END o_d[483]
  PIN o_d[484]
    DIRECTION OUTPUT ;
    USE SIGNAL ;
    PORT
      LAYER M5 ;
        RECT  83.904 0 83.928 0.192 ;
    END
  END o_d[484]
  PIN o_d[485]
    DIRECTION OUTPUT ;
    USE SIGNAL ;
    PORT
      LAYER M5 ;
        RECT  84.048 0 84.072 0.192 ;
    END
  END o_d[485]
  PIN o_d[486]
    DIRECTION OUTPUT ;
    USE SIGNAL ;
    PORT
      LAYER M5 ;
        RECT  84.192 0 84.216 0.192 ;
    END
  END o_d[486]
  PIN o_d[487]
    DIRECTION OUTPUT ;
    USE SIGNAL ;
    PORT
      LAYER M5 ;
        RECT  84.336 0 84.36 0.192 ;
    END
  END o_d[487]
  PIN o_d[488]
    DIRECTION OUTPUT ;
    USE SIGNAL ;
    PORT
      LAYER M5 ;
        RECT  84.48 0 84.504 0.192 ;
    END
  END o_d[488]
  PIN o_d[489]
    DIRECTION OUTPUT ;
    USE SIGNAL ;
    PORT
      LAYER M5 ;
        RECT  84.624 0 84.648 0.192 ;
    END
  END o_d[489]
  PIN o_d[48]
    DIRECTION OUTPUT ;
    USE SIGNAL ;
    PORT
      LAYER M5 ;
        RECT  12.576 0 12.6 0.192 ;
    END
  END o_d[48]
  PIN o_d[490]
    DIRECTION OUTPUT ;
    USE SIGNAL ;
    PORT
      LAYER M5 ;
        RECT  84.768 0 84.792 0.192 ;
    END
  END o_d[490]
  PIN o_d[491]
    DIRECTION OUTPUT ;
    USE SIGNAL ;
    PORT
      LAYER M5 ;
        RECT  84.912 0 84.936 0.192 ;
    END
  END o_d[491]
  PIN o_d[492]
    DIRECTION OUTPUT ;
    USE SIGNAL ;
    PORT
      LAYER M5 ;
        RECT  85.056 0 85.08 0.192 ;
    END
  END o_d[492]
  PIN o_d[493]
    DIRECTION OUTPUT ;
    USE SIGNAL ;
    PORT
      LAYER M5 ;
        RECT  85.2 0 85.224 0.192 ;
    END
  END o_d[493]
  PIN o_d[494]
    DIRECTION OUTPUT ;
    USE SIGNAL ;
    PORT
      LAYER M5 ;
        RECT  85.344 0 85.368 0.192 ;
    END
  END o_d[494]
  PIN o_d[495]
    DIRECTION OUTPUT ;
    USE SIGNAL ;
    PORT
      LAYER M5 ;
        RECT  85.488 0 85.512 0.192 ;
    END
  END o_d[495]
  PIN o_d[496]
    DIRECTION OUTPUT ;
    USE SIGNAL ;
    PORT
      LAYER M5 ;
        RECT  85.632 0 85.656 0.192 ;
    END
  END o_d[496]
  PIN o_d[497]
    DIRECTION OUTPUT ;
    USE SIGNAL ;
    PORT
      LAYER M5 ;
        RECT  85.776 0 85.8 0.192 ;
    END
  END o_d[497]
  PIN o_d[498]
    DIRECTION OUTPUT ;
    USE SIGNAL ;
    PORT
      LAYER M5 ;
        RECT  85.92 0 85.944 0.192 ;
    END
  END o_d[498]
  PIN o_d[499]
    DIRECTION OUTPUT ;
    USE SIGNAL ;
    PORT
      LAYER M5 ;
        RECT  86.064 0 86.088 0.192 ;
    END
  END o_d[499]
  PIN o_d[49]
    DIRECTION OUTPUT ;
    USE SIGNAL ;
    PORT
      LAYER M5 ;
        RECT  12.72 0 12.744 0.192 ;
    END
  END o_d[49]
  PIN o_d[4]
    DIRECTION OUTPUT ;
    USE SIGNAL ;
    PORT
      LAYER M5 ;
        RECT  4.896 0 4.92 0.192 ;
    END
  END o_d[4]
  PIN o_d[500]
    DIRECTION OUTPUT ;
    USE SIGNAL ;
    PORT
      LAYER M5 ;
        RECT  86.208 0 86.232 0.192 ;
    END
  END o_d[500]
  PIN o_d[501]
    DIRECTION OUTPUT ;
    USE SIGNAL ;
    PORT
      LAYER M5 ;
        RECT  86.352 0 86.376 0.192 ;
    END
  END o_d[501]
  PIN o_d[502]
    DIRECTION OUTPUT ;
    USE SIGNAL ;
    PORT
      LAYER M5 ;
        RECT  86.496 0 86.52 0.192 ;
    END
  END o_d[502]
  PIN o_d[503]
    DIRECTION OUTPUT ;
    USE SIGNAL ;
    PORT
      LAYER M5 ;
        RECT  87.168 0 87.192 0.192 ;
    END
  END o_d[503]
  PIN o_d[504]
    DIRECTION OUTPUT ;
    USE SIGNAL ;
    PORT
      LAYER M5 ;
        RECT  87.312 0 87.336 0.192 ;
    END
  END o_d[504]
  PIN o_d[505]
    DIRECTION OUTPUT ;
    USE SIGNAL ;
    PORT
      LAYER M5 ;
        RECT  87.456 0 87.48 0.192 ;
    END
  END o_d[505]
  PIN o_d[506]
    DIRECTION OUTPUT ;
    USE SIGNAL ;
    PORT
      LAYER M5 ;
        RECT  87.6 0 87.624 0.192 ;
    END
  END o_d[506]
  PIN o_d[507]
    DIRECTION OUTPUT ;
    USE SIGNAL ;
    PORT
      LAYER M5 ;
        RECT  87.744 0 87.768 0.192 ;
    END
  END o_d[507]
  PIN o_d[508]
    DIRECTION OUTPUT ;
    USE SIGNAL ;
    PORT
      LAYER M5 ;
        RECT  87.888 0 87.912 0.192 ;
    END
  END o_d[508]
  PIN o_d[509]
    DIRECTION OUTPUT ;
    USE SIGNAL ;
    PORT
      LAYER M5 ;
        RECT  88.032 0 88.056 0.192 ;
    END
  END o_d[509]
  PIN o_d[50]
    DIRECTION OUTPUT ;
    USE SIGNAL ;
    PORT
      LAYER M5 ;
        RECT  12.864 0 12.888 0.192 ;
    END
  END o_d[50]
  PIN o_d[510]
    DIRECTION OUTPUT ;
    USE SIGNAL ;
    PORT
      LAYER M5 ;
        RECT  88.176 0 88.2 0.192 ;
    END
  END o_d[510]
  PIN o_d[511]
    DIRECTION OUTPUT ;
    USE SIGNAL ;
    PORT
      LAYER M5 ;
        RECT  88.464 0 88.488 0.192 ;
    END
  END o_d[511]
  PIN o_d[51]
    DIRECTION OUTPUT ;
    USE SIGNAL ;
    PORT
      LAYER M5 ;
        RECT  13.008 0 13.032 0.192 ;
    END
  END o_d[51]
  PIN o_d[52]
    DIRECTION OUTPUT ;
    USE SIGNAL ;
    PORT
      LAYER M5 ;
        RECT  13.152 0 13.176 0.192 ;
    END
  END o_d[52]
  PIN o_d[53]
    DIRECTION OUTPUT ;
    USE SIGNAL ;
    PORT
      LAYER M5 ;
        RECT  13.296 0 13.32 0.192 ;
    END
  END o_d[53]
  PIN o_d[54]
    DIRECTION OUTPUT ;
    USE SIGNAL ;
    PORT
      LAYER M5 ;
        RECT  13.44 0 13.464 0.192 ;
    END
  END o_d[54]
  PIN o_d[55]
    DIRECTION OUTPUT ;
    USE SIGNAL ;
    PORT
      LAYER M5 ;
        RECT  13.584 0 13.608 0.192 ;
    END
  END o_d[55]
  PIN o_d[56]
    DIRECTION OUTPUT ;
    USE SIGNAL ;
    PORT
      LAYER M5 ;
        RECT  13.728 0 13.752 0.192 ;
    END
  END o_d[56]
  PIN o_d[57]
    DIRECTION OUTPUT ;
    USE SIGNAL ;
    PORT
      LAYER M5 ;
        RECT  13.872 0 13.896 0.192 ;
    END
  END o_d[57]
  PIN o_d[58]
    DIRECTION OUTPUT ;
    USE SIGNAL ;
    PORT
      LAYER M5 ;
        RECT  14.016 0 14.04 0.192 ;
    END
  END o_d[58]
  PIN o_d[59]
    DIRECTION OUTPUT ;
    USE SIGNAL ;
    PORT
      LAYER M5 ;
        RECT  14.16 0 14.184 0.192 ;
    END
  END o_d[59]
  PIN o_d[5]
    DIRECTION OUTPUT ;
    USE SIGNAL ;
    PORT
      LAYER M5 ;
        RECT  5.04 0 5.064 0.192 ;
    END
  END o_d[5]
  PIN o_d[60]
    DIRECTION OUTPUT ;
    USE SIGNAL ;
    PORT
      LAYER M5 ;
        RECT  14.304 0 14.328 0.192 ;
    END
  END o_d[60]
  PIN o_d[61]
    DIRECTION OUTPUT ;
    USE SIGNAL ;
    PORT
      LAYER M5 ;
        RECT  14.448 0 14.472 0.192 ;
    END
  END o_d[61]
  PIN o_d[62]
    DIRECTION OUTPUT ;
    USE SIGNAL ;
    PORT
      LAYER M5 ;
        RECT  14.592 0 14.616 0.192 ;
    END
  END o_d[62]
  PIN o_d[63]
    DIRECTION OUTPUT ;
    USE SIGNAL ;
    PORT
      LAYER M5 ;
        RECT  14.736 0 14.76 0.192 ;
    END
  END o_d[63]
  PIN o_d[64]
    DIRECTION OUTPUT ;
    USE SIGNAL ;
    PORT
      LAYER M5 ;
        RECT  14.88 0 14.904 0.192 ;
    END
  END o_d[64]
  PIN o_d[65]
    DIRECTION OUTPUT ;
    USE SIGNAL ;
    PORT
      LAYER M5 ;
        RECT  15.024 0 15.048 0.192 ;
    END
  END o_d[65]
  PIN o_d[66]
    DIRECTION OUTPUT ;
    USE SIGNAL ;
    PORT
      LAYER M5 ;
        RECT  15.168 0 15.192 0.192 ;
    END
  END o_d[66]
  PIN o_d[67]
    DIRECTION OUTPUT ;
    USE SIGNAL ;
    PORT
      LAYER M5 ;
        RECT  15.312 0 15.336 0.192 ;
    END
  END o_d[67]
  PIN o_d[68]
    DIRECTION OUTPUT ;
    USE SIGNAL ;
    PORT
      LAYER M5 ;
        RECT  15.456 0 15.48 0.192 ;
    END
  END o_d[68]
  PIN o_d[69]
    DIRECTION OUTPUT ;
    USE SIGNAL ;
    PORT
      LAYER M5 ;
        RECT  15.6 0 15.624 0.192 ;
    END
  END o_d[69]
  PIN o_d[6]
    DIRECTION OUTPUT ;
    USE SIGNAL ;
    PORT
      LAYER M5 ;
        RECT  5.184 0 5.208 0.192 ;
    END
  END o_d[6]
  PIN o_d[70]
    DIRECTION OUTPUT ;
    USE SIGNAL ;
    PORT
      LAYER M5 ;
        RECT  15.744 0 15.768 0.192 ;
    END
  END o_d[70]
  PIN o_d[71]
    DIRECTION OUTPUT ;
    USE SIGNAL ;
    PORT
      LAYER M5 ;
        RECT  15.888 0 15.912 0.192 ;
    END
  END o_d[71]
  PIN o_d[72]
    DIRECTION OUTPUT ;
    USE SIGNAL ;
    PORT
      LAYER M5 ;
        RECT  16.032 0 16.056 0.192 ;
    END
  END o_d[72]
  PIN o_d[73]
    DIRECTION OUTPUT ;
    USE SIGNAL ;
    PORT
      LAYER M5 ;
        RECT  16.176 0 16.2 0.192 ;
    END
  END o_d[73]
  PIN o_d[74]
    DIRECTION OUTPUT ;
    USE SIGNAL ;
    PORT
      LAYER M5 ;
        RECT  16.32 0 16.344 0.192 ;
    END
  END o_d[74]
  PIN o_d[75]
    DIRECTION OUTPUT ;
    USE SIGNAL ;
    PORT
      LAYER M5 ;
        RECT  16.944 0 16.968 0.192 ;
    END
  END o_d[75]
  PIN o_d[76]
    DIRECTION OUTPUT ;
    USE SIGNAL ;
    PORT
      LAYER M5 ;
        RECT  17.088 0 17.112 0.192 ;
    END
  END o_d[76]
  PIN o_d[77]
    DIRECTION OUTPUT ;
    USE SIGNAL ;
    PORT
      LAYER M5 ;
        RECT  17.376 0 17.4 0.192 ;
    END
  END o_d[77]
  PIN o_d[78]
    DIRECTION OUTPUT ;
    USE SIGNAL ;
    PORT
      LAYER M5 ;
        RECT  17.52 0 17.544 0.192 ;
    END
  END o_d[78]
  PIN o_d[79]
    DIRECTION OUTPUT ;
    USE SIGNAL ;
    PORT
      LAYER M5 ;
        RECT  17.664 0 17.688 0.192 ;
    END
  END o_d[79]
  PIN o_d[7]
    DIRECTION OUTPUT ;
    USE SIGNAL ;
    PORT
      LAYER M5 ;
        RECT  5.328 0 5.352 0.192 ;
    END
  END o_d[7]
  PIN o_d[80]
    DIRECTION OUTPUT ;
    USE SIGNAL ;
    PORT
      LAYER M5 ;
        RECT  17.808 0 17.832 0.192 ;
    END
  END o_d[80]
  PIN o_d[81]
    DIRECTION OUTPUT ;
    USE SIGNAL ;
    PORT
      LAYER M5 ;
        RECT  17.952 0 17.976 0.192 ;
    END
  END o_d[81]
  PIN o_d[82]
    DIRECTION OUTPUT ;
    USE SIGNAL ;
    PORT
      LAYER M5 ;
        RECT  18.096 0 18.12 0.192 ;
    END
  END o_d[82]
  PIN o_d[83]
    DIRECTION OUTPUT ;
    USE SIGNAL ;
    PORT
      LAYER M5 ;
        RECT  18.24 0 18.264 0.192 ;
    END
  END o_d[83]
  PIN o_d[84]
    DIRECTION OUTPUT ;
    USE SIGNAL ;
    PORT
      LAYER M5 ;
        RECT  18.384 0 18.408 0.192 ;
    END
  END o_d[84]
  PIN o_d[85]
    DIRECTION OUTPUT ;
    USE SIGNAL ;
    PORT
      LAYER M5 ;
        RECT  18.528 0 18.552 0.192 ;
    END
  END o_d[85]
  PIN o_d[86]
    DIRECTION OUTPUT ;
    USE SIGNAL ;
    PORT
      LAYER M5 ;
        RECT  18.672 0 18.696 0.192 ;
    END
  END o_d[86]
  PIN o_d[87]
    DIRECTION OUTPUT ;
    USE SIGNAL ;
    PORT
      LAYER M5 ;
        RECT  18.816 0 18.84 0.192 ;
    END
  END o_d[87]
  PIN o_d[88]
    DIRECTION OUTPUT ;
    USE SIGNAL ;
    PORT
      LAYER M5 ;
        RECT  18.96 0 18.984 0.192 ;
    END
  END o_d[88]
  PIN o_d[89]
    DIRECTION OUTPUT ;
    USE SIGNAL ;
    PORT
      LAYER M5 ;
        RECT  19.104 0 19.128 0.192 ;
    END
  END o_d[89]
  PIN o_d[8]
    DIRECTION OUTPUT ;
    USE SIGNAL ;
    PORT
      LAYER M5 ;
        RECT  5.472 0 5.496 0.192 ;
    END
  END o_d[8]
  PIN o_d[90]
    DIRECTION OUTPUT ;
    USE SIGNAL ;
    PORT
      LAYER M5 ;
        RECT  19.248 0 19.272 0.192 ;
    END
  END o_d[90]
  PIN o_d[91]
    DIRECTION OUTPUT ;
    USE SIGNAL ;
    PORT
      LAYER M5 ;
        RECT  19.392 0 19.416 0.192 ;
    END
  END o_d[91]
  PIN o_d[92]
    DIRECTION OUTPUT ;
    USE SIGNAL ;
    PORT
      LAYER M5 ;
        RECT  19.536 0 19.56 0.192 ;
    END
  END o_d[92]
  PIN o_d[93]
    DIRECTION OUTPUT ;
    USE SIGNAL ;
    PORT
      LAYER M5 ;
        RECT  19.68 0 19.704 0.192 ;
    END
  END o_d[93]
  PIN o_d[94]
    DIRECTION OUTPUT ;
    USE SIGNAL ;
    PORT
      LAYER M5 ;
        RECT  19.824 0 19.848 0.192 ;
    END
  END o_d[94]
  PIN o_d[95]
    DIRECTION OUTPUT ;
    USE SIGNAL ;
    PORT
      LAYER M5 ;
        RECT  19.968 0 19.992 0.192 ;
    END
  END o_d[95]
  PIN o_d[96]
    DIRECTION OUTPUT ;
    USE SIGNAL ;
    PORT
      LAYER M5 ;
        RECT  20.112 0 20.136 0.192 ;
    END
  END o_d[96]
  PIN o_d[97]
    DIRECTION OUTPUT ;
    USE SIGNAL ;
    PORT
      LAYER M5 ;
        RECT  20.256 0 20.28 0.192 ;
    END
  END o_d[97]
  PIN o_d[98]
    DIRECTION OUTPUT ;
    USE SIGNAL ;
    PORT
      LAYER M5 ;
        RECT  20.4 0 20.424 0.192 ;
    END
  END o_d[98]
  PIN o_d[99]
    DIRECTION OUTPUT ;
    USE SIGNAL ;
    PORT
      LAYER M5 ;
        RECT  20.544 0 20.568 0.192 ;
    END
  END o_d[99]
  PIN o_d[9]
    DIRECTION OUTPUT ;
    USE SIGNAL ;
    PORT
      LAYER M5 ;
        RECT  6.144 0 6.168 0.192 ;
    END
  END o_d[9]
  PIN o_row[0]
    DIRECTION OUTPUT ;
    USE SIGNAL ;
    PORT
      LAYER M5 ;
        RECT  88.752 0 88.776 0.192 ;
    END
  END o_row[0]
  PIN o_row[10]
    DIRECTION OUTPUT ;
    USE SIGNAL ;
    PORT
      LAYER M5 ;
        RECT  90.192 0 90.216 0.192 ;
    END
  END o_row[10]
  PIN o_row[11]
    DIRECTION OUTPUT ;
    USE SIGNAL ;
    PORT
      LAYER M5 ;
        RECT  90.336 0 90.36 0.192 ;
    END
  END o_row[11]
  PIN o_row[12]
    DIRECTION OUTPUT ;
    USE SIGNAL ;
    PORT
      LAYER M5 ;
        RECT  90.48 0 90.504 0.192 ;
    END
  END o_row[12]
  PIN o_row[13]
    DIRECTION OUTPUT ;
    USE SIGNAL ;
    PORT
      LAYER M5 ;
        RECT  90.624 0 90.648 0.192 ;
    END
  END o_row[13]
  PIN o_row[1]
    DIRECTION OUTPUT ;
    USE SIGNAL ;
    PORT
      LAYER M5 ;
        RECT  88.896 0 88.92 0.192 ;
    END
  END o_row[1]
  PIN o_row[2]
    DIRECTION OUTPUT ;
    USE SIGNAL ;
    PORT
      LAYER M5 ;
        RECT  89.04 0 89.064 0.192 ;
    END
  END o_row[2]
  PIN o_row[3]
    DIRECTION OUTPUT ;
    USE SIGNAL ;
    PORT
      LAYER M5 ;
        RECT  89.184 0 89.208 0.192 ;
    END
  END o_row[3]
  PIN o_row[4]
    DIRECTION OUTPUT ;
    USE SIGNAL ;
    PORT
      LAYER M5 ;
        RECT  89.328 0 89.352 0.192 ;
    END
  END o_row[4]
  PIN o_row[5]
    DIRECTION OUTPUT ;
    USE SIGNAL ;
    PORT
      LAYER M5 ;
        RECT  89.472 0 89.496 0.192 ;
    END
  END o_row[5]
  PIN o_row[6]
    DIRECTION OUTPUT ;
    USE SIGNAL ;
    PORT
      LAYER M5 ;
        RECT  89.616 0 89.64 0.192 ;
    END
  END o_row[6]
  PIN o_row[7]
    DIRECTION OUTPUT ;
    USE SIGNAL ;
    PORT
      LAYER M5 ;
        RECT  89.76 0 89.784 0.192 ;
    END
  END o_row[7]
  PIN o_row[8]
    DIRECTION OUTPUT ;
    USE SIGNAL ;
    PORT
      LAYER M5 ;
        RECT  89.904 0 89.928 0.192 ;
    END
  END o_row[8]
  PIN o_row[9]
    DIRECTION OUTPUT ;
    USE SIGNAL ;
    PORT
      LAYER M5 ;
        RECT  90.048 0 90.072 0.192 ;
    END
  END o_row[9]
  PIN o_v
    DIRECTION OUTPUT ;
    USE SIGNAL ;
    PORT
      LAYER M5 ;
        RECT  88.608 0 88.632 0.192 ;
    END
  END o_v
  PIN rst_n
    DIRECTION INPUT ;
    USE SIGNAL ;
    PORT
      LAYER M4 ;
        RECT  0 10.08 0.192 10.104 ;
    END
    PORT
      LAYER M4 ;
        RECT  0.156 10.08 2.408 10.104 ;
    END
  END rst_n
  PIN VDD
    DIRECTION INOUT ;
    USE POWER ;
    PORT
      LAYER M5 ;
        RECT  88.992 2.151 89.112 92.889 ;
        RECT  83.592 2.151 83.712 92.889 ;
        RECT  78.192 2.151 78.312 92.889 ;
        RECT  72.792 2.151 72.912 92.889 ;
        RECT  67.392 2.151 67.512 92.889 ;
        RECT  61.992 2.151 62.112 92.889 ;
        RECT  56.592 2.151 56.712 92.889 ;
        RECT  51.192 2.151 51.312 92.889 ;
        RECT  45.792 2.151 45.912 92.889 ;
        RECT  40.392 2.151 40.512 92.889 ;
        RECT  34.992 2.151 35.112 92.889 ;
        RECT  29.592 2.151 29.712 92.889 ;
        RECT  24.192 2.151 24.312 92.889 ;
        RECT  18.792 2.151 18.912 92.889 ;
        RECT  13.392 2.151 13.512 92.889 ;
        RECT  7.992 2.151 8.112 92.889 ;
        RECT  2.592 2.151 2.712 92.889 ;
    END
  END VDD
  PIN VSS
    DIRECTION INOUT ;
    USE GROUND ;
    PORT
      LAYER M5 ;
        RECT  88.8 2.137 88.92 92.903 ;
        RECT  83.4 2.137 83.52 92.903 ;
        RECT  78 2.137 78.12 92.903 ;
        RECT  72.6 2.137 72.72 92.903 ;
        RECT  67.2 2.137 67.32 92.903 ;
        RECT  61.8 2.137 61.92 92.903 ;
        RECT  56.4 2.137 56.52 92.903 ;
        RECT  51 2.137 51.12 92.903 ;
        RECT  45.6 2.137 45.72 92.903 ;
        RECT  40.2 2.137 40.32 92.903 ;
        RECT  34.8 2.137 34.92 92.903 ;
        RECT  29.4 2.137 29.52 92.903 ;
        RECT  24 2.137 24.12 92.903 ;
        RECT  18.6 2.137 18.72 92.903 ;
        RECT  13.2 2.137 13.32 92.903 ;
        RECT  7.8 2.137 7.92 92.903 ;
        RECT  2.4 2.137 2.52 92.903 ;
    END
  END VSS
  # OT_OBS_CLOSED layer=M5 d_um=1.536 added=158
  OBS
    LAYER RVTN ;
     RECT  2.16 2.16 92.88 2.295 ;
     RECT  2.16 2.565 92.88 2.835 ;
     RECT  2.16 3.105 92.88 3.375 ;
     RECT  2.16 3.645 92.88 3.915 ;
     RECT  2.16 4.185 92.88 4.455 ;
     RECT  2.16 4.725 92.88 4.995 ;
     RECT  2.16 5.265 92.88 5.535 ;
     RECT  2.16 5.805 92.88 6.075 ;
     RECT  2.16 6.345 92.88 6.615 ;
     RECT  2.16 6.885 92.88 7.155 ;
     RECT  2.16 7.425 92.88 7.695 ;
     RECT  2.16 7.965 92.88 8.235 ;
     RECT  2.16 8.505 92.88 8.775 ;
     RECT  2.16 9.045 92.88 9.315 ;
     RECT  2.16 9.585 92.88 9.855 ;
     RECT  2.16 10.125 92.88 10.395 ;
     RECT  2.16 10.665 92.88 10.935 ;
     RECT  2.16 11.205 92.88 11.475 ;
     RECT  2.16 11.745 92.88 12.015 ;
     RECT  2.16 12.285 92.88 12.555 ;
     RECT  2.16 12.825 92.88 13.095 ;
     RECT  2.16 13.365 92.88 13.635 ;
     RECT  2.16 13.905 92.88 14.175 ;
     RECT  2.16 14.445 92.88 14.715 ;
     RECT  2.16 14.985 92.88 15.255 ;
     RECT  2.16 15.525 92.88 15.795 ;
     RECT  2.16 16.065 92.88 16.335 ;
     RECT  2.16 16.605 92.88 16.875 ;
     RECT  2.16 17.145 92.88 17.415 ;
     RECT  2.16 17.685 92.88 17.955 ;
     RECT  2.16 18.225 92.88 18.495 ;
     RECT  2.16 18.765 92.88 19.035 ;
     RECT  2.16 19.305 92.88 19.575 ;
     RECT  2.16 19.845 92.88 20.115 ;
     RECT  2.16 20.385 92.88 20.655 ;
     RECT  2.16 20.925 92.88 21.195 ;
     RECT  2.16 21.465 92.88 21.735 ;
     RECT  2.16 22.005 92.88 22.275 ;
     RECT  2.16 22.545 92.88 22.815 ;
     RECT  2.16 23.085 92.88 23.355 ;
     RECT  2.16 23.625 92.88 23.895 ;
     RECT  2.16 24.165 92.88 24.435 ;
     RECT  2.16 24.705 92.88 24.975 ;
     RECT  2.16 25.245 92.88 25.515 ;
     RECT  2.16 25.785 92.88 26.055 ;
     RECT  2.16 26.325 92.88 26.595 ;
     RECT  2.16 26.865 92.88 27.135 ;
     RECT  2.16 27.405 92.88 27.675 ;
     RECT  2.16 27.945 92.88 28.215 ;
     RECT  2.16 28.485 92.88 28.755 ;
     RECT  2.16 29.025 92.88 29.295 ;
     RECT  2.16 29.565 92.88 29.835 ;
     RECT  2.16 30.105 92.88 30.375 ;
     RECT  2.16 30.645 92.88 30.915 ;
     RECT  2.16 31.185 92.88 31.455 ;
     RECT  2.16 31.725 92.88 31.995 ;
     RECT  2.16 32.265 92.88 32.535 ;
     RECT  2.16 32.805 92.88 33.075 ;
     RECT  2.16 33.345 92.88 33.615 ;
     RECT  2.16 33.885 92.88 34.155 ;
     RECT  2.16 34.425 92.88 34.695 ;
     RECT  2.16 34.965 92.88 35.235 ;
     RECT  2.16 35.505 92.88 35.775 ;
     RECT  2.16 36.045 92.88 36.315 ;
     RECT  2.16 36.585 92.88 36.855 ;
     RECT  2.16 37.125 92.88 37.395 ;
     RECT  2.16 37.665 92.88 37.935 ;
     RECT  2.16 38.205 92.88 38.475 ;
     RECT  2.16 38.745 92.88 39.015 ;
     RECT  2.16 39.285 92.88 39.555 ;
     RECT  2.16 39.825 92.88 40.095 ;
     RECT  2.16 40.365 92.88 40.635 ;
     RECT  2.16 40.905 92.88 41.175 ;
     RECT  2.16 41.445 92.88 41.715 ;
     RECT  2.16 41.985 92.88 42.255 ;
     RECT  2.16 42.525 92.88 42.795 ;
     RECT  2.16 43.065 92.88 43.335 ;
     RECT  2.16 43.605 92.88 43.875 ;
     RECT  2.16 44.145 92.88 44.415 ;
     RECT  2.16 44.685 92.88 44.955 ;
     RECT  2.16 45.225 92.88 45.495 ;
     RECT  2.16 45.765 92.88 46.035 ;
     RECT  2.16 46.305 92.88 46.575 ;
     RECT  2.16 46.845 92.88 47.115 ;
     RECT  2.16 47.385 92.88 47.655 ;
     RECT  2.16 47.925 92.88 48.195 ;
     RECT  2.16 48.465 92.88 48.735 ;
     RECT  2.16 49.005 92.88 49.275 ;
     RECT  2.16 49.545 92.88 49.815 ;
     RECT  2.16 50.085 92.88 50.355 ;
     RECT  2.16 50.625 92.88 50.895 ;
     RECT  2.16 51.165 92.88 51.435 ;
     RECT  2.16 51.705 92.88 51.975 ;
     RECT  2.16 52.245 92.88 52.515 ;
     RECT  2.16 52.785 92.88 53.055 ;
     RECT  2.16 53.325 92.88 53.595 ;
     RECT  2.16 53.865 92.88 54.135 ;
     RECT  2.16 54.405 92.88 54.675 ;
     RECT  2.16 54.945 92.88 55.215 ;
     RECT  2.16 55.485 92.88 55.755 ;
     RECT  2.16 56.025 92.88 56.295 ;
     RECT  2.16 56.565 92.88 56.835 ;
     RECT  2.16 57.105 92.88 57.375 ;
     RECT  2.16 57.645 92.88 57.915 ;
     RECT  2.16 58.185 92.88 58.455 ;
     RECT  2.16 58.725 92.88 58.995 ;
     RECT  2.16 59.265 92.88 59.535 ;
     RECT  2.16 59.805 92.88 60.075 ;
     RECT  2.16 60.345 92.88 60.615 ;
     RECT  2.16 60.885 92.88 61.155 ;
     RECT  2.16 61.425 92.88 61.695 ;
     RECT  2.16 61.965 92.88 62.235 ;
     RECT  2.16 62.505 92.88 62.775 ;
     RECT  2.16 63.045 92.88 63.315 ;
     RECT  2.16 63.585 92.88 63.855 ;
     RECT  2.16 64.125 92.88 64.395 ;
     RECT  2.16 64.665 92.88 64.935 ;
     RECT  2.16 65.205 92.88 65.475 ;
     RECT  2.16 65.745 92.88 66.015 ;
     RECT  2.16 66.285 92.88 66.555 ;
     RECT  2.16 66.825 92.88 67.095 ;
     RECT  2.16 67.365 92.88 67.635 ;
     RECT  2.16 67.905 92.88 68.175 ;
     RECT  2.16 68.445 92.88 68.715 ;
     RECT  2.16 68.985 92.88 69.255 ;
     RECT  2.16 69.525 92.88 69.795 ;
     RECT  2.16 70.065 92.88 70.335 ;
     RECT  2.16 70.605 92.88 70.875 ;
     RECT  2.16 71.145 92.88 71.415 ;
     RECT  2.16 71.685 92.88 71.955 ;
     RECT  2.16 72.225 92.88 72.495 ;
     RECT  2.16 72.765 92.88 73.035 ;
     RECT  2.16 73.305 92.88 73.575 ;
     RECT  2.16 73.845 92.88 74.115 ;
     RECT  2.16 74.385 92.88 74.655 ;
     RECT  2.16 74.925 92.88 75.195 ;
     RECT  2.16 75.465 92.88 75.735 ;
     RECT  2.16 76.005 92.88 76.275 ;
     RECT  2.16 76.545 92.88 76.815 ;
     RECT  2.16 77.085 92.88 77.355 ;
     RECT  2.16 77.625 92.88 77.895 ;
     RECT  2.16 78.165 92.88 78.435 ;
     RECT  2.16 78.705 92.88 78.975 ;
     RECT  2.16 79.245 92.88 79.515 ;
     RECT  2.16 79.785 92.88 80.055 ;
     RECT  2.16 80.325 92.88 80.595 ;
     RECT  2.16 80.865 92.88 81.135 ;
     RECT  2.16 81.405 92.88 81.675 ;
     RECT  2.16 81.945 92.88 82.215 ;
     RECT  2.16 82.485 92.88 82.755 ;
     RECT  2.16 83.025 92.88 83.295 ;
     RECT  2.16 83.565 92.88 83.835 ;
     RECT  2.16 84.105 92.88 84.375 ;
     RECT  2.16 84.645 92.88 84.915 ;
     RECT  2.16 85.185 92.88 85.455 ;
     RECT  2.16 85.725 92.88 85.995 ;
     RECT  2.16 86.265 92.88 86.535 ;
     RECT  2.16 86.805 92.88 87.075 ;
     RECT  2.16 87.345 92.88 87.615 ;
     RECT  2.16 87.885 92.88 88.155 ;
     RECT  2.16 88.425 92.88 88.695 ;
     RECT  2.16 88.965 92.88 89.235 ;
     RECT  2.16 89.505 92.88 89.775 ;
     RECT  2.16 90.045 92.88 90.315 ;
     RECT  2.16 90.585 92.88 90.855 ;
     RECT  2.16 91.125 92.88 91.395 ;
     RECT  2.16 91.665 92.88 91.935 ;
     RECT  2.16 92.205 92.88 92.475 ;
     RECT  2.16 92.745 92.88 92.88 ;
    LAYER RVTP ;
     RECT  2.16 2.295 92.88 2.565 ;
     RECT  2.16 2.835 92.88 3.105 ;
     RECT  2.16 3.375 92.88 3.645 ;
     RECT  2.16 3.915 92.88 4.185 ;
     RECT  2.16 4.455 92.88 4.725 ;
     RECT  2.16 4.995 92.88 5.265 ;
     RECT  2.16 5.535 92.88 5.805 ;
     RECT  2.16 6.075 92.88 6.345 ;
     RECT  2.16 6.615 92.88 6.885 ;
     RECT  2.16 7.155 92.88 7.425 ;
     RECT  2.16 7.695 92.88 7.965 ;
     RECT  2.16 8.235 92.88 8.505 ;
     RECT  2.16 8.775 92.88 9.045 ;
     RECT  2.16 9.315 92.88 9.585 ;
     RECT  2.16 9.855 92.88 10.125 ;
     RECT  2.16 10.395 92.88 10.665 ;
     RECT  2.16 10.935 92.88 11.205 ;
     RECT  2.16 11.475 92.88 11.745 ;
     RECT  2.16 12.015 92.88 12.285 ;
     RECT  2.16 12.555 92.88 12.825 ;
     RECT  2.16 13.095 92.88 13.365 ;
     RECT  2.16 13.635 92.88 13.905 ;
     RECT  2.16 14.175 92.88 14.445 ;
     RECT  2.16 14.715 92.88 14.985 ;
     RECT  2.16 15.255 92.88 15.525 ;
     RECT  2.16 15.795 92.88 16.065 ;
     RECT  2.16 16.335 92.88 16.605 ;
     RECT  2.16 16.875 92.88 17.145 ;
     RECT  2.16 17.415 92.88 17.685 ;
     RECT  2.16 17.955 92.88 18.225 ;
     RECT  2.16 18.495 92.88 18.765 ;
     RECT  2.16 19.035 92.88 19.305 ;
     RECT  2.16 19.575 92.88 19.845 ;
     RECT  2.16 20.115 92.88 20.385 ;
     RECT  2.16 20.655 92.88 20.925 ;
     RECT  2.16 21.195 92.88 21.465 ;
     RECT  2.16 21.735 92.88 22.005 ;
     RECT  2.16 22.275 92.88 22.545 ;
     RECT  2.16 22.815 92.88 23.085 ;
     RECT  2.16 23.355 92.88 23.625 ;
     RECT  2.16 23.895 92.88 24.165 ;
     RECT  2.16 24.435 92.88 24.705 ;
     RECT  2.16 24.975 92.88 25.245 ;
     RECT  2.16 25.515 92.88 25.785 ;
     RECT  2.16 26.055 92.88 26.325 ;
     RECT  2.16 26.595 92.88 26.865 ;
     RECT  2.16 27.135 92.88 27.405 ;
     RECT  2.16 27.675 92.88 27.945 ;
     RECT  2.16 28.215 92.88 28.485 ;
     RECT  2.16 28.755 92.88 29.025 ;
     RECT  2.16 29.295 92.88 29.565 ;
     RECT  2.16 29.835 92.88 30.105 ;
     RECT  2.16 30.375 92.88 30.645 ;
     RECT  2.16 30.915 92.88 31.185 ;
     RECT  2.16 31.455 92.88 31.725 ;
     RECT  2.16 31.995 92.88 32.265 ;
     RECT  2.16 32.535 92.88 32.805 ;
     RECT  2.16 33.075 92.88 33.345 ;
     RECT  2.16 33.615 92.88 33.885 ;
     RECT  2.16 34.155 92.88 34.425 ;
     RECT  2.16 34.695 92.88 34.965 ;
     RECT  2.16 35.235 92.88 35.505 ;
     RECT  2.16 35.775 92.88 36.045 ;
     RECT  2.16 36.315 92.88 36.585 ;
     RECT  2.16 36.855 92.88 37.125 ;
     RECT  2.16 37.395 92.88 37.665 ;
     RECT  2.16 37.935 92.88 38.205 ;
     RECT  2.16 38.475 92.88 38.745 ;
     RECT  2.16 39.015 92.88 39.285 ;
     RECT  2.16 39.555 92.88 39.825 ;
     RECT  2.16 40.095 92.88 40.365 ;
     RECT  2.16 40.635 92.88 40.905 ;
     RECT  2.16 41.175 92.88 41.445 ;
     RECT  2.16 41.715 92.88 41.985 ;
     RECT  2.16 42.255 92.88 42.525 ;
     RECT  2.16 42.795 92.88 43.065 ;
     RECT  2.16 43.335 92.88 43.605 ;
     RECT  2.16 43.875 92.88 44.145 ;
     RECT  2.16 44.415 92.88 44.685 ;
     RECT  2.16 44.955 92.88 45.225 ;
     RECT  2.16 45.495 92.88 45.765 ;
     RECT  2.16 46.035 92.88 46.305 ;
     RECT  2.16 46.575 92.88 46.845 ;
     RECT  2.16 47.115 92.88 47.385 ;
     RECT  2.16 47.655 92.88 47.925 ;
     RECT  2.16 48.195 92.88 48.465 ;
     RECT  2.16 48.735 92.88 49.005 ;
     RECT  2.16 49.275 92.88 49.545 ;
     RECT  2.16 49.815 92.88 50.085 ;
     RECT  2.16 50.355 92.88 50.625 ;
     RECT  2.16 50.895 92.88 51.165 ;
     RECT  2.16 51.435 92.88 51.705 ;
     RECT  2.16 51.975 92.88 52.245 ;
     RECT  2.16 52.515 92.88 52.785 ;
     RECT  2.16 53.055 92.88 53.325 ;
     RECT  2.16 53.595 92.88 53.865 ;
     RECT  2.16 54.135 92.88 54.405 ;
     RECT  2.16 54.675 92.88 54.945 ;
     RECT  2.16 55.215 92.88 55.485 ;
     RECT  2.16 55.755 92.88 56.025 ;
     RECT  2.16 56.295 92.88 56.565 ;
     RECT  2.16 56.835 92.88 57.105 ;
     RECT  2.16 57.375 92.88 57.645 ;
     RECT  2.16 57.915 92.88 58.185 ;
     RECT  2.16 58.455 92.88 58.725 ;
     RECT  2.16 58.995 92.88 59.265 ;
     RECT  2.16 59.535 92.88 59.805 ;
     RECT  2.16 60.075 92.88 60.345 ;
     RECT  2.16 60.615 92.88 60.885 ;
     RECT  2.16 61.155 92.88 61.425 ;
     RECT  2.16 61.695 92.88 61.965 ;
     RECT  2.16 62.235 92.88 62.505 ;
     RECT  2.16 62.775 92.88 63.045 ;
     RECT  2.16 63.315 92.88 63.585 ;
     RECT  2.16 63.855 92.88 64.125 ;
     RECT  2.16 64.395 92.88 64.665 ;
     RECT  2.16 64.935 92.88 65.205 ;
     RECT  2.16 65.475 92.88 65.745 ;
     RECT  2.16 66.015 92.88 66.285 ;
     RECT  2.16 66.555 92.88 66.825 ;
     RECT  2.16 67.095 92.88 67.365 ;
     RECT  2.16 67.635 92.88 67.905 ;
     RECT  2.16 68.175 92.88 68.445 ;
     RECT  2.16 68.715 92.88 68.985 ;
     RECT  2.16 69.255 92.88 69.525 ;
     RECT  2.16 69.795 92.88 70.065 ;
     RECT  2.16 70.335 92.88 70.605 ;
     RECT  2.16 70.875 92.88 71.145 ;
     RECT  2.16 71.415 92.88 71.685 ;
     RECT  2.16 71.955 92.88 72.225 ;
     RECT  2.16 72.495 92.88 72.765 ;
     RECT  2.16 73.035 92.88 73.305 ;
     RECT  2.16 73.575 92.88 73.845 ;
     RECT  2.16 74.115 92.88 74.385 ;
     RECT  2.16 74.655 92.88 74.925 ;
     RECT  2.16 75.195 92.88 75.465 ;
     RECT  2.16 75.735 92.88 76.005 ;
     RECT  2.16 76.275 92.88 76.545 ;
     RECT  2.16 76.815 92.88 77.085 ;
     RECT  2.16 77.355 92.88 77.625 ;
     RECT  2.16 77.895 92.88 78.165 ;
     RECT  2.16 78.435 92.88 78.705 ;
     RECT  2.16 78.975 92.88 79.245 ;
     RECT  2.16 79.515 92.88 79.785 ;
     RECT  2.16 80.055 92.88 80.325 ;
     RECT  2.16 80.595 92.88 80.865 ;
     RECT  2.16 81.135 92.88 81.405 ;
     RECT  2.16 81.675 92.88 81.945 ;
     RECT  2.16 82.215 92.88 82.485 ;
     RECT  2.16 82.755 92.88 83.025 ;
     RECT  2.16 83.295 92.88 83.565 ;
     RECT  2.16 83.835 92.88 84.105 ;
     RECT  2.16 84.375 92.88 84.645 ;
     RECT  2.16 84.915 92.88 85.185 ;
     RECT  2.16 85.455 92.88 85.725 ;
     RECT  2.16 85.995 92.88 86.265 ;
     RECT  2.16 86.535 92.88 86.805 ;
     RECT  2.16 87.075 92.88 87.345 ;
     RECT  2.16 87.615 92.88 87.885 ;
     RECT  2.16 88.155 92.88 88.425 ;
     RECT  2.16 88.695 92.88 88.965 ;
     RECT  2.16 89.235 92.88 89.505 ;
     RECT  2.16 89.775 92.88 90.045 ;
     RECT  2.16 90.315 92.88 90.585 ;
     RECT  2.16 90.855 92.88 91.125 ;
     RECT  2.16 91.395 92.88 91.665 ;
     RECT  2.16 91.935 92.88 92.205 ;
     RECT  2.16 92.475 92.88 92.745 ;
    LAYER M1 ;
     RECT  2.16 2.151 92.88 92.889 ;
    LAYER M2 ;
     RECT  0.535 33.552 2.16 33.57 ;
     RECT  2.16 2.151 3.667 92.889 ;
     RECT  3.667 2.106 3.883 92.889 ;
     RECT  3.883 1.962 4.027 92.889 ;
     RECT  4.027 1.881 5.747 92.889 ;
     RECT  5.747 2.07 7.007 92.889 ;
     RECT  7.007 2.106 7.403 92.889 ;
     RECT  7.403 2.151 12.019 92.889 ;
     RECT  12.019 2.106 13.019 92.889 ;
     RECT  13.019 2.151 15.763 92.889 ;
     RECT  15.763 2.106 16.439 92.889 ;
     RECT  16.439 2.151 27.679 92.889 ;
     RECT  27.679 2.106 28.679 92.889 ;
     RECT  28.679 2.151 32.575 92.889 ;
     RECT  32.575 2.106 33.503 92.889 ;
     RECT  33.503 2.151 40.459 92.889 ;
     RECT  40.459 2.106 41.747 92.889 ;
     RECT  41.747 2.151 43.015 92.889 ;
     RECT  43.015 2.106 43.799 92.889 ;
     RECT  43.799 2.151 45.463 92.889 ;
     RECT  45.463 2.106 46.175 92.889 ;
     RECT  46.175 2.151 56.551 92.889 ;
     RECT  56.551 2.106 57.587 92.889 ;
     RECT  57.587 2.151 62.131 92.889 ;
     RECT  62.131 2.106 62.915 92.889 ;
     RECT  62.915 2.151 69.619 92.889 ;
     RECT  69.619 2.106 70.115 92.889 ;
     RECT  70.115 2.151 73.795 92.889 ;
     RECT  73.795 2.106 74.579 92.889 ;
     RECT  74.875 1.152 75.047 1.17 ;
     RECT  74.579 2.151 76.315 92.889 ;
     RECT  76.495 1.152 76.667 1.17 ;
     RECT  76.315 2.106 77.351 92.889 ;
     RECT  77.351 2.151 78.259 92.889 ;
     RECT  78.259 2.106 79.115 92.889 ;
     RECT  79.115 2.151 85.495 92.889 ;
     RECT  85.495 2.106 87.395 92.889 ;
     RECT  87.395 2.151 90.067 92.889 ;
     RECT  90.067 2.106 91.103 92.889 ;
     RECT  91.103 2.151 92.88 92.889 ;
     RECT  92.88 18.666 93.515 18.684 ;
     RECT  92.88 76.32 93.515 76.338 ;
     RECT  92.88 47.286 94.091 47.304 ;
    LAYER M3 ;
     RECT  4.176 0.187 4.194 0.235 ;
     RECT  35.64 0.187 35.658 0.235 ;
     RECT  64.188 0.187 64.206 0.235 ;
     RECT  64.044 0.235 64.206 0.317 ;
     RECT  24.372 0.187 24.39 0.365 ;
     RECT  35.28 0.235 35.658 0.365 ;
     RECT  64.044 0.317 64.062 0.413 ;
     RECT  72.504 0.235 72.522 0.413 ;
     RECT  46.08 0.331 46.098 0.461 ;
     RECT  13.14 0.187 13.158 0.523 ;
     RECT  4.176 0.235 4.446 0.571 ;
     RECT  17.532 0.187 17.55 0.571 ;
     RECT  35.64 0.365 35.658 0.571 ;
     RECT  56.304 0.523 56.322 0.571 ;
     RECT  4.176 0.571 4.914 1.099 ;
     RECT  6.588 0.187 6.606 1.099 ;
     RECT  56.304 0.571 56.862 1.099 ;
     RECT  60.624 0.187 60.642 1.099 ;
     RECT  89.172 0.571 89.19 1.099 ;
     RECT  18.54 0.187 18.558 1.147 ;
     RECT  22.68 0.571 23.094 1.147 ;
     RECT  35.64 0.571 36.054 1.147 ;
     RECT  40.896 0.571 40.914 1.147 ;
     RECT  71.748 0.187 71.766 1.147 ;
     RECT  74.88 0.571 74.898 1.147 ;
     RECT  76.5 1.099 76.518 1.147 ;
     RECT  77.292 0.523 77.31 1.147 ;
     RECT  84.888 0.571 84.906 1.147 ;
     RECT  74.88 1.147 75.042 1.175 ;
     RECT  76.5 1.147 77.31 1.175 ;
     RECT  6.048 1.099 6.606 1.675 ;
     RECT  7.596 0.571 7.614 1.675 ;
     RECT  11.772 0.187 11.79 1.675 ;
     RECT  12.852 0.523 13.158 1.675 ;
     RECT  37.8 0.187 37.818 1.675 ;
     RECT  65.916 1.147 65.934 1.675 ;
     RECT  81.216 1.147 81.234 1.675 ;
     RECT  4.176 1.099 5.058 1.723 ;
     RECT  6.048 1.675 7.614 1.723 ;
     RECT  11.772 1.675 13.158 1.723 ;
     RECT  16.38 1.147 16.398 1.723 ;
     RECT  17.496 0.571 17.55 1.723 ;
     RECT  18.54 1.147 19.278 1.723 ;
     RECT  39.996 0.571 40.014 1.723 ;
     RECT  40.86 1.147 40.914 1.723 ;
     RECT  48.42 1.147 48.438 1.723 ;
     RECT  51.372 0.187 51.57 1.723 ;
     RECT  56.304 1.099 57.078 1.723 ;
     RECT  60.12 1.099 60.642 1.723 ;
     RECT  67.68 1.147 67.698 1.723 ;
     RECT  69.48 1.147 69.858 1.723 ;
     RECT  83.952 0.187 83.97 1.723 ;
     RECT  84.708 1.147 84.906 1.723 ;
     RECT  87.876 0.187 87.894 1.723 ;
     RECT  89.172 1.099 89.694 1.723 ;
     RECT  90.432 0.571 90.45 1.723 ;
     RECT  9.936 1.723 9.954 1.771 ;
     RECT  30.024 0.187 30.042 1.771 ;
     RECT  66.96 1.723 68.058 1.771 ;
     RECT  79.416 1.723 79.434 1.771 ;
     RECT  83.952 1.723 84.906 1.771 ;
     RECT  91.764 1.723 91.782 1.771 ;
     RECT  30.024 1.771 30.402 1.819 ;
     RECT  31.14 1.723 31.806 1.819 ;
     RECT  4.176 1.723 7.614 1.876 ;
     RECT  4.032 1.876 7.614 1.957 ;
     RECT  3.888 1.957 7.614 2.011 ;
     RECT  30.024 1.819 31.806 2.011 ;
     RECT  35.64 1.147 36.414 2.011 ;
     RECT  61.776 1.195 61.794 2.011 ;
     RECT  62.676 1.723 62.694 2.011 ;
     RECT  78.264 1.771 78.282 2.059 ;
     RECT  3.888 2.011 7.974 2.101 ;
     RECT  15.768 1.723 16.398 2.101 ;
     RECT  28.08 2.059 28.098 2.101 ;
     RECT  29.304 2.011 31.806 2.101 ;
     RECT  33.336 1.723 33.354 2.101 ;
     RECT  43.308 1.723 43.326 2.101 ;
     RECT  46.008 1.723 46.71 2.101 ;
     RECT  56.304 1.723 57.474 2.101 ;
     RECT  61.776 2.011 62.694 2.101 ;
     RECT  73.548 1.723 73.566 2.101 ;
     RECT  75.024 1.175 75.042 2.101 ;
     RECT  76.572 1.175 77.31 2.101 ;
     RECT  83.808 1.771 84.906 2.101 ;
     RECT  87.732 1.723 87.894 2.101 ;
     RECT  89.172 1.723 90.45 2.101 ;
     RECT  91.44 1.771 91.782 2.101 ;
     RECT  64.08 1.147 64.098 2.107 ;
     RECT  11.16 1.723 13.158 2.143 ;
     RECT  24.804 1.147 24.822 2.143 ;
     RECT  34.956 2.011 36.414 2.143 ;
     RECT  51.372 1.723 51.822 2.143 ;
     RECT  76.32 2.101 77.346 2.143 ;
     RECT  78.264 2.059 78.318 2.143 ;
     RECT  82.62 1.723 83.07 2.143 ;
     RECT  83.808 2.101 85.518 2.143 ;
     RECT  89.172 2.101 91.782 2.143 ;
     RECT  37.368 1.675 37.818 2.155 ;
     RECT  66.96 1.771 68.382 2.155 ;
     RECT  73.548 2.101 73.818 2.155 ;
     RECT  74.556 2.101 75.042 2.155 ;
     RECT  3.672 2.101 7.974 2.191 ;
     RECT  11.16 2.143 13.305 2.191 ;
     RECT  14.328 0.187 15.03 2.191 ;
     RECT  15.768 2.101 16.434 2.191 ;
     RECT  17.496 1.723 19.638 2.191 ;
     RECT  21.888 1.147 21.906 2.191 ;
     RECT  22.68 1.147 23.274 2.191 ;
     RECT  32.58 2.101 32.598 2.191 ;
     RECT  33.336 2.101 33.498 2.191 ;
     RECT  34.815 2.143 36.414 2.191 ;
     RECT  37.26 2.155 37.818 2.191 ;
     RECT  39.168 1.723 40.914 2.191 ;
     RECT  41.724 2.101 41.742 2.191 ;
     RECT  43.02 2.101 43.794 2.191 ;
     RECT  45.468 2.101 46.71 2.191 ;
     RECT  47.988 1.723 48.438 2.191 ;
     RECT  51.015 2.143 51.822 2.191 ;
     RECT  56.304 2.101 57.582 2.191 ;
     RECT  59.4 1.723 60.642 2.191 ;
     RECT  61.776 2.101 62.91 2.191 ;
     RECT  63.936 2.107 64.098 2.191 ;
     RECT  65.664 1.675 65.934 2.191 ;
     RECT  66.708 2.155 68.382 2.191 ;
     RECT  69.192 1.723 70.434 2.191 ;
     RECT  71.748 1.147 72.774 2.191 ;
     RECT  76.32 2.143 78.318 2.191 ;
     RECT  80.82 1.675 81.234 2.191 ;
     RECT  82.62 2.143 85.518 2.191 ;
     RECT  86.544 2.155 86.562 2.191 ;
     RECT  87.372 2.101 87.894 2.191 ;
     RECT  88.815 2.143 91.782 2.191 ;
     RECT  11.16 2.191 20.25 2.227 ;
     RECT  32.58 2.191 33.822 2.227 ;
     RECT  34.596 2.191 37.818 2.227 ;
     RECT  11.088 2.227 20.25 2.251 ;
     RECT  32.58 2.227 37.818 2.251 ;
     RECT  38.628 2.191 44.73 2.251 ;
     RECT  54.36 2.191 54.378 2.251 ;
     RECT  55.332 1.723 55.35 2.251 ;
     RECT  56.304 2.191 60.642 2.251 ;
     RECT  61.776 2.191 64.098 2.251 ;
     RECT  3.672 2.191 8.226 2.263 ;
     RECT  9.072 1.723 9.09 2.263 ;
     RECT  9.936 1.771 10.134 2.263 ;
     RECT  21.888 2.191 23.274 2.263 ;
     RECT  24.015 2.143 24.822 2.263 ;
     RECT  25.596 1.723 26.154 2.263 ;
     RECT  27.684 2.101 31.806 2.263 ;
     RECT  32.58 2.251 44.73 2.263 ;
     RECT  45.468 2.191 47.178 2.263 ;
     RECT  47.988 2.191 49.194 2.263 ;
     RECT  50.292 2.191 51.822 2.263 ;
     RECT  54.36 2.251 55.35 2.263 ;
     RECT  56.304 2.251 64.098 2.263 ;
     RECT  65.088 2.191 72.774 2.263 ;
     RECT  73.548 2.155 75.042 2.263 ;
     RECT  75.78 2.191 78.318 2.263 ;
     RECT  80.496 2.191 81.81 2.285 ;
     RECT  3.672 2.263 10.134 2.335 ;
     RECT  11.088 2.251 20.502 2.371 ;
     RECT  27.612 2.263 51.822 2.371 ;
     RECT  52.668 1.723 53.55 2.371 ;
     RECT  54.36 2.263 72.774 2.371 ;
     RECT  73.548 2.263 78.318 2.371 ;
     RECT  80.604 2.285 81.81 2.371 ;
     RECT  82.62 2.191 92.394 2.371 ;
     RECT  2.415 2.143 2.505 2.413 ;
     RECT  3.276 2.335 10.134 2.413 ;
     RECT  2.415 2.413 10.134 2.461 ;
     RECT  11.088 2.371 21.15 2.461 ;
     RECT  21.888 2.263 26.154 2.461 ;
     RECT  26.892 2.371 53.55 2.461 ;
     RECT  54.36 2.371 78.318 2.461 ;
     RECT  2.415 2.461 26.154 2.489 ;
     RECT  3.528 2.489 26.154 2.569 ;
     RECT  26.892 2.461 78.318 2.569 ;
     RECT  3.528 2.569 78.318 2.641 ;
     RECT  79.056 1.771 79.434 2.641 ;
     RECT  80.604 2.371 92.394 2.923 ;
     RECT  3.528 2.641 79.794 3.181 ;
     RECT  80.604 2.923 92.466 3.181 ;
     RECT  3.528 3.181 92.466 3.299 ;
     RECT  3.528 3.299 92.394 3.379 ;
     RECT  2.415 2.489 2.697 3.931 ;
     RECT  3.42 3.379 92.394 3.931 ;
     RECT  2.415 3.931 92.394 3.983 ;
     RECT  3.42 3.983 92.394 4.109 ;
     RECT  3.42 4.109 92.322 4.145 ;
     RECT  3.42 4.145 92.142 4.379 ;
     RECT  3.42 4.379 91.998 4.877 ;
     RECT  3.42 4.877 3.51 4.919 ;
     RECT  4.32 4.877 91.998 5.189 ;
     RECT  4.32 5.189 91.53 5.971 ;
     RECT  4.32 5.971 91.926 6.575 ;
     RECT  44.244 6.575 91.926 6.809 ;
     RECT  44.28 6.809 91.926 6.845 ;
     RECT  44.28 6.845 76.806 7.079 ;
     RECT  4.32 6.575 43.506 7.115 ;
     RECT  4.32 7.115 36.018 7.349 ;
     RECT  36.792 7.115 43.506 7.349 ;
     RECT  77.616 6.845 91.926 7.421 ;
     RECT  77.616 7.421 85.374 7.457 ;
     RECT  4.32 7.349 35.874 7.619 ;
     RECT  2.415 3.983 2.697 10.075 ;
     RECT  3.42 4.919 3.438 10.075 ;
     RECT  2.415 10.075 3.438 10.291 ;
     RECT  2.415 10.291 3.582 10.355 ;
     RECT  3.42 10.355 3.582 10.471 ;
     RECT  4.32 7.619 35.766 10.471 ;
     RECT  44.28 7.079 63.81 10.741 ;
     RECT  64.584 7.079 76.806 10.741 ;
     RECT  77.796 7.457 85.374 10.741 ;
     RECT  3.42 10.471 35.766 10.769 ;
     RECT  44.28 10.741 76.806 10.769 ;
     RECT  3.42 10.769 35.694 10.859 ;
     RECT  3.42 10.859 3.546 10.895 ;
     RECT  2.415 10.355 2.697 14.107 ;
     RECT  2.412 14.107 2.697 14.144 ;
     RECT  3.42 10.895 3.438 18.031 ;
     RECT  4.32 10.859 35.694 18.031 ;
     RECT  3.42 18.031 35.694 18.185 ;
     RECT  93.492 18.661 93.51 18.749 ;
     RECT  2.415 14.144 2.697 21.883 ;
     RECT  2.34 21.883 2.697 21.965 ;
     RECT  2.415 21.965 2.697 25.915 ;
     RECT  2.304 25.915 2.697 26.285 ;
     RECT  3.42 18.185 3.438 26.365 ;
     RECT  4.32 18.185 35.694 26.365 ;
     RECT  3.42 26.365 35.694 26.825 ;
     RECT  44.28 10.769 54.27 27.301 ;
     RECT  55.008 10.769 76.806 27.301 ;
     RECT  44.28 27.301 76.806 27.341 ;
     RECT  2.415 26.285 2.697 29.911 ;
     RECT  3.42 26.825 3.438 29.911 ;
     RECT  2.415 29.911 3.438 30.065 ;
     RECT  4.32 26.825 35.694 30.839 ;
     RECT  3.42 30.065 3.438 33.583 ;
     RECT  4.392 30.839 35.694 33.583 ;
     RECT  0.54 33.547 0.558 33.725 ;
     RECT  3.42 33.583 35.694 33.845 ;
     RECT  3.42 33.845 3.438 34.771 ;
     RECT  3.42 34.771 3.51 34.799 ;
     RECT  2.415 30.065 2.697 37.471 ;
     RECT  3.492 34.799 3.51 37.471 ;
     RECT  2.415 37.471 3.51 37.579 ;
     RECT  2.304 37.579 3.51 37.589 ;
     RECT  2.304 37.589 2.697 37.625 ;
     RECT  3.42 37.589 3.51 37.697 ;
     RECT  2.415 37.625 2.697 41.611 ;
     RECT  2.304 41.611 2.697 41.675 ;
     RECT  3.42 37.697 3.438 41.791 ;
     RECT  3.42 41.791 3.582 41.945 ;
     RECT  3.42 41.945 3.438 45.019 ;
     RECT  4.32 33.845 35.694 45.019 ;
     RECT  2.415 41.675 2.697 45.499 ;
     RECT  2.304 45.499 2.697 45.563 ;
     RECT  3.42 45.019 35.694 45.995 ;
     RECT  4.32 45.995 35.694 46.301 ;
     RECT  86.328 7.421 91.926 46.499 ;
     RECT  90.576 46.499 91.926 46.543 ;
     RECT  92.736 46.381 92.754 46.543 ;
     RECT  36.828 7.349 43.506 46.747 ;
     RECT  44.28 27.341 54.27 46.747 ;
     RECT  55.008 27.341 76.806 46.747 ;
     RECT  77.544 10.741 85.374 46.747 ;
     RECT  86.328 46.499 89.838 46.747 ;
     RECT  14.328 46.301 35.694 47.191 ;
     RECT  36.612 46.747 43.506 47.191 ;
     RECT  44.28 46.747 76.806 47.191 ;
     RECT  77.544 46.747 89.838 47.191 ;
     RECT  14.328 47.191 35.802 47.461 ;
     RECT  36.612 47.191 89.838 47.461 ;
     RECT  94.068 47.281 94.086 47.549 ;
     RECT  4.32 46.301 13.59 47.731 ;
     RECT  14.328 47.461 89.838 47.731 ;
     RECT  90.576 46.543 92.754 47.731 ;
     RECT  4.32 47.731 92.754 47.885 ;
     RECT  4.32 47.885 80.766 48.001 ;
     RECT  3.42 45.995 3.438 48.119 ;
     RECT  81.54 47.885 92.754 48.461 ;
     RECT  4.248 48.001 80.766 48.811 ;
     RECT  81.54 48.461 84.33 48.811 ;
     RECT  4.248 48.811 84.33 48.929 ;
     RECT  2.415 45.563 2.697 49.315 ;
     RECT  4.248 48.929 80.838 49.351 ;
     RECT  2.304 49.315 2.697 49.421 ;
     RECT  3.528 49.351 80.838 49.469 ;
     RECT  3.528 49.469 26.874 49.505 ;
     RECT  4.248 49.505 26.874 49.739 ;
     RECT  27.648 49.469 60.822 49.739 ;
     RECT  27.648 49.739 60.75 50.971 ;
     RECT  2.415 49.421 2.697 53.275 ;
     RECT  2.415 53.275 2.79 53.321 ;
     RECT  4.248 49.739 26.838 57.259 ;
     RECT  4.14 57.259 26.838 57.451 ;
     RECT  3.96 57.451 26.838 57.605 ;
     RECT  4.068 57.605 26.838 57.875 ;
     RECT  4.248 57.875 26.838 61.051 ;
     RECT  2.415 53.321 2.697 61.195 ;
     RECT  4.14 61.051 26.838 61.231 ;
     RECT  2.304 61.195 2.697 61.232 ;
     RECT  3.528 61.231 26.838 61.385 ;
     RECT  2.415 61.232 2.697 65.083 ;
     RECT  2.304 65.083 2.697 65.165 ;
     RECT  4.248 61.385 26.838 65.281 ;
     RECT  3.996 65.281 26.838 65.435 ;
     RECT  4.248 65.435 26.838 68.909 ;
     RECT  2.415 65.165 2.697 69.115 ;
     RECT  2.304 69.115 2.697 69.215 ;
     RECT  2.415 69.215 2.697 69.331 ;
     RECT  2.415 69.331 3.114 69.449 ;
     RECT  4.248 68.909 8.154 72.931 ;
     RECT  2.415 69.449 2.697 73.003 ;
     RECT  2.415 73.003 2.79 73.04 ;
     RECT  4.068 72.931 8.154 73.265 ;
     RECT  93.492 76.309 93.51 76.349 ;
     RECT  4.248 73.265 8.154 76.741 ;
     RECT  2.415 73.04 2.697 76.855 ;
     RECT  4.14 76.741 8.154 76.891 ;
     RECT  2.304 76.855 2.697 76.925 ;
     RECT  3.528 76.891 8.154 77.045 ;
     RECT  27.612 50.971 60.75 79.411 ;
     RECT  61.56 49.469 80.838 79.411 ;
     RECT  27.612 79.411 80.838 79.469 ;
     RECT  4.248 77.045 8.154 80.905 ;
     RECT  4.176 80.905 8.154 80.941 ;
     RECT  3.96 80.941 8.154 81.095 ;
     RECT  2.415 76.925 2.697 84.811 ;
     RECT  2.304 84.811 2.697 84.875 ;
     RECT  4.248 81.095 8.154 84.991 ;
     RECT  3.564 84.991 8.154 85.145 ;
     RECT  61.56 79.469 80.838 88.312 ;
     RECT  81.756 48.929 84.33 88.312 ;
     RECT  2.415 84.875 2.697 88.699 ;
     RECT  61.56 88.312 84.33 88.747 ;
     RECT  85.176 48.461 92.754 88.747 ;
     RECT  27.612 79.469 60.75 88.861 ;
     RECT  61.56 88.747 92.754 88.861 ;
     RECT  2.415 88.699 2.79 88.925 ;
     RECT  4.248 85.145 8.154 89.005 ;
     RECT  3.888 89.005 8.154 89.041 ;
     RECT  3.708 89.041 8.154 89.195 ;
     RECT  8.928 68.909 26.838 89.311 ;
     RECT  27.612 88.861 92.754 89.311 ;
     RECT  4.248 89.195 8.154 89.371 ;
     RECT  8.928 89.311 92.754 89.371 ;
     RECT  4.248 89.371 92.754 91.435 ;
     RECT  3.924 91.435 92.754 91.589 ;
     RECT  3.924 91.589 92.142 91.625 ;
     RECT  4.068 91.625 92.142 92.477 ;
     RECT  15.66 92.477 92.142 92.515 ;
     RECT  4.068 92.477 14.922 92.551 ;
     RECT  15.66 92.515 92.178 92.579 ;
     RECT  2.415 88.925 2.697 92.627 ;
     RECT  4.032 92.551 14.922 92.669 ;
     RECT  15.66 92.579 75.906 92.669 ;
     RECT  76.68 92.579 92.178 92.669 ;
     RECT  7.74 92.669 11.61 92.705 ;
     RECT  18.432 92.669 21.222 92.705 ;
     RECT  80.748 92.669 82.566 92.705 ;
     RECT  83.304 92.669 84.222 92.705 ;
     RECT  90.612 92.669 92.07 92.705 ;
     RECT  4.068 92.669 6.75 92.741 ;
     RECT  15.66 92.669 16.038 92.741 ;
     RECT  16.992 92.669 17.694 92.741 ;
     RECT  18.432 92.705 20.934 92.741 ;
     RECT  21.96 92.669 24.354 92.741 ;
     RECT  25.632 92.669 29.862 92.741 ;
     RECT  38.304 92.669 40.986 92.741 ;
     RECT  42.228 92.669 43.326 92.741 ;
     RECT  52.992 92.669 53.514 92.741 ;
     RECT  54.396 92.669 54.702 92.741 ;
     RECT  55.548 92.669 55.566 92.741 ;
     RECT  57.456 92.669 58.734 92.741 ;
     RECT  60.3 92.669 62.658 92.741 ;
     RECT  63.972 92.669 63.99 92.741 ;
     RECT  71.028 92.669 75.798 92.741 ;
     RECT  76.68 92.669 77.202 92.741 ;
     RECT  78.015 92.669 79.686 92.741 ;
     RECT  81 92.705 82.566 92.741 ;
     RECT  85.428 92.669 89.154 92.741 ;
     RECT  44.496 92.669 44.514 92.777 ;
     RECT  65.592 92.669 70.182 92.777 ;
     RECT  85.428 92.741 85.986 92.777 ;
     RECT  78.015 92.741 78.39 92.813 ;
     RECT  87.084 92.741 87.822 92.813 ;
     RECT  90.612 92.705 91.422 92.813 ;
     RECT  15.948 92.741 16.038 92.849 ;
     RECT  18.432 92.741 20.682 92.849 ;
     RECT  21.96 92.741 23.274 92.849 ;
     RECT  25.632 92.741 26.838 92.849 ;
     RECT  29.16 92.741 29.862 92.849 ;
     RECT  33.984 92.669 34.974 92.849 ;
     RECT  38.304 92.741 39.366 92.849 ;
     RECT  45.36 92.669 46.134 92.849 ;
     RECT  52.992 92.741 53.478 92.849 ;
     RECT  57.456 92.741 57.474 92.849 ;
     RECT  61.272 92.741 62.658 92.849 ;
     RECT  65.592 92.777 69.066 92.849 ;
     RECT  70.164 92.777 70.182 92.849 ;
     RECT  79.272 92.741 79.686 92.849 ;
     RECT  81.144 92.741 82.566 92.849 ;
     RECT  88.668 92.741 89.154 92.849 ;
     RECT  90.612 92.813 91.35 92.849 ;
     RECT  4.068 92.741 4.734 92.861 ;
     RECT  9.432 92.705 11.61 92.861 ;
     RECT  16.992 92.741 17.01 92.861 ;
     RECT  18.432 92.849 20.43 92.861 ;
     RECT  25.632 92.849 26.19 92.861 ;
     RECT  30.636 92.669 32.49 92.861 ;
     RECT  38.592 92.849 39.366 92.861 ;
     RECT  42.732 92.741 43.326 92.861 ;
     RECT  47.88 92.669 48.438 92.861 ;
     RECT  49.716 92.669 49.734 92.861 ;
     RECT  50.688 92.669 51.39 92.861 ;
     RECT  58.716 92.741 58.734 92.861 ;
     RECT  65.592 92.849 67.554 92.861 ;
     RECT  74.772 92.741 75.798 92.861 ;
     RECT  76.752 92.741 76.77 92.861 ;
     RECT  87.084 92.813 87.354 92.861 ;
     RECT  90.612 92.849 90.63 92.861 ;
     RECT  2.415 92.627 2.505 92.897 ;
     RECT  24.015 92.741 24.354 92.897 ;
     RECT  45.576 92.849 45.705 92.897 ;
     RECT  56.376 92.669 56.505 92.897 ;
     RECT  71.964 92.741 73.458 92.897 ;
     RECT  78.015 92.813 78.174 92.897 ;
     RECT  9.432 92.861 9.45 92.909 ;
     RECT  10.404 92.861 10.422 92.909 ;
     RECT  12.564 92.669 13.554 92.909 ;
     RECT  14.724 92.669 14.742 92.909 ;
     RECT  16.02 92.849 16.038 92.909 ;
     RECT  22.284 92.849 23.166 92.909 ;
     RECT  27.684 92.741 28.35 92.909 ;
     RECT  29.304 92.849 29.862 92.909 ;
     RECT  31.464 92.861 31.842 92.909 ;
     RECT  36.36 92.669 36.378 92.909 ;
     RECT  38.592 92.861 38.61 92.909 ;
     RECT  39.348 92.861 39.366 92.909 ;
     RECT  40.104 92.741 40.986 92.909 ;
     RECT  48.42 92.861 48.438 92.909 ;
     RECT  71.964 92.897 71.982 92.909 ;
     RECT  74.772 92.861 75.438 92.909 ;
     RECT  5.976 92.741 6.75 92.957 ;
     RECT  28.332 92.909 28.35 92.957 ;
     RECT  30.636 92.861 30.654 92.957 ;
     RECT  82.548 92.849 82.566 92.957 ;
     RECT  7.74 92.705 8.226 93.005 ;
     RECT  13.032 92.909 13.554 93.005 ;
     RECT  18.432 92.861 19.17 93.005 ;
     RECT  24.156 92.897 24.354 93.005 ;
     RECT  29.304 92.909 29.574 93.005 ;
     RECT  34.092 92.849 34.974 93.005 ;
     RECT  40.104 92.909 40.59 93.005 ;
     RECT  50.904 92.861 51.39 93.005 ;
     RECT  61.272 92.849 62.19 93.005 ;
     RECT  66.024 92.861 67.554 93.005 ;
     RECT  72.972 92.897 73.458 93.005 ;
     RECT  83.304 92.705 83.79 93.005 ;
     RECT  88.74 92.849 89.154 93.005 ;
     RECT  7.776 93.005 8.226 93.053 ;
     RECT  13.032 93.005 13.374 93.053 ;
     RECT  18.432 93.005 19.026 93.053 ;
     RECT  22.536 92.909 23.166 93.053 ;
     RECT  24.156 93.005 24.174 93.053 ;
     RECT  29.556 93.005 29.574 93.053 ;
     RECT  34.092 93.005 34.758 93.053 ;
     RECT  45.576 92.897 45.594 93.053 ;
     RECT  50.976 93.005 50.994 93.053 ;
     RECT  56.376 92.897 56.394 93.053 ;
     RECT  66.024 93.005 67.374 93.053 ;
     RECT  73.044 93.005 73.458 93.053 ;
     RECT  78.156 92.897 78.174 93.053 ;
     RECT  88.74 93.005 88.794 93.053 ;
     RECT  7.776 93.053 7.794 93.101 ;
     RECT  88.776 93.053 88.794 93.149 ;
     RECT  11.304 92.861 11.61 93.533 ;
     RECT  13.032 93.053 13.05 93.533 ;
     RECT  26.172 92.861 26.19 93.533 ;
     RECT  31.824 92.909 31.842 93.533 ;
     RECT  34.092 93.053 34.11 93.533 ;
     RECT  54.684 92.741 54.702 93.533 ;
     RECT  60.3 92.741 60.318 93.533 ;
     RECT  61.272 93.005 61.29 93.533 ;
     RECT  66.024 93.053 66.654 93.533 ;
     RECT  71.028 92.741 71.046 93.533 ;
     RECT  73.08 93.053 73.458 93.533 ;
     RECT  81.648 92.849 81.666 93.533 ;
     RECT  85.428 92.777 85.842 93.533 ;
     RECT  5.976 92.957 6.534 93.581 ;
     RECT  11.592 93.533 11.61 93.581 ;
     RECT  6.192 93.581 6.534 94.109 ;
     RECT  20.412 92.861 20.43 94.109 ;
     RECT  22.536 93.053 22.986 94.109 ;
     RECT  42.732 92.861 42.75 94.109 ;
     RECT  52.992 92.849 53.01 94.109 ;
     RECT  66.636 93.533 66.654 94.109 ;
     RECT  69.048 92.849 69.066 94.109 ;
     RECT  73.08 93.533 73.098 94.109 ;
     RECT  85.428 93.533 85.446 94.109 ;
     RECT  6.516 94.109 6.534 94.157 ;
     RECT  8.784 94.795 8.802 94.925 ;
     RECT  64.224 94.795 64.242 94.925 ;
     RECT  76.68 94.795 76.698 94.925 ;
    LAYER M4 ;
     RECT  0.229 47.664 2.408 47.688 ;
     RECT  2.408 2.148 2.512 92.892 ;
     RECT  2.512 2.418 2.704 92.622 ;
     RECT  2.704 10.08 2.801 10.344 ;
     RECT  2.704 53.28 2.801 53.304 ;
     RECT  2.704 73.008 2.801 73.032 ;
     RECT  2.704 88.704 2.801 88.728 ;
     RECT  2.704 3.936 4.129 3.96 ;
     RECT  4.124 61.056 4.211 61.08 ;
     RECT  4.165 0.192 4.309 0.216 ;
     RECT  4.316 41.616 4.403 41.64 ;
     RECT  4.129 45.024 4.403 45.048 ;
     RECT  3.913 91.44 4.453 91.464 ;
     RECT  4.412 88.8 4.499 88.824 ;
     RECT  4.309 0.192 4.597 0.6 ;
     RECT  4.453 1.728 4.597 1.752 ;
     RECT  4.129 3.936 4.601 4.872 ;
     RECT  4.597 0.192 4.643 1.752 ;
     RECT  4.453 90.576 4.741 91.464 ;
     RECT  4.057 92.832 4.741 92.856 ;
     RECT  4.741 90.576 4.745 92.856 ;
     RECT  4.601 4.272 4.78 4.872 ;
     RECT  4.357 36.144 4.993 36.168 ;
     RECT  4.993 35.712 5.033 36.168 ;
     RECT  4.165 64.416 5.033 64.44 ;
     RECT  4.643 0.24 5.075 1.752 ;
     RECT  4.745 90.576 5.077 92.568 ;
     RECT  4.129 76.752 5.125 76.776 ;
     RECT  5.125 76.752 5.171 77.256 ;
     RECT  5.077 90 5.281 92.568 ;
     RECT  4.127 57.264 5.324 57.288 ;
     RECT  5.317 14.784 5.401 14.808 ;
     RECT  5.281 89.952 5.401 92.568 ;
     RECT  5.324 57.264 5.411 57.48 ;
     RECT  5.401 89.952 5.411 89.976 ;
     RECT  4.561 72.96 5.459 72.984 ;
     RECT  5.276 80.688 5.459 80.712 ;
     RECT  5.317 2.88 5.501 2.904 ;
     RECT  5.171 76.944 5.501 77.256 ;
     RECT  3.913 26.736 5.507 26.76 ;
     RECT  5.42 29.472 5.507 29.496 ;
     RECT  5.279 33.504 5.507 33.528 ;
     RECT  5.501 76.944 5.565 76.968 ;
     RECT  5.461 89.424 5.681 89.688 ;
     RECT  5.401 91.2 5.681 92.568 ;
     RECT  5.681 91.2 5.789 91.224 ;
     RECT  2.801 10.32 6.001 10.344 ;
     RECT  6.001 10.32 6.113 10.728 ;
     RECT  5.317 17.856 6.113 17.88 ;
     RECT  5.965 93.552 6.181 93.576 ;
     RECT  5.965 6.864 6.217 6.888 ;
     RECT  5.681 92.448 6.217 92.568 ;
     RECT  6.181 93.552 6.217 94.104 ;
     RECT  6.217 6.864 6.229 7.416 ;
     RECT  6.229 5.904 6.275 7.416 ;
     RECT  5.317 84.384 6.293 84.408 ;
     RECT  6.325 49.344 6.419 49.368 ;
     RECT  6.217 92.448 6.466 94.104 ;
     RECT  5.075 1.104 6.533 1.752 ;
     RECT  5.411 57.264 6.563 57.288 ;
     RECT  6.466 92.448 6.611 94.152 ;
     RECT  6.533 0.192 6.617 1.752 ;
     RECT  5.681 89.424 6.685 89.496 ;
     RECT  5.033 35.712 6.707 35.928 ;
     RECT  6.661 91.344 6.709 91.368 ;
     RECT  6.611 92.448 6.709 92.952 ;
     RECT  6.685 89.424 6.716 90.264 ;
     RECT  6.661 37.248 6.748 37.272 ;
     RECT  6.617 0.576 6.755 1.752 ;
     RECT  6.716 89.28 6.757 90.264 ;
     RECT  6.709 91.344 6.757 92.952 ;
     RECT  6.755 1.68 6.853 1.752 ;
     RECT  6.611 94.128 6.899 94.152 ;
     RECT  6.853 1.68 7.187 2.328 ;
     RECT  2.704 47.664 7.261 47.688 ;
     RECT  4.78 4.848 7.285 4.872 ;
     RECT  6.113 10.32 7.441 10.344 ;
     RECT  7.285 4.704 7.477 4.872 ;
     RECT  6.275 5.904 7.477 5.928 ;
     RECT  6.757 89.28 7.477 92.952 ;
     RECT  7.187 2.016 7.621 2.328 ;
     RECT  7.477 4.704 7.621 5.928 ;
     RECT  6.755 0.576 7.625 0.6 ;
     RECT  7.477 88.944 7.717 92.952 ;
     RECT  7.717 88.944 7.765 93 ;
     RECT  7.621 2.016 7.808 2.856 ;
     RECT  7.621 4.704 7.808 6.312 ;
     RECT  6.275 7.392 7.808 7.416 ;
     RECT  7.441 10.32 7.808 10.872 ;
     RECT  7.525 13.584 7.808 13.608 ;
     RECT  6.217 17.904 7.808 17.928 ;
     RECT  6.181 21.984 7.808 22.008 ;
     RECT  6.707 35.712 7.808 35.736 ;
     RECT  7.261 47.664 7.808 47.88 ;
     RECT  6.373 53.376 7.808 53.4 ;
     RECT  5.413 68.928 7.808 68.952 ;
     RECT  7.765 88.944 7.808 93.096 ;
     RECT  7.808 2.016 7.907 93.096 ;
     RECT  7.907 2.016 8.104 93.048 ;
     RECT  8.104 89.328 8.237 93.048 ;
     RECT  8.104 4.56 8.281 6.84 ;
     RECT  8.005 0.288 8.339 0.408 ;
     RECT  8.104 2.832 8.345 3.24 ;
     RECT  8.339 0.288 8.435 0.312 ;
     RECT  8.345 2.832 8.453 2.856 ;
     RECT  8.281 4.848 8.741 6.84 ;
     RECT  8.237 89.328 8.741 92.376 ;
     RECT  8.725 94.8 8.773 94.824 ;
     RECT  8.773 94.8 8.813 94.92 ;
     RECT  8.813 94.896 8.857 94.92 ;
     RECT  8.741 4.848 8.885 6.744 ;
     RECT  8.104 21.984 8.915 22.008 ;
     RECT  8.741 92.256 8.921 92.376 ;
     RECT  8.104 20.544 8.956 20.76 ;
     RECT  8.104 16.944 8.963 18.744 ;
     RECT  8.956 20.544 8.965 20.568 ;
     RECT  8.741 89.328 8.993 91.176 ;
     RECT  8.993 89.376 9.059 91.176 ;
     RECT  9.059 89.424 9.173 91.176 ;
     RECT  8.921 92.352 9.421 92.376 ;
     RECT  9.097 3.84 9.541 3.864 ;
     RECT  8.885 4.848 9.541 6.408 ;
     RECT  9.781 2.784 9.829 2.808 ;
     RECT  9.541 3.84 9.829 6.408 ;
     RECT  8.581 1.728 9.877 1.752 ;
     RECT  9.173 89.472 10.117 91.176 ;
     RECT  9.877 1.728 10.213 1.8 ;
     RECT  9.829 2.784 10.213 6.408 ;
     RECT  10.213 1.728 10.321 6.408 ;
     RECT  10.117 89.472 10.393 91.272 ;
     RECT  9.421 92.352 10.393 92.904 ;
     RECT  10.405 0.288 10.643 0.312 ;
     RECT  10.465 14.832 10.649 14.856 ;
     RECT  10.393 18.72 10.649 18.744 ;
     RECT  8.963 16.944 10.933 16.968 ;
     RECT  10.789 18 10.933 18.6 ;
     RECT  10.844 51.264 10.969 51.288 ;
     RECT  10.933 16.944 11.041 18.6 ;
     RECT  10.969 50.736 11.053 51.288 ;
     RECT  10.885 88.368 11.117 88.392 ;
     RECT  8.104 35.712 11.123 35.736 ;
     RECT  11.113 51.312 11.197 51.336 ;
     RECT  10.393 89.472 11.293 92.904 ;
     RECT  11.041 16.272 11.545 18.6 ;
     RECT  10.321 1.728 11.557 6.84 ;
     RECT  11.293 89.472 11.581 93.528 ;
     RECT  11.557 1.728 11.681 6.888 ;
     RECT  11.681 1.728 11.765 6.936 ;
     RECT  11.545 15.84 11.765 18.6 ;
     RECT  11.701 0.192 11.801 0.216 ;
     RECT  11.725 46.128 11.843 46.152 ;
     RECT  11.765 1.728 11.909 6.888 ;
     RECT  11.581 89.472 11.941 93.576 ;
     RECT  11.941 89.424 11.945 93.576 ;
     RECT  11.945 89.424 11.987 90.072 ;
     RECT  11.765 16.368 12.013 18.6 ;
     RECT  11.945 91.152 12.017 93.576 ;
     RECT  11.909 1.728 12.035 6.792 ;
     RECT  12.017 92.352 12.035 93.576 ;
     RECT  12.035 4.464 12.125 6.792 ;
     RECT  8.104 47.664 12.229 47.688 ;
     RECT  11.717 49.008 12.229 49.032 ;
     RECT  11.987 89.424 12.229 89.88 ;
     RECT  12.035 1.728 12.236 3.432 ;
     RECT  12.236 1.68 12.323 3.432 ;
     RECT  12.805 0.288 12.812 0.312 ;
     RECT  12.812 0.288 12.899 0.552 ;
     RECT  12.017 91.152 12.997 91.176 ;
     RECT  12.035 92.352 12.997 92.904 ;
     RECT  12.997 91.152 13.021 92.904 ;
     RECT  12.899 0.288 13.129 0.408 ;
     RECT  12.229 89.376 13.165 89.88 ;
     RECT  13.021 91.152 13.187 93.528 ;
     RECT  12.323 2.148 13.208 3.432 ;
     RECT  12.125 4.512 13.208 6.792 ;
     RECT  8.104 13.584 13.208 13.608 ;
     RECT  11.519 14.64 13.208 14.664 ;
     RECT  12.013 16.368 13.208 18.84 ;
     RECT  12.229 47.664 13.208 49.032 ;
     RECT  13.165 88.896 13.208 89.88 ;
     RECT  13.187 91.152 13.208 93.048 ;
     RECT  13.129 0.192 13.213 0.408 ;
     RECT  13.208 2.148 13.312 93.048 ;
     RECT  13.312 2.256 13.385 93.048 ;
     RECT  13.385 2.256 13.504 93 ;
     RECT  13.504 91.776 13.565 93 ;
     RECT  13.565 91.776 13.619 92.472 ;
     RECT  13.504 14.208 13.637 18.504 ;
     RECT  13.637 15.696 13.907 18.504 ;
     RECT  13.907 17.424 13.997 18.504 ;
     RECT  13.213 0.288 14.243 0.408 ;
     RECT  13.504 47.664 14.329 48.504 ;
     RECT  13.504 2.256 14.387 6.888 ;
     RECT  14.387 2.256 14.473 2.856 ;
     RECT  14.473 2.256 14.677 2.28 ;
     RECT  14.387 3.984 14.684 6.888 ;
     RECT  13.619 92.352 14.713 92.472 ;
     RECT  13.504 88.896 14.753 90.408 ;
     RECT  14.684 3.984 14.771 7.8 ;
     RECT  14.713 92.352 14.797 92.904 ;
     RECT  13.997 17.424 15.013 17.88 ;
     RECT  14.273 0.192 15.041 0.216 ;
     RECT  13.907 16.32 15.041 16.44 ;
     RECT  14.785 19.44 15.059 19.464 ;
     RECT  15.013 17.424 15.157 18.168 ;
     RECT  15.157 17.088 15.257 18.168 ;
     RECT  13.637 14.208 15.26 14.232 ;
     RECT  15.013 20.832 15.293 20.856 ;
     RECT  15.26 13.968 15.301 14.232 ;
     RECT  13.504 11.136 15.325 11.16 ;
     RECT  15.301 13.968 15.347 14.664 ;
     RECT  15.325 11.136 15.437 11.496 ;
     RECT  14.677 2.208 15.445 2.28 ;
     RECT  15.445 2.208 15.581 2.904 ;
     RECT  15.581 2.208 15.617 2.232 ;
     RECT  14.771 3.984 15.685 6.984 ;
     RECT  15.685 3.312 15.731 6.984 ;
     RECT  15.713 1.728 15.797 1.752 ;
     RECT  15.347 14.064 15.875 14.664 ;
     RECT  14.797 92.352 16.009 92.472 ;
     RECT  16.009 92.352 16.093 92.904 ;
     RECT  14.753 89.424 16.121 90.408 ;
     RECT  15.257 17.856 16.157 18.168 ;
     RECT  16.021 1.152 16.409 1.176 ;
     RECT  16.333 10.8 16.445 10.824 ;
     RECT  16.477 19.392 16.549 19.416 ;
     RECT  15.731 3.312 16.625 6.84 ;
     RECT  15.875 14.64 16.873 14.664 ;
     RECT  16.093 92.352 17.021 92.856 ;
     RECT  17.021 92.352 17.123 92.76 ;
     RECT  17.123 92.352 17.164 92.568 ;
     RECT  14.329 47.664 17.269 47.688 ;
     RECT  16.625 3.312 17.315 4.536 ;
     RECT  17.269 47.664 17.353 47.928 ;
     RECT  16.157 17.952 17.365 17.976 ;
     RECT  16.549 19.392 17.365 19.992 ;
     RECT  17.315 4.512 17.411 4.536 ;
     RECT  16.121 89.424 17.521 89.496 ;
     RECT  16.405 90.576 17.521 90.6 ;
     RECT  17.077 0.192 17.525 0.6 ;
     RECT  17.365 17.952 17.525 19.992 ;
     RECT  16.873 14.64 17.893 14.856 ;
     RECT  16.837 15.984 17.893 16.008 ;
     RECT  16.625 5.52 17.941 6.84 ;
     RECT  17.521 89.424 17.941 90.6 ;
     RECT  17.941 5.52 18.085 6.888 ;
     RECT  17.653 1.728 18.173 1.752 ;
     RECT  18.085 5.52 18.241 6.936 ;
     RECT  17.315 3.312 18.325 3.384 ;
     RECT  18.325 8.16 18.421 8.184 ;
     RECT  17.893 9.312 18.421 9.336 ;
     RECT  17.164 92.352 18.421 92.472 ;
     RECT  18.241 5.232 18.529 6.936 ;
     RECT  17.525 0.192 18.569 0.216 ;
     RECT  18.241 2.016 18.608 2.04 ;
     RECT  18.325 3.312 18.608 3.864 ;
     RECT  18.529 5.184 18.608 6.936 ;
     RECT  18.421 8.16 18.608 9.336 ;
     RECT  17.893 14.64 18.608 16.008 ;
     RECT  17.525 17.952 18.608 19.416 ;
     RECT  17.353 47.664 18.608 47.688 ;
     RECT  17.941 89.424 18.608 90.648 ;
     RECT  18.421 92.352 18.608 93.048 ;
     RECT  18.608 2.016 18.904 93.048 ;
     RECT  18.805 0.288 18.949 0.312 ;
     RECT  18.904 90.48 19.001 90.648 ;
     RECT  18.904 92.352 19.037 93.048 ;
     RECT  18.904 2.016 19.091 8.232 ;
     RECT  19.037 92.352 19.181 93 ;
     RECT  18.949 0.288 19.205 0.408 ;
     RECT  19.205 0.288 19.235 1.752 ;
     RECT  19.235 1.152 19.289 1.752 ;
     RECT  19.289 1.728 19.649 1.752 ;
     RECT  19.091 2.88 19.715 8.232 ;
     RECT  19.715 2.88 19.811 6.936 ;
     RECT  19.181 92.352 19.829 92.856 ;
     RECT  19.811 2.88 20.297 6.36 ;
     RECT  18.904 89.424 20.3 89.496 ;
     RECT  19.001 90.48 20.3 90.504 ;
     RECT  20.3 89.424 20.387 90.504 ;
     RECT  20.297 2.88 20.444 3.768 ;
     RECT  20.444 2.256 20.531 3.768 ;
     RECT  20.401 94.08 20.723 94.104 ;
     RECT  18.904 47.664 20.725 47.688 ;
     RECT  20.531 3.024 20.765 3.768 ;
     RECT  20.725 47.664 21.161 47.928 ;
     RECT  20.765 3.312 21.265 3.768 ;
     RECT  20.297 5.088 21.265 6.36 ;
     RECT  21.157 50.736 21.269 50.76 ;
     RECT  21.265 3.312 21.305 6.36 ;
     RECT  20.387 90.48 21.409 90.504 ;
     RECT  19.829 92.352 21.409 92.568 ;
     RECT  18.904 9.216 21.805 9.24 ;
     RECT  21.685 1.152 21.917 1.176 ;
     RECT  20.387 89.424 22.021 89.496 ;
     RECT  21.409 90.48 22.133 92.568 ;
     RECT  22.133 92.352 22.273 92.568 ;
     RECT  22.021 89.376 22.493 89.496 ;
     RECT  22.561 49.008 22.645 49.032 ;
     RECT  22.273 92.352 22.741 92.904 ;
     RECT  22.525 94.08 22.741 94.104 ;
     RECT  19.715 8.208 22.789 8.232 ;
     RECT  21.805 9.216 22.789 9.432 ;
     RECT  22.789 8.208 22.835 9.432 ;
     RECT  18.904 16.128 22.853 17.88 ;
     RECT  21.161 47.664 22.885 47.688 ;
     RECT  22.133 90.48 22.889 90.504 ;
     RECT  22.885 47.664 22.969 48.504 ;
     RECT  22.892 2.256 22.979 2.28 ;
     RECT  22.741 92.352 22.979 94.104 ;
     RECT  22.625 0.576 23.077 0.6 ;
     RECT  21.305 3.312 23.173 6.216 ;
     RECT  23.077 0.576 23.285 1.176 ;
     RECT  22.853 17.856 23.317 17.88 ;
     RECT  22.979 94.08 23.411 94.104 ;
     RECT  22.493 89.424 23.677 89.496 ;
     RECT  22.835 8.208 23.893 9.24 ;
     RECT  23.677 89.424 23.965 90.072 ;
     RECT  23.173 3.312 24.008 6.888 ;
     RECT  23.893 8.208 24.008 9.336 ;
     RECT  22.853 16.128 24.008 16.872 ;
     RECT  23.317 17.856 24.008 17.976 ;
     RECT  22.969 47.664 24.008 47.688 ;
     RECT  23.965 89.424 24.008 90.552 ;
     RECT  22.979 92.352 24.008 93.048 ;
     RECT  24.008 2.148 24.185 93.048 ;
     RECT  24.185 2.148 24.277 93 ;
     RECT  24.277 2.016 24.304 93 ;
     RECT  23.941 0.288 24.361 0.456 ;
     RECT  24.304 92.352 24.365 93 ;
     RECT  24.304 5.136 24.419 7.224 ;
     RECT  24.304 8.208 24.419 9.336 ;
     RECT  24.361 0.192 24.445 0.456 ;
     RECT  24.445 0.288 24.467 0.456 ;
     RECT  24.467 0.384 24.515 0.456 ;
     RECT  24.419 5.136 24.515 6.6 ;
     RECT  24.304 2.016 24.517 3.96 ;
     RECT  24.517 1.152 24.611 3.96 ;
     RECT  24.611 1.152 24.833 1.752 ;
     RECT  24.304 89.424 24.941 90.552 ;
     RECT  24.365 92.352 25.381 92.424 ;
     RECT  24.611 2.88 25.405 3.96 ;
     RECT  24.515 5.136 25.405 6.408 ;
     RECT  25.405 2.88 25.513 6.408 ;
     RECT  25.333 10.8 25.517 10.824 ;
     RECT  25.513 2.88 25.549 6.456 ;
     RECT  24.833 1.728 25.621 1.752 ;
     RECT  25.549 2.88 25.621 6.552 ;
     RECT  25.621 1.728 25.667 6.648 ;
     RECT  25.667 1.728 25.697 3.768 ;
     RECT  24.941 89.424 26.125 90.072 ;
     RECT  25.381 92.352 26.147 92.856 ;
     RECT  25.697 1.728 26.165 3.432 ;
     RECT  26.147 92.352 26.237 92.472 ;
     RECT  26.161 93.504 26.291 93.528 ;
     RECT  25.667 5.184 26.309 6.648 ;
     RECT  26.309 5.52 26.629 6.648 ;
     RECT  26.165 2.208 26.701 3.432 ;
     RECT  26.701 2.208 26.773 4.152 ;
     RECT  26.629 5.52 26.965 6.84 ;
     RECT  24.419 8.208 26.965 9.096 ;
     RECT  26.965 5.52 27.061 9.096 ;
     RECT  24.304 16.128 27.107 16.872 ;
     RECT  27.061 5.52 27.148 9.672 ;
     RECT  26.125 89.424 27.317 90.6 ;
     RECT  24.304 47.664 27.452 47.688 ;
     RECT  26.237 92.352 27.493 92.424 ;
     RECT  26.773 2.208 27.569 4.296 ;
     RECT  27.493 91.776 27.673 92.424 ;
     RECT  27.452 47.28 27.781 47.688 ;
     RECT  27.317 89.424 27.781 89.496 ;
     RECT  27.781 47.28 27.865 47.88 ;
     RECT  27.317 90.576 27.877 90.6 ;
     RECT  27.673 91.776 27.877 92.904 ;
     RECT  27.865 47.28 27.884 47.688 ;
     RECT  27.884 47.184 27.971 47.688 ;
     RECT  27.569 2.208 28.069 3.96 ;
     RECT  27.148 5.52 28.211 9.096 ;
     RECT  27.781 88.944 28.289 89.496 ;
     RECT  27.877 90.576 28.321 92.904 ;
     RECT  28.211 5.52 28.325 8.232 ;
     RECT  28.325 5.52 28.453 7.224 ;
     RECT  28.453 5.136 28.94 7.224 ;
     RECT  28.321 90.576 28.981 92.952 ;
     RECT  28.837 0.288 29.075 0.312 ;
     RECT  28.289 89.376 29.173 89.496 ;
     RECT  28.981 90.528 29.173 92.952 ;
     RECT  29.173 89.376 29.221 92.952 ;
     RECT  27.971 47.664 29.269 47.688 ;
     RECT  29.221 89.376 29.269 93.096 ;
     RECT  28.069 2.064 29.293 3.96 ;
     RECT  29.293 2.016 29.317 3.96 ;
     RECT  29.329 10.56 29.365 10.584 ;
     RECT  29.317 1.728 29.408 3.96 ;
     RECT  28.94 5.088 29.408 7.224 ;
     RECT  28.325 8.208 29.408 8.232 ;
     RECT  29.365 10.56 29.408 10.728 ;
     RECT  27.107 16.128 29.408 16.152 ;
     RECT  24.304 17.856 29.408 17.88 ;
     RECT  29.269 47.664 29.408 47.88 ;
     RECT  24.304 78.336 29.408 78.36 ;
     RECT  29.269 88.944 29.408 93.096 ;
     RECT  29.408 1.728 29.651 93.096 ;
     RECT  29.651 1.728 29.704 93 ;
     RECT  29.704 47.664 29.845 47.784 ;
     RECT  29.704 88.944 29.891 93 ;
     RECT  29.704 10.8 29.981 10.824 ;
     RECT  29.893 0.192 30.053 0.216 ;
     RECT  29.704 1.728 30.227 7.176 ;
     RECT  30.227 1.728 30.853 6.984 ;
     RECT  30.757 0.288 30.899 0.312 ;
     RECT  30.757 94.752 30.899 94.776 ;
     RECT  29.845 47.664 30.949 47.688 ;
     RECT  30.949 47.664 30.985 48.312 ;
     RECT  30.985 46.752 31.069 48.312 ;
     RECT  30.853 4.464 31.235 6.984 ;
     RECT  29.891 88.944 31.285 92.952 ;
     RECT  31.069 47.664 31.373 48.312 ;
     RECT  31.429 49.584 31.529 49.608 ;
     RECT  31.235 4.512 31.565 6.984 ;
     RECT  29.704 8.208 31.621 8.232 ;
     RECT  31.373 47.664 31.669 48.504 ;
     RECT  31.285 88.752 31.669 92.952 ;
     RECT  31.669 47.664 31.763 49.032 ;
     RECT  31.705 46.416 31.811 46.44 ;
     RECT  29.704 17.856 31.813 17.88 ;
     RECT  31.669 88.368 31.813 92.952 ;
     RECT  30.853 1.728 31.817 3.432 ;
     RECT  31.813 88.368 31.889 93.528 ;
     RECT  31.817 2.208 31.909 3.432 ;
     RECT  31.889 88.416 31.955 93.528 ;
     RECT  31.813 17.808 32.177 17.88 ;
     RECT  31.909 2.208 32.197 3.48 ;
     RECT  31.565 4.512 32.197 6.936 ;
     RECT  32.197 2.208 32.213 6.936 ;
     RECT  31.763 47.664 32.317 48.84 ;
     RECT  32.317 46.704 32.401 48.84 ;
     RECT  31.955 88.416 32.501 92.856 ;
     RECT  29.704 78.336 32.537 78.36 ;
     RECT  31.621 7.968 32.857 8.232 ;
     RECT  32.401 47.664 32.969 48.84 ;
     RECT  32.54 78.048 32.969 78.072 ;
     RECT  32.501 88.416 32.969 91.224 ;
     RECT  29.704 16.128 33.061 16.152 ;
     RECT  32.213 2.208 33.281 6.36 ;
     RECT  32.177 17.808 33.347 17.832 ;
     RECT  33.281 1.728 33.365 6.36 ;
     RECT  33.061 16.128 33.473 16.536 ;
     RECT  32.969 88.944 33.541 91.224 ;
     RECT  32.501 92.352 33.541 92.424 ;
     RECT  33.473 16.128 33.617 16.44 ;
     RECT  33.541 88.944 33.677 92.424 ;
     RECT  33.677 88.944 33.689 92.472 ;
     RECT  33.365 2.064 33.829 6.36 ;
     RECT  32.857 7.392 33.829 8.232 ;
     RECT  33.157 49.008 33.965 49.416 ;
     RECT  34.081 93.504 34.355 93.528 ;
     RECT  32.969 47.664 34.405 47.688 ;
     RECT  33.689 89.424 34.513 92.472 ;
     RECT  33.829 2.064 34.645 8.232 ;
     RECT  34.513 89.424 34.7 92.52 ;
     RECT  34.645 1.968 34.808 8.232 ;
     RECT  33.617 16.128 34.808 16.152 ;
     RECT  33.301 27.168 34.808 27.192 ;
     RECT  34.405 47.664 34.808 47.928 ;
     RECT  33.965 49.008 34.808 49.608 ;
     RECT  32.581 69.264 34.808 69.288 ;
     RECT  34.7 89.424 34.808 93.048 ;
     RECT  33.157 0.288 35.029 0.312 ;
     RECT  34.808 1.968 35.104 93.048 ;
     RECT  35.029 0.288 35.173 0.36 ;
     RECT  35.104 88.368 35.315 93.048 ;
     RECT  35.173 0.24 35.461 0.36 ;
     RECT  35.461 0.192 35.669 0.36 ;
     RECT  35.104 1.968 35.749 8.232 ;
     RECT  35.749 1.728 35.885 8.232 ;
     RECT  35.669 0.288 35.893 0.36 ;
     RECT  35.893 0.288 36.131 0.6 ;
     RECT  35.104 46.752 36.133 48.504 ;
     RECT  35.885 1.728 36.181 6.936 ;
     RECT  36.181 1.152 36.227 6.936 ;
     RECT  36.227 1.152 36.245 6.888 ;
     RECT  35.315 88.368 36.305 92.52 ;
     RECT  36.305 88.368 36.389 92.904 ;
     RECT  36.245 1.152 36.425 6.6 ;
     RECT  36.133 46.752 36.685 49.032 ;
     RECT  36.389 88.368 36.821 92.52 ;
     RECT  36.425 1.68 37.037 6.6 ;
     RECT  37.037 1.68 37.225 6.552 ;
     RECT  36.685 47.664 37.253 49.032 ;
     RECT  36.821 88.368 37.325 92.472 ;
     RECT  37.225 1.68 37.523 6.456 ;
     RECT  37.253 47.664 37.715 48.456 ;
     RECT  37.745 0.192 37.829 0.216 ;
     RECT  37.325 88.368 38.009 90.6 ;
     RECT  37.325 91.728 38.101 92.472 ;
     RECT  38.009 88.944 38.147 90.6 ;
     RECT  38.101 91.728 38.189 92.664 ;
     RECT  37.715 47.664 38.197 47.928 ;
     RECT  37.523 2.16 38.437 6.456 ;
     RECT  35.104 27.168 38.509 27.192 ;
     RECT  38.189 91.776 38.533 92.664 ;
     RECT  38.533 91.776 38.581 92.856 ;
     RECT  38.684 49.392 38.771 49.416 ;
     RECT  38.509 27.168 38.873 27.336 ;
     RECT  38.437 2.16 39.109 6.936 ;
     RECT  38.147 88.944 39.121 90.072 ;
     RECT  39.121 88.944 39.157 90.552 ;
     RECT  38.581 91.776 39.157 92.904 ;
     RECT  38.197 47.664 39.205 47.688 ;
     RECT  35.104 69.168 39.373 69.192 ;
     RECT  39.205 47.328 39.452 47.688 ;
     RECT  39.109 1.728 39.553 6.936 ;
     RECT  39.157 88.944 39.925 92.904 ;
     RECT  39.553 1.728 39.941 6.984 ;
     RECT  39.941 0.576 40.021 0.6 ;
     RECT  39.941 1.728 40.208 7.032 ;
     RECT  35.885 8.208 40.208 8.232 ;
     RECT  35.104 16.128 40.208 16.152 ;
     RECT  38.873 27.312 40.208 27.336 ;
     RECT  39.452 47.328 40.208 47.784 ;
     RECT  39.661 49.536 40.208 49.56 ;
     RECT  39.373 68.976 40.208 69.192 ;
     RECT  39.925 88.944 40.208 93.048 ;
     RECT  40.208 1.728 40.307 93.048 ;
     RECT  40.021 0.288 40.451 0.6 ;
     RECT  40.307 1.728 40.504 93 ;
     RECT  40.504 92.352 40.636 93 ;
     RECT  40.504 49.008 40.643 49.032 ;
     RECT  40.504 1.728 40.673 6.936 ;
     RECT  40.451 0.576 40.693 0.6 ;
     RECT  40.693 0.576 40.889 1.176 ;
     RECT  40.889 0.576 40.925 0.6 ;
     RECT  40.636 92.352 41.027 92.904 ;
     RECT  40.504 88.944 41.033 91.368 ;
     RECT  41.033 89.424 41.357 91.368 ;
     RECT  41.677 50.16 41.761 50.184 ;
     RECT  40.504 47.664 41.857 47.688 ;
     RECT  41.357 89.424 41.884 91.32 ;
     RECT  40.673 2.208 42.149 6.936 ;
     RECT  42.149 2.208 42.277 6.888 ;
     RECT  41.884 89.712 42.473 91.32 ;
     RECT  41.857 47.664 42.689 48.504 ;
     RECT  40.504 27.312 42.757 27.336 ;
     RECT  42.757 27.168 42.797 27.336 ;
     RECT  42.721 94.08 42.899 94.104 ;
     RECT  41.027 92.352 43.141 92.472 ;
     RECT  43.141 92.352 43.225 92.856 ;
     RECT  42.277 2.16 43.253 6.888 ;
     RECT  43.225 91.776 43.309 92.856 ;
     RECT  43.309 91.92 43.331 92.856 ;
     RECT  43.253 1.728 43.337 6.888 ;
     RECT  43.331 92.352 43.337 92.856 ;
     RECT  43.337 2.16 43.373 6.888 ;
     RECT  42.689 47.664 43.573 47.688 ;
     RECT  43.373 2.208 43.769 6.888 ;
     RECT  43.769 2.208 43.921 3.432 ;
     RECT  43.573 46.752 44.005 47.688 ;
     RECT  43.921 2.208 44.345 2.328 ;
     RECT  42.473 89.712 44.389 90.552 ;
     RECT  43.337 92.352 44.389 92.568 ;
     RECT  44.293 0.288 44.435 0.312 ;
     RECT  44.389 88.896 44.476 90.552 ;
     RECT  44.345 2.208 44.489 2.28 ;
     RECT  43.769 4.512 44.489 6.888 ;
     RECT  44.476 89.424 44.593 90.552 ;
     RECT  43.921 3.312 44.633 3.432 ;
     RECT  44.593 89.424 44.732 91.08 ;
     RECT  44.732 89.424 44.965 91.128 ;
     RECT  44.965 89.424 45.169 91.224 ;
     RECT  44.389 92.304 45.169 92.568 ;
     RECT  45.169 89.424 45.541 92.568 ;
     RECT  44.965 1.728 45.608 2.04 ;
     RECT  44.633 3.312 45.608 3.336 ;
     RECT  44.489 4.512 45.608 6.84 ;
     RECT  40.504 8.208 45.608 8.232 ;
     RECT  40.504 16.128 45.608 16.152 ;
     RECT  42.797 27.168 45.608 27.192 ;
     RECT  44.005 46.752 45.608 47.976 ;
     RECT  44.845 49.008 45.608 49.032 ;
     RECT  40.504 68.976 45.608 69 ;
     RECT  44.869 88.368 45.608 88.392 ;
     RECT  45.541 89.424 45.608 93.048 ;
     RECT  45.685 0.288 45.829 0.312 ;
     RECT  45.608 1.728 45.829 93.048 ;
     RECT  45.829 1.728 45.904 93.144 ;
     RECT  45.904 88.944 45.973 93.144 ;
     RECT  45.829 0.288 46.019 0.552 ;
     RECT  45.904 47.28 46.045 47.928 ;
     RECT  46.019 0.288 46.109 0.456 ;
     RECT  45.904 5.376 46.109 7.224 ;
     RECT  46.109 0.288 46.115 0.312 ;
     RECT  45.904 49.008 46.115 49.032 ;
     RECT  45.973 88.944 46.115 93.24 ;
     RECT  46.115 88.944 46.325 92.52 ;
     RECT  46.045 47.664 46.585 47.928 ;
     RECT  45.904 1.728 46.613 1.8 ;
     RECT  46.325 88.944 46.643 91.32 ;
     RECT  46.613 1.728 46.721 1.752 ;
     RECT  45.904 27.168 46.787 27.336 ;
     RECT  46.109 5.376 46.835 7.08 ;
     RECT  45.904 35.568 46.933 35.592 ;
     RECT  46.933 35.328 47.017 35.592 ;
     RECT  45.904 3.312 47.077 4.104 ;
     RECT  46.969 10.8 47.117 10.824 ;
     RECT  46.835 5.376 47.269 6.312 ;
     RECT  46.643 88.944 47.293 89.496 ;
     RECT  46.585 47.664 47.545 47.88 ;
     RECT  46.325 92.352 47.557 92.52 ;
     RECT  47.017 35.568 47.603 35.592 ;
     RECT  47.293 88.896 47.605 89.496 ;
     RECT  46.643 90.528 47.605 91.32 ;
     RECT  47.509 61.008 47.657 61.032 ;
     RECT  47.545 47.28 47.747 47.88 ;
     RECT  47.077 3.312 47.761 4.152 ;
     RECT  47.269 5.184 47.761 6.312 ;
     RECT  47.761 3.312 47.797 6.312 ;
     RECT  47.605 88.896 47.837 91.32 ;
     RECT  47.747 47.376 47.843 47.88 ;
     RECT  47.557 92.352 47.845 92.568 ;
     RECT  47.797 61.536 47.881 61.56 ;
     RECT  47.843 47.664 47.909 47.88 ;
     RECT  47.701 1.728 47.989 1.752 ;
     RECT  47.989 1.152 48.017 1.752 ;
     RECT  47.837 88.896 48.085 91.224 ;
     RECT  47.797 2.736 48.124 6.312 ;
     RECT  47.909 47.856 48.233 47.88 ;
     RECT  48.124 2.736 48.277 6.36 ;
     RECT  47.845 92.352 48.409 92.856 ;
     RECT  48.017 1.152 48.449 1.176 ;
     RECT  48.085 88.848 48.469 91.224 ;
     RECT  48.409 92.352 48.493 92.904 ;
     RECT  48.013 49.008 48.524 49.032 ;
     RECT  45.904 8.208 48.661 8.232 ;
     RECT  48.277 2.304 48.709 6.36 ;
     RECT  48.709 2.304 48.805 6.408 ;
     RECT  48.469 88.368 48.841 91.224 ;
     RECT  48.493 92.352 48.841 92.568 ;
     RECT  48.524 48.432 48.995 49.032 ;
     RECT  48.995 49.008 49.093 49.032 ;
     RECT  48.661 8.208 49.169 8.568 ;
     RECT  48.805 2.304 49.277 6.456 ;
     RECT  49.093 49.008 49.349 49.128 ;
     RECT  49.277 2.88 49.493 6.456 ;
     RECT  49.493 3.312 49.525 6.456 ;
     RECT  49.489 47.856 49.573 47.88 ;
     RECT  48.841 88.368 49.621 92.568 ;
     RECT  49.525 3.312 49.673 6.84 ;
     RECT  49.349 49.008 49.681 49.032 ;
     RECT  49.621 88.368 49.889 92.856 ;
     RECT  49.673 3.312 50.569 6.216 ;
     RECT  49.169 8.208 50.741 8.232 ;
     RECT  50.725 0.336 50.821 0.36 ;
     RECT  50.569 2.832 50.821 6.216 ;
     RECT  50.741 7.968 50.849 8.232 ;
     RECT  50.821 0.288 50.869 0.36 ;
     RECT  49.889 89.424 50.876 92.856 ;
     RECT  50.876 89.424 50.962 93 ;
     RECT  50.821 2.832 51.008 6.984 ;
     RECT  50.849 7.968 51.008 8.568 ;
     RECT  45.904 16.128 51.008 16.152 ;
     RECT  46.787 27.312 51.008 27.336 ;
     RECT  50.101 47.904 51.008 47.928 ;
     RECT  45.904 68.976 51.008 69 ;
     RECT  49.889 88.368 51.008 88.392 ;
     RECT  50.962 89.424 51.008 93.048 ;
     RECT  51.008 2.148 51.107 93.048 ;
     RECT  50.869 0.288 51.251 0.408 ;
     RECT  51.107 2.148 51.304 93 ;
     RECT  51.304 89.424 51.436 93 ;
     RECT  51.317 0.192 51.581 0.216 ;
     RECT  51.304 47.904 52.021 47.928 ;
     RECT  51.304 49.392 52.067 49.416 ;
     RECT  51.436 89.424 52.358 92.568 ;
     RECT  52.358 89.424 52.444 92.52 ;
     RECT  51.304 88.368 52.621 88.392 ;
     RECT  52.444 89.424 52.621 92.424 ;
     RECT  52.621 47.28 52.739 47.304 ;
     RECT  52.981 94.08 53.267 94.104 ;
     RECT  51.637 1.728 53.269 1.752 ;
     RECT  52.621 88.368 53.509 92.424 ;
     RECT  53.269 1.728 53.557 2.28 ;
     RECT  51.304 3.312 53.557 7.128 ;
     RECT  53.557 1.728 53.561 7.128 ;
     RECT  53.509 88.368 53.929 92.472 ;
     RECT  53.929 92.352 53.941 92.472 ;
     RECT  53.929 88.368 54.209 91.224 ;
     RECT  54.209 88.896 54.317 91.224 ;
     RECT  54.385 49.008 54.469 49.032 ;
     RECT  54.317 88.944 54.497 91.224 ;
     RECT  54.497 88.944 54.659 90.408 ;
     RECT  53.941 92.352 54.673 92.568 ;
     RECT  51.304 27.312 54.749 27.336 ;
     RECT  54.673 92.352 54.803 93.528 ;
     RECT  54.517 46.752 54.821 46.776 ;
     RECT  53.561 2.208 54.901 7.128 ;
     RECT  54.817 48.48 54.901 48.504 ;
     RECT  54.901 1.728 54.929 7.128 ;
     RECT  54.961 50.16 55.045 50.184 ;
     RECT  54.659 88.944 55.289 90.168 ;
     RECT  55.289 89.424 55.813 90.168 ;
     RECT  55.813 89.424 55.969 91.08 ;
     RECT  54.929 1.728 56.053 6.84 ;
     RECT  56.053 1.728 56.141 6.888 ;
     RECT  56.101 0.288 56.293 0.312 ;
     RECT  54.803 92.352 56.341 92.568 ;
     RECT  56.141 1.728 56.408 6.936 ;
     RECT  51.304 8.208 56.408 8.232 ;
     RECT  51.304 16.128 56.408 16.152 ;
     RECT  55.393 49.584 56.408 49.608 ;
     RECT  51.304 68.976 56.408 69 ;
     RECT  55.969 89.424 56.408 91.176 ;
     RECT  56.341 92.352 56.408 93.048 ;
     RECT  56.293 0.288 56.485 0.552 ;
     RECT  56.408 1.728 56.629 93.048 ;
     RECT  56.629 1.728 56.704 93.144 ;
     RECT  56.704 89.376 56.773 93.144 ;
     RECT  56.704 69.36 56.86 69.384 ;
     RECT  56.704 79.44 56.909 80.952 ;
     RECT  56.773 89.376 56.915 93.24 ;
     RECT  56.915 89.376 56.981 92.568 ;
     RECT  56.485 0.288 57.02 0.6 ;
     RECT  56.704 1.728 57.02 6.936 ;
     RECT  57.02 0.288 57.107 6.936 ;
     RECT  56.704 46.752 57.169 46.776 ;
     RECT  56.909 80.928 57.277 80.952 ;
     RECT  57.107 0.288 57.299 0.312 ;
     RECT  57.107 1.728 57.485 6.936 ;
     RECT  57.485 2.208 57.539 6.936 ;
     RECT  56.981 89.376 57.601 92.52 ;
     RECT  57.539 3.312 57.665 6.936 ;
     RECT  57.539 2.208 57.917 2.28 ;
     RECT  58.193 48.48 58.268 48.504 ;
     RECT  57.601 89.376 58.309 92.472 ;
     RECT  58.268 47.856 58.355 48.504 ;
     RECT  58.355 48.48 58.465 48.504 ;
     RECT  57.665 3.312 58.549 6.504 ;
     RECT  58.309 88.944 58.637 92.472 ;
     RECT  58.637 89.424 58.681 92.472 ;
     RECT  58.681 92.352 58.705 92.472 ;
     RECT  58.549 2.496 58.741 6.504 ;
     RECT  58.741 2.496 58.861 6.792 ;
     RECT  58.861 5.088 58.885 6.792 ;
     RECT  58.789 49.008 58.997 49.032 ;
     RECT  58.885 5.088 59.029 6.84 ;
     RECT  58.861 2.496 59.101 4.008 ;
     RECT  59.029 5.088 59.125 6.888 ;
     RECT  59.101 2.256 59.184 4.008 ;
     RECT  59.184 2.208 59.222 4.008 ;
     RECT  59.029 0.288 59.267 0.312 ;
     RECT  58.705 92.352 59.267 92.856 ;
     RECT  59.267 92.352 59.321 92.52 ;
     RECT  59.222 2.208 59.345 3.96 ;
     RECT  59.345 1.728 59.429 3.96 ;
     RECT  59.125 5.088 59.603 7.032 ;
     RECT  59.603 5.136 59.797 7.032 ;
     RECT  60.092 1.104 60.179 1.128 ;
     RECT  58.681 89.424 60.181 91.128 ;
     RECT  59.321 92.352 60.181 92.472 ;
     RECT  60.181 88.944 60.227 92.472 ;
     RECT  60.181 49.536 60.265 49.56 ;
     RECT  60.227 90.528 60.353 92.472 ;
     RECT  60.353 90.528 60.437 92.52 ;
     RECT  59.557 47.904 60.505 47.928 ;
     RECT  60.505 47.28 60.589 47.928 ;
     RECT  59.429 2.112 60.617 3.96 ;
     RECT  60.565 0.192 60.653 0.216 ;
     RECT  60.617 2.256 60.865 3.96 ;
     RECT  59.797 5.136 60.865 7.128 ;
     RECT  60.227 88.944 60.937 89.496 ;
     RECT  60.937 88.896 61.093 89.496 ;
     RECT  60.589 47.76 61.292 47.928 ;
     RECT  60.469 49.008 61.292 49.032 ;
     RECT  61.093 88.368 61.381 89.496 ;
     RECT  60.437 90.528 61.381 92.472 ;
     RECT  61.381 88.368 61.669 92.472 ;
     RECT  60.289 93.504 61.669 93.528 ;
     RECT  61.669 88.368 61.763 93.528 ;
     RECT  61.717 1.2 61.805 1.224 ;
     RECT  60.865 2.256 61.808 7.128 ;
     RECT  56.704 8.208 61.808 8.232 ;
     RECT  56.704 16.128 61.808 16.152 ;
     RECT  60.908 17.616 61.808 17.64 ;
     RECT  56.704 27.312 61.808 27.336 ;
     RECT  61.292 47.76 61.808 49.032 ;
     RECT  56.909 79.44 61.808 79.464 ;
     RECT  61.763 88.368 61.808 93.048 ;
     RECT  61.808 1.728 61.907 93.048 ;
     RECT  61.907 1.728 62.104 93 ;
     RECT  62.104 88.944 62.236 93 ;
     RECT  62.236 88.944 62.417 92.52 ;
     RECT  62.149 0.288 62.483 0.312 ;
     RECT  62.104 49.008 62.525 49.56 ;
     RECT  62.525 49.536 62.531 49.56 ;
     RECT  62.104 1.728 62.569 8.232 ;
     RECT  62.104 16.128 62.569 16.584 ;
     RECT  62.569 1.728 62.705 6.984 ;
     RECT  62.104 79.776 62.893 79.8 ;
     RECT  62.417 89.136 62.893 92.52 ;
     RECT  62.705 2.112 63.209 6.984 ;
     RECT  62.104 47.28 63.673 47.88 ;
     RECT  63.209 2.112 63.877 6.888 ;
     RECT  63.877 1.152 63.965 6.888 ;
     RECT  63.965 1.152 63.989 1.176 ;
     RECT  63.673 47.28 64.045 48.504 ;
     RECT  63.989 0.24 64.109 1.176 ;
     RECT  64.109 0.24 64.115 0.408 ;
     RECT  64.115 0.24 64.165 0.312 ;
     RECT  62.893 89.136 64.213 92.424 ;
     RECT  64.165 94.8 64.213 94.824 ;
     RECT  64.165 0.192 64.217 0.312 ;
     RECT  64.217 0.192 64.252 0.216 ;
     RECT  64.213 94.8 64.253 94.92 ;
     RECT  64.045 47.856 64.261 48.504 ;
     RECT  64.253 94.896 64.297 94.92 ;
     RECT  64.213 89.04 64.321 92.424 ;
     RECT  64.321 89.04 64.361 92.568 ;
     RECT  64.261 48.48 64.441 48.504 ;
     RECT  63.965 2.688 64.597 6.888 ;
     RECT  64.597 2.688 64.609 6.936 ;
     RECT  64.361 89.04 64.645 91.224 ;
     RECT  62.569 8.208 64.933 8.232 ;
     RECT  64.609 2.688 65.009 6.984 ;
     RECT  64.645 88.992 65.045 91.224 ;
     RECT  65.009 2.832 65.233 6.984 ;
     RECT  65.045 88.992 65.269 90.408 ;
     RECT  64.609 49.008 65.485 49.032 ;
     RECT  65.233 2.88 65.507 6.984 ;
     RECT  64.361 92.352 65.557 92.568 ;
     RECT  65.653 1.68 65.701 1.704 ;
     RECT  65.269 88.944 65.765 90.408 ;
     RECT  65.557 92.352 65.833 92.856 ;
     RECT  64.933 8.208 65.837 8.568 ;
     RECT  65.701 1.152 65.945 1.704 ;
     RECT  65.833 91.728 65.945 92.856 ;
     RECT  65.933 48.48 66.017 48.504 ;
     RECT  65.945 91.728 66.035 92.424 ;
     RECT  65.507 2.88 66.445 6.888 ;
     RECT  66.133 90.528 66.445 90.552 ;
     RECT  66.013 93.504 66.467 93.528 ;
     RECT  66.625 94.08 66.755 94.104 ;
     RECT  66.445 1.728 66.901 6.888 ;
     RECT  65.765 88.944 67.045 89.544 ;
     RECT  66.445 90.528 67.045 90.6 ;
     RECT  66.035 91.776 67.141 92.424 ;
     RECT  66.901 1.728 67.208 7.224 ;
     RECT  65.837 8.208 67.208 8.232 ;
     RECT  62.569 16.128 67.208 16.152 ;
     RECT  62.104 17.616 67.208 17.64 ;
     RECT  66.469 49.008 67.208 49.032 ;
     RECT  67.045 88.944 67.208 90.6 ;
     RECT  67.141 91.776 67.208 93.048 ;
     RECT  67.208 1.728 67.385 93.048 ;
     RECT  67.285 0.288 67.429 0.312 ;
     RECT  67.385 1.728 67.429 93 ;
     RECT  67.429 0.288 67.504 93 ;
     RECT  67.504 89.424 67.565 93 ;
     RECT  67.504 0.288 67.709 8.232 ;
     RECT  67.709 1.728 67.717 8.232 ;
     RECT  67.565 89.424 67.781 92.568 ;
     RECT  67.717 1.728 67.789 2.28 ;
     RECT  67.709 0.288 67.811 0.312 ;
     RECT  67.781 91.44 68.213 92.568 ;
     RECT  67.789 1.728 68.393 1.8 ;
     RECT  67.504 47.904 68.789 47.928 ;
     RECT  68.393 1.728 69.013 1.752 ;
     RECT  67.717 3.312 69.041 8.232 ;
     RECT  69.013 1.152 69.221 1.752 ;
     RECT  69.217 47.328 69.301 47.352 ;
     RECT  67.781 89.424 69.581 90.408 ;
     RECT  68.213 91.44 69.617 92.424 ;
     RECT  69.041 5.088 69.761 8.232 ;
     RECT  69.221 1.152 69.869 1.176 ;
     RECT  69.617 92.352 69.877 92.424 ;
     RECT  67.504 17.616 70.019 17.64 ;
     RECT  69.037 94.08 70.067 94.104 ;
     RECT  70.037 47.904 70.121 47.928 ;
     RECT  69.877 92.352 70.121 92.472 ;
     RECT  70.309 1.728 70.445 1.752 ;
     RECT  69.761 5.088 70.453 6.888 ;
     RECT  69.581 89.424 70.841 90.072 ;
     RECT  69.041 3.312 70.981 3.96 ;
     RECT  70.453 5.088 70.981 6.792 ;
     RECT  70.165 92.544 71.017 92.568 ;
     RECT  67.504 16.128 71.027 16.152 ;
     RECT  71.017 92.544 71.18 93.528 ;
     RECT  69.761 8.208 71.219 8.232 ;
     RECT  70.841 89.424 71.269 89.784 ;
     RECT  71.18 92.352 71.411 93.528 ;
     RECT  71.509 0.192 71.777 0.216 ;
     RECT  71.653 2.304 71.797 2.328 ;
     RECT  70.981 3.312 71.797 6.792 ;
     RECT  71.797 1.728 72.317 2.328 ;
     RECT  71.269 88.848 72.373 89.784 ;
     RECT  72.341 91.2 72.421 91.224 ;
     RECT  71.411 92.352 72.421 92.904 ;
     RECT  72.421 91.2 72.469 93 ;
     RECT  72.373 0.24 72.577 1.176 ;
     RECT  72.317 2.148 72.608 2.328 ;
     RECT  71.797 3.312 72.608 6.84 ;
     RECT  71.665 49.584 72.608 49.608 ;
     RECT  72.373 88.848 72.608 90.024 ;
     RECT  72.469 91.2 72.608 93.096 ;
     RECT  72.577 0.288 72.785 1.176 ;
     RECT  72.785 0.288 72.851 0.312 ;
     RECT  72.608 2.148 72.904 93.096 ;
     RECT  73.052 94.08 73.139 94.104 ;
     RECT  72.904 10.8 73.325 10.824 ;
     RECT  72.904 89.232 73.429 93.096 ;
     RECT  72.904 49.008 73.549 49.032 ;
     RECT  73.493 1.728 73.577 1.752 ;
     RECT  73.429 89.232 73.715 93.528 ;
     RECT  73.715 89.232 73.859 92.952 ;
     RECT  72.904 2.88 73.868 6.36 ;
     RECT  73.868 2.88 73.955 6.552 ;
     RECT  73.955 2.88 73.957 6.36 ;
     RECT  73.859 89.232 74.005 91.32 ;
     RECT  73.859 92.352 74.147 92.952 ;
     RECT  74.101 1.152 74.243 1.176 ;
     RECT  73.957 2.16 74.333 6.36 ;
     RECT  74.3 7.344 74.387 7.368 ;
     RECT  74.677 0.576 74.909 0.6 ;
     RECT  74.333 2.304 74.945 6.36 ;
     RECT  74.365 10.8 74.945 10.824 ;
     RECT  74.945 2.4 74.965 6.36 ;
     RECT  74.147 92.352 75.049 92.904 ;
     RECT  74.761 49.536 75.107 49.56 ;
     RECT  74.965 2.4 75.125 6.936 ;
     RECT  74.005 89.088 75.157 91.32 ;
     RECT  75.049 92.304 75.157 92.904 ;
     RECT  75.121 48.48 75.212 48.504 ;
     RECT  75.125 2.4 75.233 6.888 ;
     RECT  75.121 47.28 75.251 47.304 ;
     RECT  75.212 48.48 75.299 48.84 ;
     RECT  75.299 48.48 75.565 48.504 ;
     RECT  75.157 89.088 76.357 92.904 ;
     RECT  76.357 88.896 76.403 92.904 ;
     RECT  76.357 1.152 76.46 1.176 ;
     RECT  75.233 2.4 76.565 6.6 ;
     RECT  76.597 48.144 76.669 48.168 ;
     RECT  76.645 94.8 76.669 94.824 ;
     RECT  76.669 47.376 76.705 48.168 ;
     RECT  76.117 49.584 76.705 49.608 ;
     RECT  76.669 94.8 76.732 94.92 ;
     RECT  76.732 94.896 76.753 94.92 ;
     RECT  76.565 3.312 76.789 6.6 ;
     RECT  76.705 47.28 76.835 49.608 ;
     RECT  76.403 88.896 76.835 92.856 ;
     RECT  76.835 88.896 76.844 92.472 ;
     RECT  76.844 88.848 76.885 92.472 ;
     RECT  76.835 48.144 76.931 49.608 ;
     RECT  76.931 48.144 77.041 48.504 ;
     RECT  76.46 1.104 77.281 1.176 ;
     RECT  77.281 0.528 77.285 1.176 ;
     RECT  76.933 2.304 77.461 2.328 ;
     RECT  77.285 0.528 77.555 0.552 ;
     RECT  76.789 3.312 77.653 6.888 ;
     RECT  77.653 3.312 77.677 6.936 ;
     RECT  76.885 88.368 77.845 92.472 ;
     RECT  77.461 1.728 78.008 2.328 ;
     RECT  77.677 3.312 78.008 7.032 ;
     RECT  77.041 48.144 78.008 48.168 ;
     RECT  76.931 49.584 78.008 49.608 ;
     RECT  77.845 88.368 78.008 93.048 ;
     RECT  78.008 1.728 78.185 93.048 ;
     RECT  78.185 1.728 78.304 93 ;
     RECT  78.373 0.288 78.517 0.312 ;
     RECT  78.304 88.368 78.611 93 ;
     RECT  78.517 0.288 78.659 0.36 ;
     RECT  78.611 88.368 78.689 92.568 ;
     RECT  78.304 46.656 78.755 46.68 ;
     RECT  78.659 0.336 78.947 0.36 ;
     RECT  78.304 1.728 79.297 6.888 ;
     RECT  78.689 92.352 79.379 92.568 ;
     RECT  78.304 48.144 79.436 48.936 ;
     RECT  79.297 1.728 79.445 6.936 ;
     RECT  79.436 48.144 79.523 49.56 ;
     RECT  79.523 48.144 79.628 49.032 ;
     RECT  79.628 47.856 79.724 49.032 ;
     RECT  78.689 88.368 79.765 91.368 ;
     RECT  79.379 92.352 79.765 92.472 ;
     RECT  79.724 47.28 79.769 49.032 ;
     RECT  79.769 47.28 79.811 48.84 ;
     RECT  79.445 2.16 80.413 6.936 ;
     RECT  80.413 2.16 80.497 6.984 ;
     RECT  79.765 88.368 80.533 92.472 ;
     RECT  80.497 2.16 80.597 6.888 ;
     RECT  79.811 47.856 80.675 48.84 ;
     RECT  80.597 2.16 80.677 6.84 ;
     RECT  80.677 1.728 80.78 6.84 ;
     RECT  80.701 10.8 80.813 10.824 ;
     RECT  80.675 47.856 80.821 48.552 ;
     RECT  80.533 88.368 80.869 92.568 ;
     RECT  80.821 47.856 80.893 48.456 ;
     RECT  80.893 48.432 80.915 48.456 ;
     RECT  80.869 87.792 80.924 92.568 ;
     RECT  80.78 1.68 81.101 6.84 ;
     RECT  79.669 0.288 81.109 0.312 ;
     RECT  81.101 1.68 81.109 6.36 ;
     RECT  81.109 0.288 81.137 6.36 ;
     RECT  81.137 0.288 81.203 6.312 ;
     RECT  81.203 1.152 81.209 6.312 ;
     RECT  81.209 1.152 81.245 1.176 ;
     RECT  80.924 87.792 81.637 92.664 ;
     RECT  81.733 7.44 81.817 7.464 ;
     RECT  81.637 87.792 81.857 93.528 ;
     RECT  81.817 7.44 81.901 7.512 ;
     RECT  81.857 88.368 81.965 93.528 ;
     RECT  81.884 48.816 81.971 48.84 ;
     RECT  81.901 7.44 82.001 7.464 ;
     RECT  81.209 2.256 82.165 6.312 ;
     RECT  81.965 88.416 82.499 93.528 ;
     RECT  82.165 2.256 82.565 6.936 ;
     RECT  82.499 88.416 83.269 93.096 ;
     RECT  82.565 1.728 83.408 6.936 ;
     RECT  81.205 46.752 83.408 46.776 ;
     RECT  83.269 47.76 83.408 47.784 ;
     RECT  82.46 49.92 83.408 49.944 ;
     RECT  83.269 88.368 83.408 93.096 ;
     RECT  83.408 1.728 83.507 93.096 ;
     RECT  83.507 1.728 83.704 93 ;
     RECT  83.704 88.368 83.836 93 ;
     RECT  83.269 0.288 83.893 0.312 ;
     RECT  83.893 0.192 83.981 0.312 ;
     RECT  83.981 0.288 84.131 0.312 ;
     RECT  83.704 10.8 84.161 10.824 ;
     RECT  83.704 1.728 84.341 6.936 ;
     RECT  84.341 1.728 84.521 6.888 ;
     RECT  83.836 88.368 84.629 92.472 ;
     RECT  84.629 91.776 84.659 92.472 ;
     RECT  84.613 0.576 84.737 1.176 ;
     RECT  83.704 47.28 84.841 47.304 ;
     RECT  84.737 0.576 84.917 0.6 ;
     RECT  84.841 46.752 85.021 47.304 ;
     RECT  83.704 48.432 85.021 48.456 ;
     RECT  85.021 46.752 85.177 48.456 ;
     RECT  84.659 92.352 85.177 92.472 ;
     RECT  85.177 48.432 85.235 48.456 ;
     RECT  85.417 94.08 85.523 94.104 ;
     RECT  85.525 48.48 85.609 48.504 ;
     RECT  84.521 2.16 85.669 6.888 ;
     RECT  85.177 46.752 85.717 47.352 ;
     RECT  84.629 88.368 85.777 90.744 ;
     RECT  85.717 47.184 85.897 47.352 ;
     RECT  85.177 92.352 85.909 92.424 ;
     RECT  85.777 88.368 86.005 91.224 ;
     RECT  85.909 92.256 86.005 92.424 ;
     RECT  85.813 93.504 86.099 93.528 ;
     RECT  85.669 2.16 86.147 7.416 ;
     RECT  86.147 2.16 86.573 2.328 ;
     RECT  86.147 3.312 86.681 7.416 ;
     RECT  86.005 88.368 86.825 92.424 ;
     RECT  86.825 88.896 87.073 92.424 ;
     RECT  86.573 2.16 87.301 2.28 ;
     RECT  86.869 46.176 87.365 46.2 ;
     RECT  85.897 47.184 87.445 47.208 ;
     RECT  87.301 1.728 87.761 2.28 ;
     RECT  87.073 88.896 87.833 92.856 ;
     RECT  86.681 3.312 87.893 6.36 ;
     RECT  86.681 7.392 87.893 7.416 ;
     RECT  87.865 0.192 87.949 0.216 ;
     RECT  87.761 1.776 88.021 2.28 ;
     RECT  87.445 47.184 88.364 47.4 ;
     RECT  87.833 88.896 88.477 89.544 ;
     RECT  88.364 47.184 88.549 47.88 ;
     RECT  88.549 47.184 88.597 48.84 ;
     RECT  88.477 88.848 88.645 89.544 ;
     RECT  88.021 1.776 88.693 2.328 ;
     RECT  87.893 3.312 88.693 7.416 ;
     RECT  88.645 88.8 88.693 89.544 ;
     RECT  87.833 90.576 88.7 92.856 ;
     RECT  88.693 1.776 88.741 7.416 ;
     RECT  88.7 90.576 88.765 93.048 ;
     RECT  88.741 1.728 88.808 7.416 ;
     RECT  88.153 10.8 88.808 10.824 ;
     RECT  88.597 47.184 88.808 49.512 ;
     RECT  88.009 76.32 88.808 76.344 ;
     RECT  88.693 88.368 88.808 89.544 ;
     RECT  88.765 90.576 88.808 93.144 ;
     RECT  88.693 0.288 88.931 0.312 ;
     RECT  88.808 1.728 88.931 93.144 ;
     RECT  88.931 1.728 89.104 93 ;
     RECT  89.104 88.368 89.165 93 ;
     RECT  89.029 0.576 89.173 0.6 ;
     RECT  89.104 1.728 89.173 3.336 ;
     RECT  89.104 4.752 89.201 6.312 ;
     RECT  89.165 88.368 89.315 92.712 ;
     RECT  89.104 47.28 89.317 47.304 ;
     RECT  89.104 83.184 89.555 83.688 ;
     RECT  89.315 88.368 89.561 92.52 ;
     RECT  89.104 76.32 89.603 76.344 ;
     RECT  89.555 83.664 89.603 83.688 ;
     RECT  89.201 4.896 89.741 6.312 ;
     RECT  89.173 0.576 89.795 3.336 ;
     RECT  89.741 4.896 90.137 6.024 ;
     RECT  90.137 4.896 90.245 5.928 ;
     RECT  89.795 0.576 90.461 0.6 ;
     RECT  89.795 1.728 90.469 3.336 ;
     RECT  89.561 88.944 90.469 92.52 ;
     RECT  90.469 88.944 90.641 92.856 ;
     RECT  90.641 88.944 90.821 92.568 ;
     RECT  90.821 88.944 90.857 90.552 ;
     RECT  90.097 7.392 90.899 7.416 ;
     RECT  90.817 18.24 90.901 18.264 ;
     RECT  90.857 88.944 91.037 90.12 ;
     RECT  90.245 5.088 91.073 5.928 ;
     RECT  91.037 89.952 91.109 90.12 ;
     RECT  91.037 88.944 91.145 88.968 ;
     RECT  91.109 89.952 91.325 90.072 ;
     RECT  90.821 91.728 91.325 91.8 ;
     RECT  91.325 90.048 91.475 90.072 ;
     RECT  91.325 91.776 91.513 91.8 ;
     RECT  90.469 1.728 91.573 3.864 ;
     RECT  91.573 1.728 91.793 4.008 ;
     RECT  91.793 2.592 92.261 4.008 ;
     RECT  92.261 2.928 92.297 4.008 ;
     RECT  92.297 3.984 92.405 4.008 ;
     RECT  92.297 2.928 92.477 2.952 ;
    LAYER M5 ;
     RECT  4.32 0.144 90.648 0.611 ;
     RECT  4.464 0.611 90.648 1.763 ;
     RECT  2.4 2.137 2.52 2.151 ;
     RECT  6.864 1.763 90.504 2.339 ;
     RECT  7.296 2.339 90.504 2.531 ;
     RECT  90.48 2.531 90.504 2.821 ;
     RECT  91.584 2.245 91.608 2.821 ;
     RECT  5.328 1.763 5.352 2.915 ;
     RECT  90.48 2.821 91.608 2.963 ;
     RECT  90.48 2.963 90.504 3.875 ;
     RECT  91.584 2.963 91.608 4.019 ;
     RECT  7.296 2.531 89.496 4.837 ;
     RECT  4.704 4.261 4.728 4.883 ;
     RECT  6.672 4.837 89.496 5.795 ;
     RECT  6.672 5.795 52.968 5.843 ;
     RECT  53.952 5.795 89.496 5.843 ;
     RECT  6.672 5.843 21.432 5.893 ;
     RECT  6.24 5.893 21.432 5.987 ;
     RECT  88.8 5.843 89.496 6.275 ;
     RECT  6.24 5.987 21.192 6.323 ;
     RECT  22.608 5.843 52.968 6.323 ;
     RECT  53.952 5.843 87.624 6.323 ;
     RECT  9.312 6.323 9.48 6.371 ;
     RECT  22.608 6.323 46.824 6.371 ;
     RECT  54.048 6.323 87.624 6.371 ;
     RECT  9.456 6.371 9.48 6.419 ;
     RECT  22.608 6.371 25.704 6.419 ;
     RECT  25.584 6.419 25.704 6.467 ;
     RECT  73.92 6.371 87.624 6.563 ;
     RECT  22.608 6.419 24.504 6.611 ;
     RECT  25.68 6.467 25.704 6.659 ;
     RECT  74.352 6.563 87.624 6.805 ;
     RECT  88.8 6.275 89.112 6.805 ;
     RECT  10.608 6.323 21.192 6.851 ;
     RECT  26.736 6.371 46.824 6.851 ;
     RECT  48.048 6.323 52.008 6.851 ;
     RECT  6.24 6.323 6.696 6.899 ;
     RECT  54.432 6.371 72.912 6.899 ;
     RECT  74.352 6.805 89.112 6.899 ;
     RECT  10.992 6.851 21.192 6.947 ;
     RECT  26.976 6.851 44.28 6.947 ;
     RECT  58.224 6.899 72.912 6.947 ;
     RECT  79.488 6.899 81.864 6.947 ;
     RECT  82.944 6.899 89.112 6.947 ;
     RECT  10.992 6.947 19.704 6.995 ;
     RECT  26.976 6.947 38.184 6.995 ;
     RECT  58.224 6.947 68.088 6.995 ;
     RECT  79.728 6.947 81.864 6.995 ;
     RECT  74.352 6.899 78.312 7.043 ;
     RECT  45.6 6.851 46.824 7.091 ;
     RECT  29.232 6.995 38.184 7.139 ;
     RECT  29.4 7.139 38.184 7.187 ;
     RECT  74.352 7.043 77.016 7.379 ;
     RECT  6.672 6.899 6.696 7.381 ;
     RECT  7.8 6.323 8.112 7.381 ;
     RECT  6.672 7.381 8.112 7.427 ;
     RECT  84.864 6.947 89.112 7.427 ;
     RECT  26.976 6.995 28.2 7.475 ;
     RECT  80.784 6.995 81.864 7.523 ;
     RECT  15.84 6.995 19.704 7.619 ;
     RECT  27.888 7.475 28.2 8.003 ;
     RECT  28.128 8.003 28.2 8.051 ;
     RECT  48.048 6.851 49.128 8.579 ;
     RECT  63.696 6.995 68.088 8.579 ;
     RECT  22.608 6.611 24.408 9.107 ;
     RECT  28.176 8.051 28.2 9.107 ;
     RECT  24 9.107 24.408 9.347 ;
     RECT  10.992 6.995 14.76 11.171 ;
     RECT  7.536 7.427 8.112 13.619 ;
     RECT  15.84 7.619 18.912 13.957 ;
     RECT  15.312 13.957 18.912 14.099 ;
     RECT  15.312 14.099 15.336 14.675 ;
     RECT  16.56 14.099 18.912 16.019 ;
     RECT  69.264 6.947 72.912 16.163 ;
     RECT  58.224 6.995 62.52 16.595 ;
     RECT  27.072 9.637 27.096 16.883 ;
     RECT  7.8 13.619 8.112 16.933 ;
     RECT  10.992 11.171 14.28 17.077 ;
     RECT  22.608 9.107 22.92 17.845 ;
     RECT  24 9.347 24.312 17.845 ;
     RECT  5.328 14.773 5.352 17.891 ;
     RECT  22.608 17.845 24.312 17.987 ;
     RECT  10.992 17.077 15.192 18.179 ;
     RECT  90.864 7.381 90.888 18.275 ;
     RECT  16.56 16.019 17.592 18.851 ;
     RECT  16.56 18.851 17.4 18.899 ;
     RECT  16.56 18.899 17.304 20.003 ;
     RECT  7.8 16.933 8.952 20.579 ;
     RECT  10.992 18.179 15.048 20.867 ;
     RECT  7.8 20.579 8.904 22.019 ;
     RECT  45.6 7.091 46.536 27.157 ;
     RECT  45.6 27.157 46.776 27.301 ;
     RECT  5.472 26.725 5.496 33.493 ;
     RECT  5.328 33.493 5.496 33.539 ;
     RECT  45.6 27.301 46.968 35.363 ;
     RECT  48.048 8.579 48.072 35.557 ;
     RECT  5.328 33.539 5.352 35.939 ;
     RECT  6.672 35.893 6.696 37.283 ;
     RECT  4.368 36.133 4.392 45.059 ;
     RECT  84.864 7.427 87.48 46.211 ;
     RECT  78 7.043 78.312 46.645 ;
     RECT  31.008 7.187 38.184 46.787 ;
     RECT  41.712 6.947 44.28 46.787 ;
     RECT  54.432 6.899 57.144 46.787 ;
     RECT  80.784 7.523 81.24 46.787 ;
     RECT  84.864 46.211 85.992 46.787 ;
     RECT  84.96 46.787 85.992 47.219 ;
     RECT  87.456 46.211 87.48 47.221 ;
     RECT  88.8 7.427 89.112 47.221 ;
     RECT  27.936 47.173 27.96 47.269 ;
     RECT  50.112 6.851 52.008 47.269 ;
     RECT  58.224 16.595 62.424 47.269 ;
     RECT  63.696 8.579 64.392 47.269 ;
     RECT  79.728 6.995 79.752 47.269 ;
     RECT  83.4 6.947 83.712 47.269 ;
     RECT  87.456 47.221 89.112 47.269 ;
     RECT  39.216 6.947 40.632 47.363 ;
     RECT  69.264 16.163 70.104 47.363 ;
     RECT  84.96 47.219 85.848 47.363 ;
     RECT  87.456 47.269 89.304 47.411 ;
     RECT  0.24 6.181 0.264 47.699 ;
     RECT  29.4 7.187 29.712 47.749 ;
     RECT  83.4 47.269 83.976 47.749 ;
     RECT  7.8 22.019 8.112 47.845 ;
     RECT  29.4 47.749 29.832 47.845 ;
     RECT  47.568 35.557 48.072 47.845 ;
     RECT  49.056 8.579 49.128 47.845 ;
     RECT  50.112 47.269 52.728 47.845 ;
     RECT  78 46.645 78.744 47.845 ;
     RECT  79.728 47.269 79.8 47.845 ;
     RECT  80.784 46.787 80.808 47.845 ;
     RECT  17.28 20.003 17.304 47.939 ;
     RECT  20.736 6.947 21.192 47.939 ;
     RECT  31.392 46.787 38.184 47.939 ;
     RECT  44.016 46.787 44.28 47.939 ;
     RECT  45.6 35.363 46.536 47.939 ;
     RECT  49.056 47.845 52.728 47.939 ;
     RECT  58.224 47.269 64.392 47.939 ;
     RECT  65.424 8.579 68.088 47.939 ;
     RECT  70.08 47.363 70.104 47.939 ;
     RECT  44.016 47.939 44.04 47.987 ;
     RECT  31.392 47.939 37.896 48.277 ;
     RECT  47.52 47.845 48.072 48.421 ;
     RECT  49.056 47.939 49.56 48.421 ;
     RECT  78 47.845 80.856 48.421 ;
     RECT  83.28 47.749 83.976 48.421 ;
     RECT  84.96 47.363 85.608 48.421 ;
     RECT  10.992 20.867 14.28 48.515 ;
     RECT  22.608 17.987 22.92 48.515 ;
     RECT  41.712 46.787 42.648 48.515 ;
     RECT  58.224 47.939 58.824 48.515 ;
     RECT  65.424 47.939 67.512 48.515 ;
     RECT  75.168 7.379 77.016 48.515 ;
     RECT  45.6 47.939 46.008 48.997 ;
     RECT  47.52 48.421 49.56 48.997 ;
     RECT  60.48 47.939 64.392 48.997 ;
     RECT  65.424 48.515 65.448 48.997 ;
     RECT  71.712 16.163 72.912 48.997 ;
     RECT  10.992 48.515 12.12 49.043 ;
     RECT  22.608 48.515 22.632 49.043 ;
     RECT  31.008 48.277 37.896 49.043 ;
     RECT  39.504 47.363 40.632 49.043 ;
     RECT  54.432 46.787 56.712 49.043 ;
     RECT  58.32 48.515 58.824 49.043 ;
     RECT  60.48 48.997 65.448 49.043 ;
     RECT  66.48 48.515 67.512 49.043 ;
     RECT  7.296 47.845 8.112 49.333 ;
     RECT  37.68 49.043 37.896 49.381 ;
     RECT  39.504 49.043 40.512 49.381 ;
     RECT  51 47.939 51.312 49.381 ;
     RECT  52.704 47.939 52.728 49.381 ;
     RECT  60.48 49.043 65.304 49.525 ;
     RECT  75.216 48.515 76.92 49.525 ;
     RECT  31.008 49.043 35.544 49.619 ;
     RECT  55.008 49.043 56.712 49.619 ;
     RECT  71.712 48.997 73.512 49.619 ;
     RECT  75.072 49.525 76.92 49.619 ;
     RECT  81.936 48.805 81.96 49.909 ;
     RECT  83.28 48.421 85.608 49.909 ;
     RECT  41.712 48.515 41.736 50.195 ;
     RECT  55.008 49.619 55.032 50.195 ;
     RECT  21.168 47.939 21.192 50.771 ;
     RECT  10.992 49.043 11.832 51.253 ;
     RECT  6.384 49.333 8.112 53.411 ;
     RECT  6.528 53.411 8.112 57.299 ;
     RECT  47.52 48.997 49.656 61.043 ;
     RECT  4.176 57.253 4.2 64.451 ;
     RECT  5.376 57.445 5.4 68.917 ;
     RECT  56.4 49.619 56.712 69.349 ;
     RECT  5.376 68.917 5.448 72.949 ;
     RECT  5.136 72.949 5.448 72.995 ;
     RECT  88.128 47.411 89.304 76.309 ;
     RECT  5.136 72.995 5.4 76.933 ;
     RECT  5.136 76.933 5.496 77.267 ;
     RECT  24 17.987 24.312 78.325 ;
     RECT  5.424 77.267 5.496 80.677 ;
     RECT  56.4 69.349 56.808 80.917 ;
     RECT  5.328 80.677 5.496 84.419 ;
     RECT  78 48.421 80.904 88.309 ;
     RECT  81.936 49.909 85.608 88.309 ;
     RECT  10.896 51.253 11.832 88.403 ;
     RECT  44.88 48.997 46.104 88.403 ;
     RECT  47.712 61.043 49.656 88.403 ;
     RECT  51 49.381 52.728 88.403 ;
     RECT  52.704 88.403 52.728 88.837 ;
     RECT  78 88.309 85.608 88.837 ;
     RECT  34.8 49.619 35.544 88.885 ;
     RECT  36.576 49.043 36.6 88.885 ;
     RECT  37.68 49.381 40.512 88.885 ;
     RECT  76.8 49.619 76.92 88.885 ;
     RECT  88.128 76.309 89.592 88.885 ;
     RECT  52.704 88.837 52.776 88.979 ;
     RECT  60.192 49.525 65.304 88.979 ;
     RECT  75.072 49.619 75.288 89.077 ;
     RECT  76.368 88.885 76.92 89.077 ;
     RECT  77.904 88.837 85.608 89.125 ;
     RECT  75.072 89.077 76.92 89.221 ;
     RECT  7.296 57.299 8.112 89.269 ;
     RECT  74.976 89.221 76.92 89.269 ;
     RECT  87.552 88.885 89.592 89.269 ;
     RECT  6.768 89.269 8.112 89.317 ;
     RECT  67.2 49.043 67.512 89.317 ;
     RECT  77.904 89.125 86.52 89.317 ;
     RECT  87.552 89.269 90.072 89.317 ;
     RECT  6.768 89.317 8.904 89.365 ;
     RECT  29.28 47.845 29.832 89.365 ;
     RECT  45.6 88.403 46.104 89.365 ;
     RECT  11.808 88.403 11.832 89.413 ;
     RECT  44.4 88.885 44.424 89.413 ;
     RECT  45.6 89.365 46.68 89.413 ;
     RECT  52.752 88.979 52.776 89.413 ;
     RECT  56.4 80.917 57.24 89.413 ;
     RECT  58.32 49.043 58.344 89.413 ;
     RECT  77.904 89.317 90.072 89.413 ;
     RECT  71.568 88.885 71.592 89.459 ;
     RECT  6.768 89.365 9.048 89.461 ;
     RECT  29.04 89.365 29.832 89.461 ;
     RECT  31.008 49.619 33.192 89.461 ;
     RECT  34.8 88.885 40.512 89.461 ;
     RECT  41.808 89.413 41.832 89.461 ;
     RECT  44.4 89.413 46.68 89.461 ;
     RECT  47.712 88.403 49.56 89.461 ;
     RECT  51 88.403 51.312 89.461 ;
     RECT  72.6 49.619 73.512 89.461 ;
     RECT  77.904 89.413 90.264 89.461 ;
     RECT  24 78.325 25.224 89.507 ;
     RECT  55.248 89.173 55.272 89.507 ;
     RECT  5.472 84.419 5.496 89.699 ;
     RECT  34.8 89.461 41.832 89.747 ;
     RECT  74.688 89.269 76.92 89.797 ;
     RECT  77.904 89.461 90.36 89.797 ;
     RECT  6.672 89.461 9.048 89.845 ;
     RECT  11.808 89.413 11.976 89.845 ;
     RECT  44.4 89.461 49.56 89.845 ;
     RECT  56.256 89.413 58.344 89.893 ;
     RECT  4.464 88.789 4.488 89.941 ;
     RECT  74.688 89.797 90.36 89.941 ;
     RECT  52.752 89.413 53.448 89.989 ;
     RECT  56.256 89.893 58.536 89.989 ;
     RECT  44.4 89.845 49.704 90.037 ;
     RECT  50.88 89.461 51.312 90.037 ;
     RECT  52.752 89.989 54.12 90.037 ;
     RECT  74.688 89.941 90.6 90.037 ;
     RECT  6.672 89.845 11.976 90.083 ;
     RECT  72.384 89.461 73.512 90.179 ;
     RECT  29.04 89.461 33.192 90.373 ;
     RECT  43.248 90.037 51.312 90.373 ;
     RECT  52.56 90.037 54.12 90.373 ;
     RECT  56.256 89.989 59.064 90.373 ;
     RECT  20.352 89.845 20.376 90.515 ;
     RECT  29.04 90.373 33.72 90.517 ;
     RECT  34.8 89.747 41.016 90.517 ;
     RECT  66.624 89.317 67.512 90.517 ;
     RECT  55.968 90.373 59.208 90.565 ;
     RECT  60.192 88.979 64.92 90.565 ;
     RECT  4.464 89.941 5.4 90.611 ;
     RECT  18.6 16.019 18.912 90.613 ;
     RECT  27.504 47.269 27.96 90.659 ;
     RECT  28.992 90.517 41.016 90.659 ;
     RECT  43.008 90.373 54.648 90.901 ;
     RECT  74.688 90.037 91.464 90.901 ;
     RECT  42.144 90.901 54.648 90.949 ;
     RECT  55.968 90.565 64.92 91.045 ;
     RECT  5.088 90.611 5.4 91.235 ;
     RECT  55.824 91.045 64.92 91.235 ;
     RECT  72.384 90.179 72.912 91.235 ;
     RECT  6.672 90.083 11.832 91.379 ;
     RECT  66.144 90.517 67.512 91.429 ;
     RECT  13.2 48.515 13.512 91.621 ;
     RECT  13.104 91.621 13.512 91.717 ;
     RECT  66.144 91.429 68.472 91.717 ;
     RECT  72.432 91.235 72.912 91.717 ;
     RECT  74.4 90.901 91.464 91.717 ;
     RECT  13.008 91.717 13.512 91.765 ;
     RECT  72.432 91.717 91.464 91.811 ;
     RECT  28.992 90.659 40.824 92.005 ;
     RECT  5.088 91.235 5.352 92.341 ;
     RECT  6.72 91.379 11.832 92.341 ;
     RECT  13.008 91.765 13.608 92.341 ;
     RECT  17.952 90.613 18.912 92.341 ;
     RECT  24 89.507 24.312 92.341 ;
     RECT  27.504 90.659 27.912 92.341 ;
     RECT  28.896 92.005 40.824 92.341 ;
     RECT  42.048 90.949 54.648 92.341 ;
     RECT  55.824 91.235 64.824 92.341 ;
     RECT  66 91.717 68.472 92.341 ;
     RECT  72.432 91.811 75.288 92.341 ;
     RECT  17.232 92.341 21.432 92.389 ;
     RECT  22.512 92.341 69.768 92.389 ;
     RECT  17.232 92.389 69.768 92.437 ;
     RECT  4.752 92.341 5.352 92.533 ;
     RECT  6.72 92.341 16.2 92.533 ;
     RECT  17.232 92.437 69.912 92.533 ;
     RECT  71.232 92.341 75.288 92.533 ;
     RECT  4.752 92.533 75.288 92.821 ;
     RECT  76.272 91.811 90.648 92.821 ;
     RECT  2.4 2.151 2.712 92.889 ;
     RECT  2.4 92.889 2.52 92.903 ;
     RECT  4.32 92.821 90.648 94.864 ;
     RECT  8.784 94.864 8.808 94.931 ;
     RECT  64.224 94.864 64.248 94.931 ;
     RECT  76.704 94.864 76.728 94.931 ;
     RECT  5.352 1.763 6.864 2.339 ;
     RECT  90.504 1.763 90.648 2.245 ;
     RECT  90.504 2.245 91.584 2.821 ;
     RECT  89.496 2.531 90.48 3.875 ;
     RECT  90.504 2.963 91.584 3.875 ;
     RECT  52.968 5.795 53.952 6.323 ;
     RECT  21.432 5.843 22.608 5.987 ;
     RECT  87.624 5.843 88.8 6.805 ;
     RECT  21.192 5.987 22.608 49.043 ;
     RECT  6.696 6.323 7.8 7.381 ;
     RECT  8.112 6.323 9.312 6.371 ;
     RECT  9.48 6.323 10.608 6.419 ;
     RECT  46.824 6.323 48.048 7.091 ;
     RECT  8.112 6.371 9.456 6.419 ;
     RECT  25.704 6.371 26.736 6.659 ;
     RECT  72.912 6.371 73.92 6.563 ;
     RECT  24.504 6.419 25.584 6.467 ;
     RECT  24.504 6.467 25.68 6.611 ;
     RECT  72.912 6.563 74.352 7.379 ;
     RECT  24.408 6.611 25.68 6.659 ;
     RECT  44.28 6.851 45.6 47.939 ;
     RECT  49.128 6.851 50.112 47.845 ;
     RECT  57.144 6.899 58.224 46.787 ;
     RECT  78.312 6.899 79.488 6.947 ;
     RECT  81.864 6.899 82.944 6.947 ;
     RECT  19.704 6.947 20.736 7.619 ;
     RECT  38.184 6.947 39.216 47.363 ;
     RECT  40.632 6.947 41.712 49.043 ;
     RECT  68.088 6.947 69.264 47.363 ;
     RECT  78.312 6.947 79.728 46.645 ;
     RECT  83.712 6.947 84.864 46.787 ;
     RECT  14.76 6.995 15.84 11.171 ;
     RECT  28.2 6.995 29.232 7.139 ;
     RECT  62.52 6.995 63.696 16.595 ;
     RECT  79.752 6.995 80.784 47.269 ;
     RECT  77.016 7.043 78 48.515 ;
     RECT  46.536 7.091 48.048 27.157 ;
     RECT  28.2 7.139 29.4 9.107 ;
     RECT  29.712 7.187 31.008 46.787 ;
     RECT  87.48 7.427 88.8 47.221 ;
     RECT  48.072 8.579 49.056 48.421 ;
     RECT  64.392 8.579 65.424 48.997 ;
     RECT  22.92 9.107 24 17.845 ;
     RECT  14.28 13.957 15.312 14.675 ;
     RECT  15.336 14.099 16.56 14.675 ;
     RECT  17.592 16.019 18.6 18.851 ;
     RECT  62.424 16.595 63.696 47.269 ;
     RECT  15.192 17.077 16.56 18.179 ;
     RECT  22.92 17.987 24 48.515 ;
     RECT  15.048 18.179 16.56 20.003 ;
     RECT  17.4 18.851 18.6 18.899 ;
     RECT  17.304 18.899 18.6 47.939 ;
     RECT  46.776 27.157 48.048 27.301 ;
     RECT  46.968 27.301 48.048 35.363 ;
     RECT  46.536 35.363 48.048 35.557 ;
     RECT  46.536 35.557 47.568 47.845 ;
     RECT  5.352 35.893 6.672 35.939 ;
     RECT  6.696 35.893 7.8 37.283 ;
     RECT  85.992 46.211 87.456 47.219 ;
     RECT  78.744 46.645 79.728 47.845 ;
     RECT  29.712 46.787 31.392 47.749 ;
     RECT  42.648 46.787 44.016 47.987 ;
     RECT  56.712 46.787 58.224 48.515 ;
     RECT  80.808 46.787 80.856 47.845 ;
     RECT  83.712 46.787 84.96 47.269 ;
     RECT  27.96 47.173 29.4 47.845 ;
     RECT  79.8 47.269 80.784 47.845 ;
     RECT  83.976 47.269 84.96 48.421 ;
     RECT  38.184 47.363 39.504 47.939 ;
     RECT  29.832 47.749 31.392 48.277 ;
     RECT  27.96 47.845 29.28 89.365 ;
     RECT  46.536 47.845 47.52 47.939 ;
     RECT  37.896 47.939 39.504 49.381 ;
     RECT  44.04 47.939 45.6 47.987 ;
     RECT  46.008 47.939 47.52 48.997 ;
     RECT  49.56 47.939 51 48.997 ;
     RECT  51.312 47.939 52.704 49.381 ;
     RECT  44.88 47.987 45.6 48.997 ;
     RECT  29.832 48.277 31.008 89.461 ;
     RECT  12.12 48.515 13.2 49.043 ;
     RECT  22.632 48.515 24 49.043 ;
     RECT  65.448 48.515 66.48 49.043 ;
     RECT  75.168 48.515 75.216 49.525 ;
     RECT  76.92 48.515 78 88.837 ;
     RECT  80.904 48.805 81.936 88.309 ;
     RECT  81.96 48.805 83.28 49.909 ;
     RECT  46.104 48.997 47.52 61.043 ;
     RECT  49.656 48.997 51 88.403 ;
     RECT  11.832 49.043 13.2 89.413 ;
     RECT  35.544 49.043 36.576 88.885 ;
     RECT  36.6 49.043 37.68 88.885 ;
     RECT  40.512 49.043 41.712 50.195 ;
     RECT  55.032 49.619 56.4 50.195 ;
     RECT  75.288 49.619 76.8 88.885 ;
     RECT  2.712 57.253 4.176 64.451 ;
     RECT  4.2 57.445 5.376 64.451 ;
     RECT  56.808 69.349 58.32 80.917 ;
     RECT  57.24 80.917 58.32 89.413 ;
     RECT  10.896 88.403 11.808 89.845 ;
     RECT  44.88 88.403 45.6 88.885 ;
     RECT  49.56 88.403 51 89.461 ;
     RECT  51.312 88.403 52.704 88.979 ;
     RECT  4.488 88.789 5.472 89.699 ;
     RECT  76.92 88.837 77.904 89.797 ;
     RECT  44.424 88.885 45.6 89.413 ;
     RECT  71.592 88.885 72.6 89.459 ;
     RECT  75.288 88.885 76.368 89.077 ;
     RECT  51.312 88.979 52.752 90.037 ;
     RECT  86.52 89.125 87.552 89.317 ;
     RECT  55.272 89.173 56.4 89.413 ;
     RECT  73.512 89.221 74.976 89.269 ;
     RECT  5.496 89.269 6.768 89.461 ;
     RECT  73.512 89.269 74.688 90.179 ;
     RECT  27.96 89.365 29.04 90.517 ;
     RECT  46.68 89.365 47.712 89.461 ;
     RECT  11.976 89.413 13.2 90.083 ;
     RECT  40.512 89.413 41.808 89.461 ;
     RECT  55.272 89.413 56.256 89.507 ;
     RECT  72.384 89.459 72.6 89.461 ;
     RECT  5.496 89.461 6.672 89.699 ;
     RECT  49.56 89.461 50.88 89.845 ;
     RECT  55.248 89.507 56.256 89.989 ;
     RECT  4.488 89.699 6.672 89.941 ;
     RECT  41.016 89.747 41.832 90.037 ;
     RECT  18.912 89.845 20.352 90.515 ;
     RECT  49.704 89.845 50.88 90.037 ;
     RECT  5.4 89.941 6.672 91.235 ;
     RECT  54.12 89.989 56.256 90.373 ;
     RECT  59.064 89.989 60.192 90.373 ;
     RECT  41.016 90.037 43.248 90.373 ;
     RECT  51.312 90.037 52.56 90.373 ;
     RECT  11.832 90.083 13.2 91.621 ;
     RECT  72.912 90.179 74.688 90.901 ;
     RECT  33.72 90.373 34.8 90.517 ;
     RECT  41.016 90.373 43.008 90.659 ;
     RECT  54.648 90.373 55.968 91.045 ;
     RECT  59.208 90.373 60.192 90.565 ;
     RECT  27.96 90.517 28.992 90.659 ;
     RECT  64.92 90.517 66.144 91.235 ;
     RECT  27.912 90.659 28.992 92.005 ;
     RECT  40.824 90.659 43.008 90.901 ;
     RECT  40.824 90.901 42.144 90.949 ;
     RECT  72.912 90.901 74.4 91.717 ;
     RECT  40.824 90.949 42.048 92.341 ;
     RECT  54.648 91.045 55.824 92.341 ;
     RECT  5.352 91.235 6.672 91.379 ;
     RECT  64.824 91.235 66.144 91.717 ;
     RECT  72.384 91.235 72.432 92.341 ;
     RECT  5.352 91.379 6.72 92.533 ;
     RECT  11.832 91.621 13.104 91.717 ;
     RECT  11.832 91.717 13.008 92.341 ;
     RECT  64.824 91.717 66 92.341 ;
     RECT  75.288 91.811 76.272 92.821 ;
     RECT  27.912 92.005 28.896 92.341 ;
     RECT  16.2 92.341 17.232 92.533 ;
     RECT  21.432 92.341 22.512 92.389 ;
     RECT  69.768 92.341 71.232 92.437 ;
     RECT  69.912 92.437 71.232 92.533 ;
  END
END dsfd_vm_static_landing_lane0
END LIBRARY
